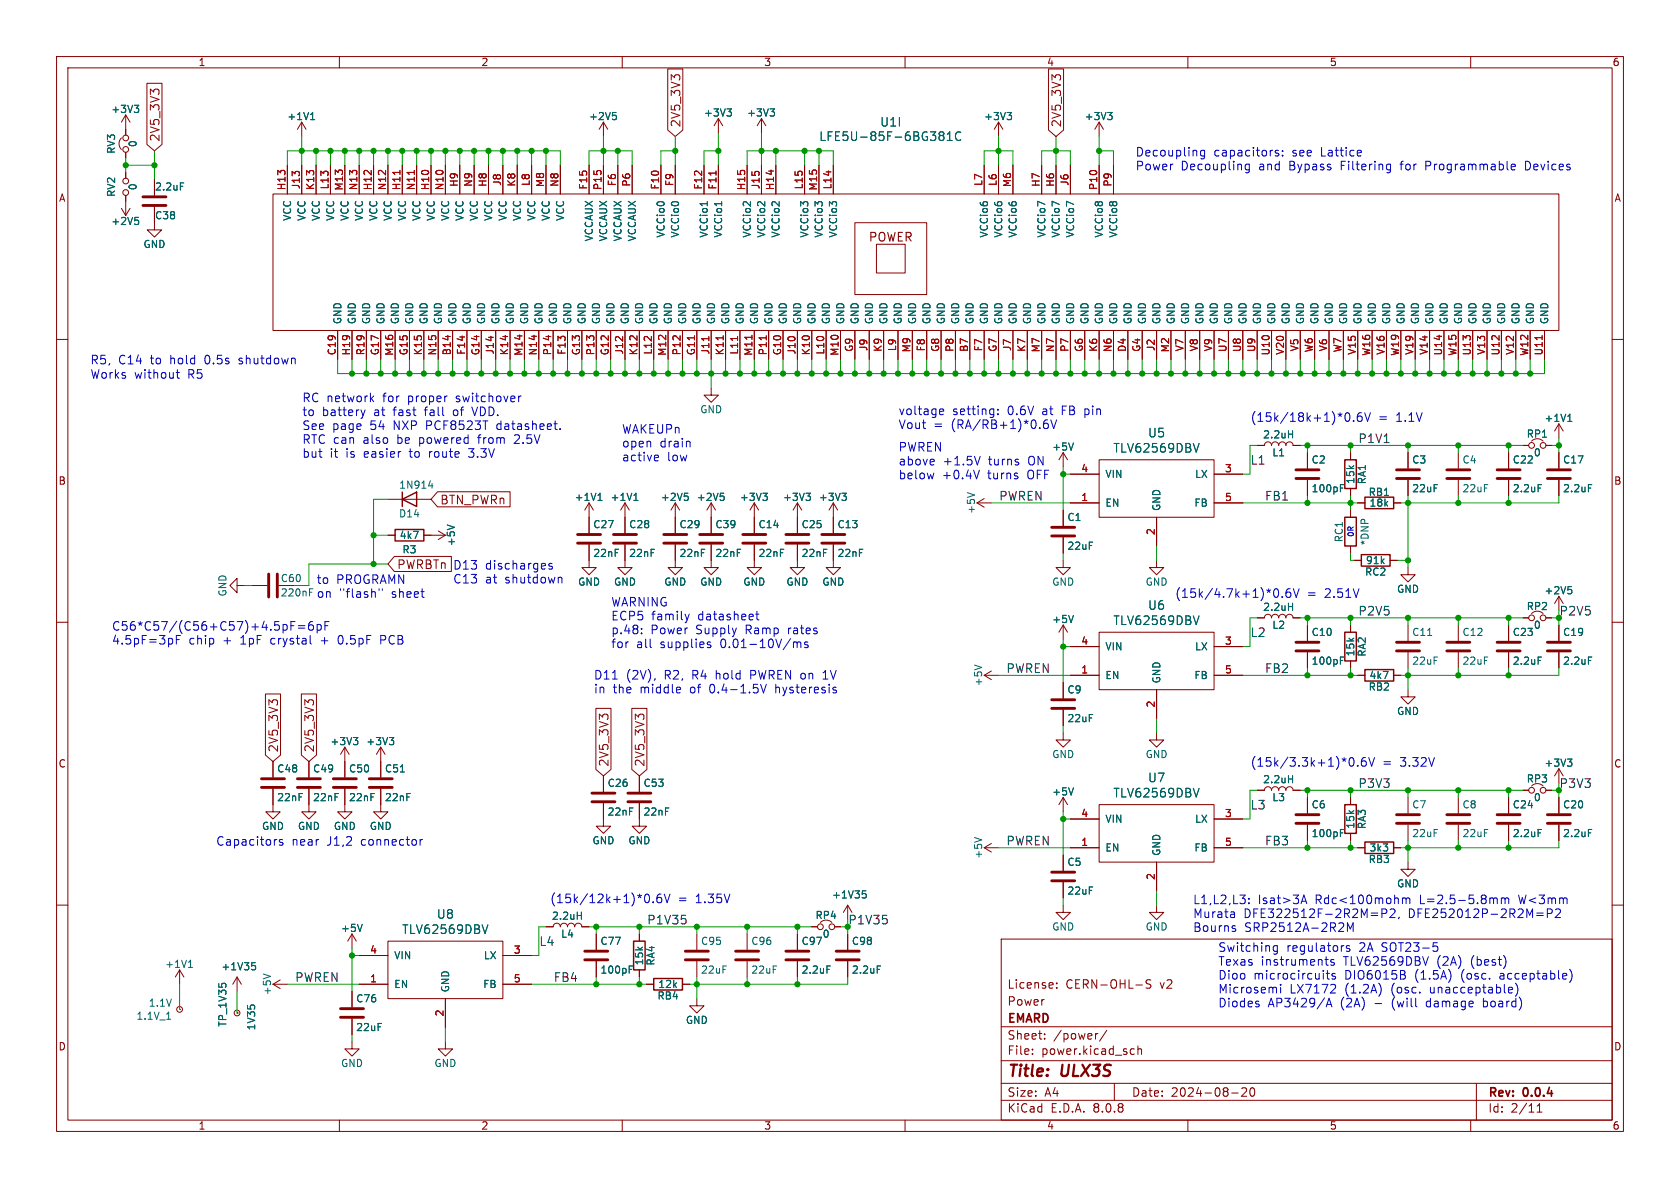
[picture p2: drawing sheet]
<svg xmlns="http://www.w3.org/2000/svg" width="297mm" height="210mm" viewBox="0 0 297 210" stroke-linecap="round" stroke-linejoin="round" font-family="sans-serif">
<defs><g id="words">
<g font-size="2.8" fill="#840000">
<text x="178" y="190.9">Title:</text>
<text x="187.7" y="190.9">ULX3S</text>
</g>
<g font-size="2.1" fill="#840000">
<text x="120.5" y="22.6" transform="rotate(-90 120.5 22.6)">2V5_3V3</text>
<text x="187.8" y="22.6" transform="rotate(-90 187.8 22.6)">2V5_3V3</text>
<text x="28.4" y="25.1" transform="rotate(-90 28.4 25.1)">2V5_3V3</text>
<text x="153.5" y="43">POWER</text>
<text x="77.7" y="89.4">BTN_PWRn</text>
<text x="49.4" y="133.1" transform="rotate(-90 49.4 133.1)">2V5_3V3</text>
<text x="55.7" y="133.1" transform="rotate(-90 55.7 133.1)">2V5_3V3</text>
<text x="107.8" y="135.6" transform="rotate(-90 107.8 135.6)">2V5_3V3</text>
<text x="114.1" y="135.6" transform="rotate(-90 114.1 135.6)">2V5_3V3</text>
<text x="178" y="178">Power</text>
<text x="178" y="175">License:</text>
<text x="188.4" y="175">CERN-OHL-S</text>
<text x="205.1" y="175">v2</text>
<text x="178" y="184">Sheet:</text>
<text x="178" y="181.2">EMARD</text>
<text x="186.2" y="184">/power/</text>
<text x="178" y="186.7">File:</text>
<text x="184.1" y="186.7">power.kicad_sch</text>
<text x="178" y="196.9">KiCad</text>
<text x="178" y="194.1">Size:</text>
<text x="184.7" y="194.1">A4</text>
<text x="185.7" y="196.9">E.D.A.</text>
<text x="193.3" y="196.9">8.0.8</text>
<text x="200" y="194.1">Date:</text>
<text x="207" y="194.1">2024-08-20</text>
<text x="263" y="194.3">Rev:</text>
<text x="263" y="196.9">Id:</text>
<text x="267.1" y="196.9">2/11</text>
<text x="269.4" y="194.3">0.0.4</text>
</g>
<g font-size="2.1" fill="#006464">
<text x="155.5" y="22.6">U1I</text>
<text x="144.7" y="25.1">LFE5U-85F-6BG381C</text>
<text x="202.9" y="77.5">U5</text>
<text x="196.7" y="80.2">TLV62569DBV</text>
<text x="196.7" y="110.7">TLV62569DBV</text>
<text x="202.9" y="108">U6</text>
<text x="196.7" y="141.2">TLV62569DBV</text>
<text x="202.9" y="138.5">U7</text>
<text x="71" y="165.3">TLV62569DBV</text>
<text x="77.1" y="162.6">U8</text>
</g>
<g font-size="2.1" fill="#0000c2">
<text x="200.7" y="27.8">Decoupling</text>
<text x="214.5" y="27.8">capacitors:</text>
<text x="228.5" y="27.8">see</text>
<text x="233.6" y="27.8">Lattice</text>
<text x="200.7" y="30.2">Power</text>
<text x="208.7" y="30.2">Decoupling</text>
<text x="222.6" y="30.2">and</text>
<text x="228" y="30.2">Bypass</text>
<text x="237.3" y="30.2">Filtering</text>
<text x="248" y="30.2">for</text>
<text x="252.5" y="30.2">Programmable</text>
<text x="270.3" y="30.2">Devices</text>
<text x="15.9" y="64.5">R5,</text>
<text x="20.9" y="64.5">C14</text>
<text x="26.6" y="64.5">to</text>
<text x="30.2" y="64.5">hold</text>
<text x="36.4" y="64.5">0.5s</text>
<text x="42.6" y="64.5">shutdown</text>
<text x="15.9" y="67.1">Works</text>
<text x="23.7" y="67.1">without</text>
<text x="33.2" y="67.1">R5</text>
<text x="53.3" y="71.2">RC network</text>
<text x="67.7" y="71.2">for</text>
<text x="72.2" y="71.2">proper</text>
<text x="80.9" y="71.2">switchover</text>
<text x="53.3" y="73.7">to</text>
<text x="53.3" y="76.1">See</text>
<text x="56.9" y="73.7">battery</text>
<text x="58.7" y="76.1">page</text>
<text x="65.5" y="76.1">54</text>
<text x="66.1" y="73.7">at</text>
<text x="69.7" y="76.1">NXP</text>
<text x="69.7" y="73.7">fast</text>
<text x="75.4" y="73.7">fall</text>
<text x="75.6" y="76.1">PCF8523T</text>
<text x="80.5" y="73.7">of</text>
<text x="84.1" y="73.7">VDD.</text>
<text x="88.2" y="76.1">datasheet.</text>
<text x="109.9" y="76.8">WAKEUPn</text>
<text x="158.7" y="73.5">voltage</text>
<text x="158.7" y="76">Vout</text>
<text x="165" y="76">=</text>
<text x="168.2" y="76">(RA/RB+1)*0.6V</text>
<text x="168.3" y="73.5">setting:</text>
<text x="178.1" y="73.5">0.6V</text>
<text x="184.4" y="73.5">at</text>
<text x="188" y="73.5">FB pin</text>
<text x="221" y="74.7">(15k/18k+1)*0.6V</text>
<text x="243.6" y="74.7">=</text>
<text x="246.8" y="74.7">1.1V</text>
<text x="53.3" y="78.6">RTC can</text>
<text x="53.3" y="81">but</text>
<text x="58.3" y="81">it</text>
<text x="61.2" y="81">is</text>
<text x="64.2" y="78.6">also</text>
<text x="64.5" y="81">easier</text>
<text x="70.3" y="78.6">be</text>
<text x="72.7" y="81">to</text>
<text x="74.3" y="78.6">powered</text>
<text x="76.2" y="81">route</text>
<text x="83.4" y="81">3.3V</text>
<text x="84.9" y="78.6">from</text>
<text x="91.5" y="78.6">2.5V</text>
<text x="109.9" y="79.2">open</text>
<text x="109.9" y="81.7">active</text>
<text x="116.6" y="79.2">drain</text>
<text x="117.9" y="81.7">low</text>
<text x="158.7" y="79.9">PWREN</text>
<text x="158.7" y="82.4">above</text>
<text x="166.7" y="82.4">+1.5V</text>
<text x="174.8" y="82.4">turns</text>
<text x="181.9" y="82.4">ON</text>
<text x="158.7" y="84.8">below</text>
<text x="166.5" y="84.8">+0.4V</text>
<text x="174.7" y="84.8">turns</text>
<text x="181.8" y="84.8">OFF</text>
<text x="70.1" y="100.8">PWRBTn D13</text>
<text x="85.8" y="100.8">discharges</text>
<text x="55.9" y="103.3">to</text>
<text x="55.9" y="105.8">on</text>
<text x="59.4" y="103.3">PROGRAMN</text>
<text x="60" y="105.8">&quot;flash&quot;</text>
<text x="69.2" y="105.8">sheet</text>
<text x="80" y="103.3">C13</text>
<text x="85.8" y="103.3">at</text>
<text x="89.3" y="103.3">shutdown</text>
<text x="107.9" y="107.3">WARNING</text>
<text x="207.6" y="105.8">(15k/4.7k+1)*0.6V</text>
<text x="231" y="105.8">=</text>
<text x="234.2" y="105.8">2.51V</text>
<text x="19.7" y="111.6">C56*C57/(C56+C57)+4.5pF=6pF</text>
<text x="107.9" y="109.8">ECP5</text>
<text x="107.9" y="112.2">p.48:</text>
<text x="115" y="112.2">Power</text>
<text x="115.1" y="109.8">family</text>
<text x="123.1" y="112.2">Supply</text>
<text x="123.4" y="109.8">datasheet</text>
<text x="131.9" y="112.2">Ramp</text>
<text x="139.5" y="112.2">rates</text>
<text x="19.7" y="114.1">4.5pF=3pF</text>
<text x="33.3" y="114.1">chip</text>
<text x="39.4" y="114.1">+</text>
<text x="42.6" y="114.1">1pF</text>
<text x="48.1" y="114.1">crystal</text>
<text x="57.1" y="114.1">+</text>
<text x="60.3" y="114.1">0.5pF</text>
<text x="67.9" y="114.1">PCB</text>
<text x="107.9" y="114.7">for</text>
<text x="112.5" y="114.7">all</text>
<text x="116.7" y="114.7">supplies</text>
<text x="127.5" y="114.7">0.01-10V/ms</text>
<text x="104.9" y="120.2">D11</text>
<text x="104.9" y="122.7">in</text>
<text x="108.3" y="122.7">the</text>
<text x="110.6" y="120.2">(2V),</text>
<text x="113.2" y="122.7">middle</text>
<text x="117.5" y="120.2">R2,</text>
<text x="122.1" y="122.7">of</text>
<text x="122.5" y="120.2">R4</text>
<text x="125.7" y="122.7">0.4-1.5V</text>
<text x="126.8" y="120.2">hold</text>
<text x="133" y="120.2">PWREN on</text>
<text x="137.5" y="122.7">hysteresis</text>
<text x="146.2" y="120.2">1V</text>
<text x="221" y="135.6">(15k/3.3k+1)*0.6V</text>
<text x="244.4" y="135.6">=</text>
<text x="247.6" y="135.6">3.32V</text>
<text x="38.1" y="149.6">Capacitors</text>
<text x="51.5" y="149.6">near</text>
<text x="57.9" y="149.6">J1,2</text>
<text x="64" y="149.6">connector</text>
<text x="97.2" y="159.8">(15k/12k+1)*0.6V</text>
<text x="119.8" y="159.8">=</text>
<text x="123" y="159.8">1.35V</text>
<text x="210.8" y="159.9">L1,L2,L3:</text>
<text x="222.4" y="159.9">Isat&gt;3A</text>
<text x="232.5" y="159.9">Rdc&lt;100mohm</text>
<text x="251.1" y="159.9">L=2.5-5.8mm</text>
<text x="268.8" y="159.9">W&lt;3mm</text>
<text x="210.8" y="162.4">Murata</text>
<text x="210.8" y="164.9">Bourns</text>
<text x="219.8" y="162.4">DFE322512F-2R2M=P2,</text>
<text x="220" y="164.9">SRP2512A-2R2M</text>
<text x="249" y="162.4">DFE252012P-2R2M=P2</text>
<text x="215.3" y="168.4">Switching</text>
<text x="215.3" y="170.8">Texas</text>
<text x="215.3" y="173.3">Dioo</text>
<text x="221.6" y="173.3">microcircuits</text>
<text x="222.9" y="170.8">instruments</text>
<text x="227.4" y="168.4">regulators</text>
<text x="237.6" y="170.8">TLV62569DBV</text>
<text x="237.8" y="173.3">DIO6015B</text>
<text x="240.3" y="168.4">2A SOT23-5</text>
<text x="250.3" y="173.3">(1.5A)</text>
<text x="254.2" y="170.8">(2A)</text>
<text x="258.5" y="173.3">(osc.</text>
<text x="260.3" y="170.8">(best)</text>
<text x="265.5" y="173.3">acceptable)</text>
<text x="215.3" y="175.7">Microsemi</text>
<text x="215.3" y="178.2">Diodes</text>
<text x="224.1" y="178.2">AP3429/A</text>
<text x="228" y="175.7">LX7172</text>
<text x="237" y="178.2">(2A)</text>
<text x="237.8" y="175.7">(1.2A)</text>
<text x="243.1" y="178.2">-</text>
<text x="246.1" y="175.7">(osc.</text>
<text x="246.3" y="178.2">(will</text>
<text x="252.5" y="178.2">damage</text>
<text x="253" y="175.7">unacceptable)</text>
<text x="262.7" y="178.2">board)</text>
</g>
<g font-size="2.1" fill="#0f0f0f">
<text x="221" y="82.2">L1</text>
<text x="240" y="78.4">P1V1</text>
<text x="176.5" y="88.6">PWREN</text>
<text x="223.5" y="88.6">FB1</text>
<text x="221" y="112.7">L2</text>
<text x="240" y="108.9">P2V5</text>
<text x="177.8" y="119.1">PWREN</text>
<text x="223.5" y="119.1">FB2</text>
<text x="221" y="143.2">L3</text>
<text x="240" y="139.4">P3V3</text>
<text x="177.8" y="149.5">PWREN</text>
<text x="223.5" y="149.5">FB3</text>
<text x="95.2" y="167.3">L4</text>
<text x="114.3" y="163.5">P1V35</text>
<text x="52.1" y="173.7">PWREN</text>
<text x="97.8" y="173.7">FB4</text>
</g>
<g font-size="2.1" fill="#009600">
<text x="275.6" y="108.9">P2V5</text>
<text x="275.6" y="139.4">P3V3</text>
<text x="149.9" y="163.5">P1V35</text>
</g>
<g font-size="1.8" fill="#840000">
<text x="35" y="11.9">1</text>
<text x="85" y="11.9">2</text>
<text x="135" y="11.9">3</text>
<text x="185" y="11.9">4</text>
<text x="235" y="11.9">5</text>
<text x="285" y="11.9">6</text>
<text x="10.3" y="35.9">A</text>
<text x="285.3" y="35.9">A</text>
<text x="10.3" y="85.9">B</text>
<text x="285.3" y="85.9">B</text>
<text x="10.3" y="135.9">C</text>
<text x="285.3" y="135.9">C</text>
<text x="10.3" y="185.9">D</text>
<text x="285.3" y="185.9">D</text>
<text x="35" y="199.9">1</text>
<text x="85" y="199.9">2</text>
<text x="135" y="199.9">3</text>
<text x="185" y="199.9">4</text>
<text x="235" y="199.9">5</text>
<text x="285" y="199.9">6</text>
</g>
<g font-size="1.8" fill="#006464">
<text x="19.6" y="20.2">+3V3</text>
<text x="50.7" y="21.4">+1V1</text>
<text x="104" y="21.4">+2V5</text>
<text x="124.4" y="20.8">+3V3</text>
<text x="132" y="20.8">+3V3</text>
<text x="173.9" y="21.4">+3V3</text>
<text x="191.7" y="21.4">+3V3</text>
<text x="20.5" y="27.3" transform="rotate(-90 20.5 27.3)">RV3</text>
<text x="24.4" y="26.1" transform="rotate(-90 24.4 26.1)">0</text>
<text x="20.5" y="34.9" transform="rotate(-90 20.5 34.9)">RV2</text>
<text x="24.4" y="33.7" transform="rotate(-90 24.4 33.7)">0</text>
<text x="27.3" y="33.9">2.2uF</text>
<text x="19.6" y="40">+2V5</text>
<text x="27.3" y="39">C38</text>
<text x="51.7" y="39.1" transform="rotate(-90 51.7 39.1)">VCC</text>
<text x="54.2" y="39.1" transform="rotate(-90 54.2 39.1)">VCC</text>
<text x="56.7" y="39.1" transform="rotate(-90 56.7 39.1)">VCC</text>
<text x="59.3" y="39.1" transform="rotate(-90 59.3 39.1)">VCC</text>
<text x="61.8" y="39.1" transform="rotate(-90 61.8 39.1)">VCC</text>
<text x="64.4" y="39.1" transform="rotate(-90 64.4 39.1)">VCC</text>
<text x="66.9" y="39.1" transform="rotate(-90 66.9 39.1)">VCC</text>
<text x="69.4" y="39.1" transform="rotate(-90 69.4 39.1)">VCC</text>
<text x="72" y="39.1" transform="rotate(-90 72 39.1)">VCC</text>
<text x="74.5" y="39.1" transform="rotate(-90 74.5 39.1)">VCC</text>
<text x="77.1" y="39.1" transform="rotate(-90 77.1 39.1)">VCC</text>
<text x="79.6" y="39.1" transform="rotate(-90 79.6 39.1)">VCC</text>
<text x="82.1" y="39.1" transform="rotate(-90 82.1 39.1)">VCC</text>
<text x="84.7" y="39.1" transform="rotate(-90 84.7 39.1)">VCC</text>
<text x="87.2" y="39.1" transform="rotate(-90 87.2 39.1)">VCC</text>
<text x="89.8" y="39.1" transform="rotate(-90 89.8 39.1)">VCC</text>
<text x="92.3" y="39.1" transform="rotate(-90 92.3 39.1)">VCC</text>
<text x="94.8" y="39.1" transform="rotate(-90 94.8 39.1)">VCC</text>
<text x="97.4" y="39.1" transform="rotate(-90 97.4 39.1)">VCC</text>
<text x="99.9" y="39.1" transform="rotate(-90 99.9 39.1)">VCC</text>
<text x="25.3" y="44">GND</text>
<text x="105" y="42.8" transform="rotate(-90 105 42.8)">VCCAUX</text>
<text x="107.5" y="42.8" transform="rotate(-90 107.5 42.8)">VCCAUX</text>
<text x="110.1" y="42.8" transform="rotate(-90 110.1 42.8)">VCCAUX</text>
<text x="112.6" y="42.8" transform="rotate(-90 112.6 42.8)">VCCAUX</text>
<text x="117.7" y="42.1" transform="rotate(-90 117.7 42.1)">VCCio0</text>
<text x="120.2" y="42.1" transform="rotate(-90 120.2 42.1)">VCCio0</text>
<text x="125.3" y="42.1" transform="rotate(-90 125.3 42.1)">VCCio1</text>
<text x="127.9" y="42.1" transform="rotate(-90 127.9 42.1)">VCCio1</text>
<text x="132.9" y="42.1" transform="rotate(-90 132.9 42.1)">VCCio2</text>
<text x="135.5" y="42.1" transform="rotate(-90 135.5 42.1)">VCCio2</text>
<text x="138" y="42.1" transform="rotate(-90 138 42.1)">VCCio2</text>
<text x="143.1" y="42.1" transform="rotate(-90 143.1 42.1)">VCCio3</text>
<text x="145.6" y="42.1" transform="rotate(-90 145.6 42.1)">VCCio3</text>
<text x="148.2" y="42.1" transform="rotate(-90 148.2 42.1)">VCCio3</text>
<text x="174.9" y="42.1" transform="rotate(-90 174.9 42.1)">VCCio6</text>
<text x="177.4" y="42.1" transform="rotate(-90 177.4 42.1)">VCCio6</text>
<text x="179.9" y="42.1" transform="rotate(-90 179.9 42.1)">VCCio6</text>
<text x="185" y="42.1" transform="rotate(-90 185 42.1)">VCCio7</text>
<text x="187.6" y="42.1" transform="rotate(-90 187.6 42.1)">VCCio7</text>
<text x="190.1" y="42.1" transform="rotate(-90 190.1 42.1)">VCCio7</text>
<text x="195.2" y="42.1" transform="rotate(-90 195.2 42.1)">VCCio8</text>
<text x="197.7" y="42.1" transform="rotate(-90 197.7 42.1)">VCCio8</text>
<text x="60.6" y="57.4" transform="rotate(-90 60.6 57.4)">GND</text>
<text x="63.1" y="57.4" transform="rotate(-90 63.1 57.4)">GND</text>
<text x="65.6" y="57.4" transform="rotate(-90 65.6 57.4)">GND</text>
<text x="68.2" y="57.4" transform="rotate(-90 68.2 57.4)">GND</text>
<text x="70.7" y="57.4" transform="rotate(-90 70.7 57.4)">GND</text>
<text x="73.3" y="57.4" transform="rotate(-90 73.3 57.4)">GND</text>
<text x="75.8" y="57.4" transform="rotate(-90 75.8 57.4)">GND</text>
<text x="78.3" y="57.4" transform="rotate(-90 78.3 57.4)">GND</text>
<text x="80.9" y="57.4" transform="rotate(-90 80.9 57.4)">GND</text>
<text x="83.4" y="57.4" transform="rotate(-90 83.4 57.4)">GND</text>
<text x="86" y="57.4" transform="rotate(-90 86 57.4)">GND</text>
<text x="88.5" y="57.4" transform="rotate(-90 88.5 57.4)">GND</text>
<text x="91" y="57.4" transform="rotate(-90 91 57.4)">GND</text>
<text x="93.6" y="57.4" transform="rotate(-90 93.6 57.4)">GND</text>
<text x="96.1" y="57.4" transform="rotate(-90 96.1 57.4)">GND</text>
<text x="98.7" y="57.4" transform="rotate(-90 98.7 57.4)">GND</text>
<text x="101.2" y="57.4" transform="rotate(-90 101.2 57.4)">GND</text>
<text x="103.7" y="57.4" transform="rotate(-90 103.7 57.4)">GND</text>
<text x="106.3" y="57.4" transform="rotate(-90 106.3 57.4)">GND</text>
<text x="108.8" y="57.4" transform="rotate(-90 108.8 57.4)">GND</text>
<text x="111.4" y="57.4" transform="rotate(-90 111.4 57.4)">GND</text>
<text x="113.9" y="57.4" transform="rotate(-90 113.9 57.4)">GND</text>
<text x="116.4" y="57.4" transform="rotate(-90 116.4 57.4)">GND</text>
<text x="119" y="57.4" transform="rotate(-90 119 57.4)">GND</text>
<text x="121.5" y="57.4" transform="rotate(-90 121.5 57.4)">GND</text>
<text x="124.1" y="57.4" transform="rotate(-90 124.1 57.4)">GND</text>
<text x="126.6" y="57.4" transform="rotate(-90 126.6 57.4)">GND</text>
<text x="129.1" y="57.4" transform="rotate(-90 129.1 57.4)">GND</text>
<text x="131.7" y="57.4" transform="rotate(-90 131.7 57.4)">GND</text>
<text x="134.2" y="57.4" transform="rotate(-90 134.2 57.4)">GND</text>
<text x="136.8" y="57.4" transform="rotate(-90 136.8 57.4)">GND</text>
<text x="139.3" y="57.4" transform="rotate(-90 139.3 57.4)">GND</text>
<text x="141.8" y="57.4" transform="rotate(-90 141.8 57.4)">GND</text>
<text x="144.4" y="57.4" transform="rotate(-90 144.4 57.4)">GND</text>
<text x="146.9" y="57.4" transform="rotate(-90 146.9 57.4)">GND</text>
<text x="149.5" y="57.4" transform="rotate(-90 149.5 57.4)">GND</text>
<text x="152" y="57.4" transform="rotate(-90 152 57.4)">GND</text>
<text x="154.5" y="57.4" transform="rotate(-90 154.5 57.4)">GND</text>
<text x="157.1" y="57.4" transform="rotate(-90 157.1 57.4)">GND</text>
<text x="159.6" y="57.4" transform="rotate(-90 159.6 57.4)">GND</text>
<text x="162.2" y="57.4" transform="rotate(-90 162.2 57.4)">GND</text>
<text x="164.7" y="57.4" transform="rotate(-90 164.7 57.4)">GND</text>
<text x="167.2" y="57.4" transform="rotate(-90 167.2 57.4)">GND</text>
<text x="169.8" y="57.4" transform="rotate(-90 169.8 57.4)">GND</text>
<text x="172.3" y="57.4" transform="rotate(-90 172.3 57.4)">GND</text>
<text x="174.9" y="57.4" transform="rotate(-90 174.9 57.4)">GND</text>
<text x="177.4" y="57.4" transform="rotate(-90 177.4 57.4)">GND</text>
<text x="179.9" y="57.4" transform="rotate(-90 179.9 57.4)">GND</text>
<text x="182.5" y="57.4" transform="rotate(-90 182.5 57.4)">GND</text>
<text x="185" y="57.4" transform="rotate(-90 185 57.4)">GND</text>
<text x="187.6" y="57.4" transform="rotate(-90 187.6 57.4)">GND</text>
<text x="190.1" y="57.4" transform="rotate(-90 190.1 57.4)">GND</text>
<text x="192.6" y="57.4" transform="rotate(-90 192.6 57.4)">GND</text>
<text x="195.2" y="57.4" transform="rotate(-90 195.2 57.4)">GND</text>
<text x="197.7" y="57.4" transform="rotate(-90 197.7 57.4)">GND</text>
<text x="200.3" y="57.4" transform="rotate(-90 200.3 57.4)">GND</text>
<text x="202.8" y="57.4" transform="rotate(-90 202.8 57.4)">GND</text>
<text x="205.3" y="57.4" transform="rotate(-90 205.3 57.4)">GND</text>
<text x="207.9" y="57.4" transform="rotate(-90 207.9 57.4)">GND</text>
<text x="210.4" y="57.4" transform="rotate(-90 210.4 57.4)">GND</text>
<text x="213" y="57.4" transform="rotate(-90 213 57.4)">GND</text>
<text x="215.5" y="57.4" transform="rotate(-90 215.5 57.4)">GND</text>
<text x="218" y="57.4" transform="rotate(-90 218 57.4)">GND</text>
<text x="220.6" y="57.4" transform="rotate(-90 220.6 57.4)">GND</text>
<text x="223.1" y="57.4" transform="rotate(-90 223.1 57.4)">GND</text>
<text x="225.7" y="57.4" transform="rotate(-90 225.7 57.4)">GND</text>
<text x="228.2" y="57.4" transform="rotate(-90 228.2 57.4)">GND</text>
<text x="230.7" y="57.4" transform="rotate(-90 230.7 57.4)">GND</text>
<text x="233.3" y="57.4" transform="rotate(-90 233.3 57.4)">GND</text>
<text x="235.8" y="57.4" transform="rotate(-90 235.8 57.4)">GND</text>
<text x="238.4" y="57.4" transform="rotate(-90 238.4 57.4)">GND</text>
<text x="240.9" y="57.4" transform="rotate(-90 240.9 57.4)">GND</text>
<text x="243.4" y="57.4" transform="rotate(-90 243.4 57.4)">GND</text>
<text x="246" y="57.4" transform="rotate(-90 246 57.4)">GND</text>
<text x="248.5" y="57.4" transform="rotate(-90 248.5 57.4)">GND</text>
<text x="251.1" y="57.4" transform="rotate(-90 251.1 57.4)">GND</text>
<text x="253.6" y="57.4" transform="rotate(-90 253.6 57.4)">GND</text>
<text x="256.1" y="57.4" transform="rotate(-90 256.1 57.4)">GND</text>
<text x="258.7" y="57.4" transform="rotate(-90 258.7 57.4)">GND</text>
<text x="261.2" y="57.4" transform="rotate(-90 261.2 57.4)">GND</text>
<text x="263.8" y="57.4" transform="rotate(-90 263.8 57.4)">GND</text>
<text x="266.3" y="57.4" transform="rotate(-90 266.3 57.4)">GND</text>
<text x="268.8" y="57.4" transform="rotate(-90 268.8 57.4)">GND</text>
<text x="271.4" y="57.4" transform="rotate(-90 271.4 57.4)">GND</text>
<text x="273.9" y="57.4" transform="rotate(-90 273.9 57.4)">GND</text>
<text x="123.7" y="73.3">GND</text>
<text x="223.2" y="77.7">2.2uH</text>
<text x="269.8" y="77.6">RP1</text>
<text x="272.9" y="74.8">+1V1</text>
<text x="185.9" y="79.9">+5V</text>
<text x="224.8" y="80.9">L1</text>
<text x="231.8" y="82.1">C2</text>
<text x="249.6" y="82.1">C3</text>
<text x="258.5" y="82.1">C4</text>
<text x="267.3" y="82.1">C22</text>
<text x="271.1" y="80.9">0</text>
<text x="276.2" y="82.1">C17</text>
<text x="70.5" y="86.6">1N914</text>
<text x="101.5" y="88.7">+1V1</text>
<text x="107.8" y="88.7">+1V1</text>
<text x="116.7" y="88.7">+2V5</text>
<text x="123.1" y="88.7">+2V5</text>
<text x="130.7" y="88.7">+3V3</text>
<text x="138.3" y="88.7">+3V3</text>
<text x="144.7" y="88.7">+3V3</text>
<text x="195.3" y="89.8">EN</text>
<text x="195.3" y="84.7">VIN</text>
<text x="211.1" y="89.8">FB</text>
<text x="211.2" y="84.7">LX</text>
<text x="231.8" y="87.2">100pF</text>
<text x="239.6" y="85.6" transform="rotate(-90 239.6 85.6)">15k</text>
<text x="241.7" y="85.7" transform="rotate(-90 241.7 85.7)">RA1</text>
<text x="241.9" y="87.9">RB1</text>
<text x="242" y="89.8">18k</text>
<text x="249.6" y="87.2">22uF</text>
<text x="258.5" y="87.2">22uF</text>
<text x="267.3" y="87.2">2.2uF</text>
<text x="276.2" y="87.2">2.2uF</text>
<text x="70.4" y="91.7">D14</text>
<text x="70.6" y="95.5">4k7</text>
<text x="104.8" y="93.6">C27</text>
<text x="111.1" y="93.6">C28</text>
<text x="120" y="93.6">C29</text>
<text x="126.4" y="93.6">C39</text>
<text x="134" y="93.6">C14</text>
<text x="141.6" y="93.6">C25</text>
<text x="148" y="93.6">C13</text>
<text x="172.6" y="90.9" transform="rotate(-90 172.6 90.9)">+5V</text>
<text x="188.6" y="92.3">C1</text>
<text x="205.3" y="90.4" transform="rotate(-90 205.3 90.4)">GND</text>
<text x="237.6" y="96" transform="rotate(-90 237.6 96)">RC1</text>
<text x="71" y="98">R3</text>
<text x="80.6" y="96.7" transform="rotate(-90 80.6 96.7)">+5V</text>
<text x="104.8" y="98.7">22nF</text>
<text x="111.1" y="98.7">22nF</text>
<text x="120" y="98.7">22nF</text>
<text x="126.4" y="98.7">22nF</text>
<text x="134" y="98.7">22nF</text>
<text x="141.6" y="98.7">22nF</text>
<text x="148" y="98.7">22nF</text>
<text x="188.6" y="97.4">22uF</text>
<text x="241.2" y="102">RC2</text>
<text x="241.4" y="99.9">91k</text>
<text x="242.2" y="96.5" transform="rotate(-90 242.2 96.5)">*DNP</text>
<text x="40.2" y="105.5" transform="rotate(-90 40.2 105.5)">GND</text>
<text x="49.5" y="105.6">220nF</text>
<text x="49.5" y="103.1">C60</text>
<text x="102.1" y="103.7">GND</text>
<text x="108.5" y="103.7">GND</text>
<text x="117.3" y="103.7">GND</text>
<text x="123.7" y="103.7">GND</text>
<text x="131.3" y="103.7">GND</text>
<text x="138.9" y="103.7">GND</text>
<text x="145.3" y="103.7">GND</text>
<text x="185.9" y="103.7">GND</text>
<text x="202.4" y="103.7">GND</text>
<text x="246.9" y="105">GND</text>
<text x="272.9" y="105.3">+2V5</text>
<text x="185.9" y="110.3">+5V</text>
<text x="223.2" y="108.2">2.2uH</text>
<text x="224.8" y="111.4">L2</text>
<text x="231.8" y="112.6">C10</text>
<text x="249.6" y="112.6">C11</text>
<text x="258.5" y="112.6">C12</text>
<text x="267.3" y="112.6">C23</text>
<text x="269.8" y="108.1">RP2</text>
<text x="271.1" y="111.4">0</text>
<text x="276.2" y="112.6">C19</text>
<text x="195.3" y="115.2">VIN</text>
<text x="211.2" y="115.2">LX</text>
<text x="231.8" y="117.7">100pF</text>
<text x="239.6" y="116.1" transform="rotate(-90 239.6 116.1)">15k</text>
<text x="241.7" y="116.2" transform="rotate(-90 241.7 116.2)">RA2</text>
<text x="249.6" y="117.7">22uF</text>
<text x="258.5" y="117.7">22uF</text>
<text x="267.3" y="117.7">2.2uF</text>
<text x="276.2" y="117.7">2.2uF</text>
<text x="173.8" y="121.4" transform="rotate(-90 173.8 121.4)">+5V</text>
<text x="188.6" y="122.8">C9</text>
<text x="195.3" y="120.2">EN</text>
<text x="205.3" y="120.9" transform="rotate(-90 205.3 120.9)">GND</text>
<text x="211.1" y="120.2">FB</text>
<text x="241.9" y="122.3">RB2</text>
<text x="242" y="120.2">4k7</text>
<text x="58.3" y="131.9">+3V3</text>
<text x="64.7" y="131.9">+3V3</text>
<text x="188.6" y="127.9">22uF</text>
<text x="246.9" y="126.6">GND</text>
<text x="48.9" y="136.8">C48</text>
<text x="55.3" y="136.8">C49</text>
<text x="61.6" y="136.8">C50</text>
<text x="68" y="136.8">C51</text>
<text x="185.9" y="134.2">GND</text>
<text x="202.4" y="134.2">GND</text>
<text x="272.9" y="135.7">+3V3</text>
<text x="48.9" y="141.8">22nF</text>
<text x="55.3" y="141.8">22nF</text>
<text x="61.6" y="141.8">22nF</text>
<text x="68" y="141.8">22nF</text>
<text x="107.3" y="139.3">C26</text>
<text x="113.7" y="139.3">C53</text>
<text x="185.9" y="140.8">+5V</text>
<text x="223.2" y="138.7">2.2uH</text>
<text x="224.8" y="141.8">L3</text>
<text x="231.8" y="143.1">C6</text>
<text x="249.6" y="143.1">C7</text>
<text x="258.5" y="143.1">C8</text>
<text x="267.3" y="143.1">C24</text>
<text x="269.8" y="138.5">RP3</text>
<text x="271.1" y="141.8">0</text>
<text x="276.2" y="143.1">C20</text>
<text x="46.2" y="146.9">GND</text>
<text x="52.6" y="146.9">GND</text>
<text x="58.9" y="146.9">GND</text>
<text x="65.3" y="146.9">GND</text>
<text x="104.6" y="149.5">GND</text>
<text x="107.3" y="144.4">22nF</text>
<text x="111" y="149.5">GND</text>
<text x="113.7" y="144.4">22nF</text>
<text x="195.3" y="145.6">VIN</text>
<text x="211.2" y="145.6">LX</text>
<text x="231.8" y="148.2">100pF</text>
<text x="239.6" y="146.6" transform="rotate(-90 239.6 146.6)">15k</text>
<text x="241.7" y="146.7" transform="rotate(-90 241.7 146.7)">RA3</text>
<text x="249.6" y="148.2">22uF</text>
<text x="258.5" y="148.2">22uF</text>
<text x="267.3" y="148.2">2.2uF</text>
<text x="276.2" y="148.2">2.2uF</text>
<text x="173.8" y="151.9" transform="rotate(-90 173.8 151.9)">+5V</text>
<text x="188.6" y="153.3">C5</text>
<text x="195.3" y="150.7">EN</text>
<text x="205.3" y="151.4" transform="rotate(-90 205.3 151.4)">GND</text>
<text x="211.1" y="150.7">FB</text>
<text x="241.9" y="152.8">RB3</text>
<text x="242" y="150.7">3k3</text>
<text x="147" y="159">+1V35</text>
<text x="188.6" y="158.3">22uF</text>
<text x="246.9" y="157.1">GND</text>
<text x="60.2" y="164.9">+5V</text>
<text x="97.5" y="162.8">2.2uH</text>
<text x="99.1" y="166">L4</text>
<text x="106.1" y="167.2">C77</text>
<text x="123.8" y="167.2">C95</text>
<text x="132.7" y="167.2">C96</text>
<text x="141.6" y="167.2">C97</text>
<text x="144.1" y="162.7">RP4</text>
<text x="145.3" y="166">0</text>
<text x="150.5" y="167.2">C98</text>
<text x="185.9" y="164.7">GND</text>
<text x="202.4" y="164.7">GND</text>
<text x="29.1" y="171.3">+1V1</text>
<text x="39" y="171.7">+1V35</text>
<text x="69.6" y="169.8">VIN</text>
<text x="85.4" y="169.8">LX</text>
<text x="106.1" y="172.3">100pF</text>
<text x="113.9" y="170.7" transform="rotate(-90 113.9 170.7)">15k</text>
<text x="115.9" y="170.8" transform="rotate(-90 115.9 170.8)">RA4</text>
<text x="123.8" y="172.3">22uF</text>
<text x="132.7" y="172.3">22uF</text>
<text x="141.6" y="172.3">2.2uF</text>
<text x="150.5" y="172.3">2.2uF</text>
<text x="26.2" y="178.2">1.1V</text>
<text x="48.1" y="176" transform="rotate(-90 48.1 176)">+5V</text>
<text x="62.9" y="177.4">C76</text>
<text x="69.6" y="174.9">EN</text>
<text x="79.6" y="175.5" transform="rotate(-90 79.6 175.5)">GND</text>
<text x="85.3" y="174.9">FB</text>
<text x="116.1" y="176.9">RB4</text>
<text x="116.3" y="174.9">12k</text>
<text x="24" y="180.5">1.1V_1</text>
<text x="40.2" y="181.6" transform="rotate(-90 40.2 181.6)">TP_1V35</text>
<text x="45.3" y="182.2" transform="rotate(-90 45.3 182.2)">1V35</text>
<text x="62.9" y="182.5">22uF</text>
<text x="121.2" y="181.2">GND</text>
<text x="60.2" y="188.8">GND</text>
<text x="76.7" y="188.8">GND</text>
</g>
<g font-size="1.8" fill="#a90000">
<text x="50.5" y="33.7" transform="rotate(-90 50.5 33.7)">H13</text>
<text x="53.1" y="33.5" transform="rotate(-90 53.1 33.5)">J13</text>
<text x="55.6" y="33.7" transform="rotate(-90 55.6 33.7)">K13</text>
<text x="58.2" y="33.6" transform="rotate(-90 58.2 33.6)">L13</text>
<text x="60.7" y="33.8" transform="rotate(-90 60.7 33.8)">M13</text>
<text x="63.2" y="33.7" transform="rotate(-90 63.2 33.7)">N13</text>
<text x="65.8" y="33.7" transform="rotate(-90 65.8 33.7)">H12</text>
<text x="68.3" y="33.7" transform="rotate(-90 68.3 33.7)">N12</text>
<text x="70.9" y="33.7" transform="rotate(-90 70.9 33.7)">H11</text>
<text x="73.4" y="33.7" transform="rotate(-90 73.4 33.7)">N11</text>
<text x="75.9" y="33.7" transform="rotate(-90 75.9 33.7)">H10</text>
<text x="78.5" y="33.7" transform="rotate(-90 78.5 33.7)">N10</text>
<text x="81" y="33.1" transform="rotate(-90 81 33.1)">H9</text>
<text x="83.6" y="33.1" transform="rotate(-90 83.6 33.1)">N9</text>
<text x="86.1" y="33.1" transform="rotate(-90 86.1 33.1)">H8</text>
<text x="88.6" y="32.9" transform="rotate(-90 88.6 32.9)">J8</text>
<text x="91.2" y="33.1" transform="rotate(-90 91.2 33.1)">K8</text>
<text x="93.7" y="33" transform="rotate(-90 93.7 33)">L8</text>
<text x="96.3" y="33.2" transform="rotate(-90 96.3 33.2)">M8</text>
<text x="98.8" y="33.1" transform="rotate(-90 98.8 33.1)">N8</text>
<text x="103.9" y="33.6" transform="rotate(-90 103.9 33.6)">F15</text>
<text x="106.4" y="33.7" transform="rotate(-90 106.4 33.7)">P15</text>
<text x="109" y="33" transform="rotate(-90 109 33)">F6</text>
<text x="111.5" y="33.1" transform="rotate(-90 111.5 33.1)">P6</text>
<text x="116.6" y="33.6" transform="rotate(-90 116.6 33.6)">F10</text>
<text x="119.1" y="33" transform="rotate(-90 119.1 33)">F9</text>
<text x="124.2" y="33.6" transform="rotate(-90 124.2 33.6)">F12</text>
<text x="126.7" y="33.6" transform="rotate(-90 126.7 33.6)">F11</text>
<text x="131.8" y="33.7" transform="rotate(-90 131.8 33.7)">H15</text>
<text x="134.4" y="33.5" transform="rotate(-90 134.4 33.5)">J15</text>
<text x="136.9" y="33.7" transform="rotate(-90 136.9 33.7)">H14</text>
<text x="142" y="33.6" transform="rotate(-90 142 33.6)">L15</text>
<text x="144.5" y="33.8" transform="rotate(-90 144.5 33.8)">M15</text>
<text x="147.1" y="33.6" transform="rotate(-90 147.1 33.6)">L14</text>
<text x="173.7" y="33" transform="rotate(-90 173.7 33)">L7</text>
<text x="176.3" y="33" transform="rotate(-90 176.3 33)">L6</text>
<text x="178.8" y="33.2" transform="rotate(-90 178.8 33.2)">M6</text>
<text x="183.9" y="33.1" transform="rotate(-90 183.9 33.1)">H7</text>
<text x="186.4" y="33.1" transform="rotate(-90 186.4 33.1)">H6</text>
<text x="189" y="32.9" transform="rotate(-90 189 32.9)">J6</text>
<text x="194.1" y="33.7" transform="rotate(-90 194.1 33.7)">P10</text>
<text x="196.6" y="33.1" transform="rotate(-90 196.6 33.1)">P9</text>
<text x="59.4" y="62.9" transform="rotate(-90 59.4 62.9)">C19</text>
<text x="62" y="62.9" transform="rotate(-90 62 62.9)">H19</text>
<text x="64.5" y="62.9" transform="rotate(-90 64.5 62.9)">R19</text>
<text x="67.1" y="62.9" transform="rotate(-90 67.1 62.9)">G17</text>
<text x="69.6" y="63" transform="rotate(-90 69.6 63)">M16</text>
<text x="72.1" y="62.9" transform="rotate(-90 72.1 62.9)">G15</text>
<text x="74.7" y="62.9" transform="rotate(-90 74.7 62.9)">K15</text>
<text x="77.2" y="62.9" transform="rotate(-90 77.2 62.9)">N15</text>
<text x="79.8" y="62.9" transform="rotate(-90 79.8 62.9)">B14</text>
<text x="82.3" y="62.8" transform="rotate(-90 82.3 62.8)">F14</text>
<text x="84.8" y="62.9" transform="rotate(-90 84.8 62.9)">G14</text>
<text x="87.4" y="62.8" transform="rotate(-90 87.4 62.8)">J14</text>
<text x="89.9" y="62.9" transform="rotate(-90 89.9 62.9)">K14</text>
<text x="92.5" y="63" transform="rotate(-90 92.5 63)">M14</text>
<text x="95" y="62.9" transform="rotate(-90 95 62.9)">N14</text>
<text x="97.5" y="62.9" transform="rotate(-90 97.5 62.9)">P14</text>
<text x="100.1" y="62.8" transform="rotate(-90 100.1 62.8)">F13</text>
<text x="102.6" y="62.9" transform="rotate(-90 102.6 62.9)">G13</text>
<text x="105.2" y="62.9" transform="rotate(-90 105.2 62.9)">P13</text>
<text x="107.7" y="62.9" transform="rotate(-90 107.7 62.9)">G12</text>
<text x="110.2" y="62.8" transform="rotate(-90 110.2 62.8)">J12</text>
<text x="112.8" y="62.9" transform="rotate(-90 112.8 62.9)">K12</text>
<text x="115.3" y="62.8" transform="rotate(-90 115.3 62.8)">L12</text>
<text x="117.9" y="63" transform="rotate(-90 117.9 63)">M12</text>
<text x="120.4" y="62.9" transform="rotate(-90 120.4 62.9)">P12</text>
<text x="122.9" y="62.9" transform="rotate(-90 122.9 62.9)">G11</text>
<text x="125.5" y="62.8" transform="rotate(-90 125.5 62.8)">J11</text>
<text x="128" y="62.9" transform="rotate(-90 128 62.9)">K11</text>
<text x="130.6" y="62.8" transform="rotate(-90 130.6 62.8)">L11</text>
<text x="133.1" y="63" transform="rotate(-90 133.1 63)">M11</text>
<text x="135.6" y="62.9" transform="rotate(-90 135.6 62.9)">P11</text>
<text x="138.2" y="62.9" transform="rotate(-90 138.2 62.9)">G10</text>
<text x="140.7" y="62.8" transform="rotate(-90 140.7 62.8)">J10</text>
<text x="143.3" y="62.9" transform="rotate(-90 143.3 62.9)">K10</text>
<text x="145.8" y="62.8" transform="rotate(-90 145.8 62.8)">L10</text>
<text x="148.3" y="63" transform="rotate(-90 148.3 63)">M10</text>
<text x="150.9" y="62.3" transform="rotate(-90 150.9 62.3)">G9</text>
<text x="153.4" y="62.2" transform="rotate(-90 153.4 62.2)">J9</text>
<text x="156" y="62.3" transform="rotate(-90 156 62.3)">K9</text>
<text x="158.5" y="62.2" transform="rotate(-90 158.5 62.2)">L9</text>
<text x="161" y="62.4" transform="rotate(-90 161 62.4)">M9</text>
<text x="163.6" y="62.2" transform="rotate(-90 163.6 62.2)">F8</text>
<text x="166.1" y="62.3" transform="rotate(-90 166.1 62.3)">G8</text>
<text x="168.7" y="62.3" transform="rotate(-90 168.7 62.3)">P8</text>
<text x="171.2" y="62.3" transform="rotate(-90 171.2 62.3)">B7</text>
<text x="173.7" y="62.2" transform="rotate(-90 173.7 62.2)">F7</text>
<text x="176.3" y="62.3" transform="rotate(-90 176.3 62.3)">G7</text>
<text x="178.8" y="62.2" transform="rotate(-90 178.8 62.2)">J7</text>
<text x="181.4" y="62.3" transform="rotate(-90 181.4 62.3)">K7</text>
<text x="183.9" y="62.4" transform="rotate(-90 183.9 62.4)">M7</text>
<text x="186.4" y="62.3" transform="rotate(-90 186.4 62.3)">N7</text>
<text x="189" y="62.3" transform="rotate(-90 189 62.3)">P7</text>
<text x="191.5" y="62.3" transform="rotate(-90 191.5 62.3)">G6</text>
<text x="194.1" y="62.3" transform="rotate(-90 194.1 62.3)">K6</text>
<text x="196.6" y="62.3" transform="rotate(-90 196.6 62.3)">N6</text>
<text x="199.1" y="62.3" transform="rotate(-90 199.1 62.3)">D4</text>
<text x="201.7" y="62.3" transform="rotate(-90 201.7 62.3)">G4</text>
<text x="204.2" y="62.2" transform="rotate(-90 204.2 62.2)">J2</text>
<text x="206.8" y="62.4" transform="rotate(-90 206.8 62.4)">M2</text>
<text x="209.3" y="62.2" transform="rotate(-90 209.3 62.2)">V7</text>
<text x="211.8" y="62.2" transform="rotate(-90 211.8 62.2)">V8</text>
<text x="214.4" y="62.2" transform="rotate(-90 214.4 62.2)">V9</text>
<text x="216.9" y="62.3" transform="rotate(-90 216.9 62.3)">U7</text>
<text x="219.5" y="62.3" transform="rotate(-90 219.5 62.3)">U8</text>
<text x="222" y="62.3" transform="rotate(-90 222 62.3)">U9</text>
<text x="224.5" y="62.9" transform="rotate(-90 224.5 62.9)">U10</text>
<text x="227.1" y="62.8" transform="rotate(-90 227.1 62.8)">V20</text>
<text x="229.6" y="62.2" transform="rotate(-90 229.6 62.2)">V5</text>
<text x="232.2" y="62.4" transform="rotate(-90 232.2 62.4)">W6</text>
<text x="234.7" y="62.2" transform="rotate(-90 234.7 62.2)">V6</text>
<text x="237.2" y="62.4" transform="rotate(-90 237.2 62.4)">W7</text>
<text x="239.8" y="62.8" transform="rotate(-90 239.8 62.8)">V15</text>
<text x="242.3" y="63" transform="rotate(-90 242.3 63)">W16</text>
<text x="244.9" y="62.8" transform="rotate(-90 244.9 62.8)">V16</text>
<text x="247.4" y="63" transform="rotate(-90 247.4 63)">W19</text>
<text x="249.9" y="62.8" transform="rotate(-90 249.9 62.8)">V19</text>
<text x="252.5" y="62.8" transform="rotate(-90 252.5 62.8)">V14</text>
<text x="255" y="62.9" transform="rotate(-90 255 62.9)">U14</text>
<text x="257.6" y="63" transform="rotate(-90 257.6 63)">W15</text>
<text x="260.1" y="62.9" transform="rotate(-90 260.1 62.9)">U13</text>
<text x="262.6" y="62.8" transform="rotate(-90 262.6 62.8)">V13</text>
<text x="265.2" y="62.9" transform="rotate(-90 265.2 62.9)">U12</text>
<text x="267.7" y="62.8" transform="rotate(-90 267.7 62.8)">V12</text>
<text x="270.3" y="63" transform="rotate(-90 270.3 63)">W12</text>
<text x="272.8" y="62.9" transform="rotate(-90 272.8 62.9)">U11</text>
<text x="191.1" y="83.6">4</text>
<text x="216.5" y="83.6">3</text>
<text x="191.1" y="88.6">1</text>
<text x="216.5" y="88.6">5</text>
<text x="204.2" y="94.7" transform="rotate(-90 204.2 94.7)">2</text>
<text x="191.1" y="119.1">1</text>
<text x="191.1" y="114">4</text>
<text x="216.5" y="114">3</text>
<text x="216.5" y="119.1">5</text>
<text x="204.2" y="125.2" transform="rotate(-90 204.2 125.2)">2</text>
<text x="191.1" y="149.6">1</text>
<text x="191.1" y="144.5">4</text>
<text x="216.5" y="144.5">3</text>
<text x="216.5" y="149.6">5</text>
<text x="204.2" y="155.6" transform="rotate(-90 204.2 155.6)">2</text>
<text x="65.3" y="173.7">1</text>
<text x="65.3" y="168.7">4</text>
<text x="90.7" y="168.7">3</text>
<text x="90.7" y="173.7">5</text>
<text x="78.5" y="179.8" transform="rotate(-90 78.5 179.8)">2</text>
</g>
<text font-size="1.4" fill="#0000c2" x="239.4" y="95" transform="rotate(-90 239.4 95)">0R</text>
</g></defs>
<g fill="none" stroke="#840000" stroke-width=".18">
<path d="M10 10h277v190h-277zM12 12h273v186h-273zM26 14.7h2.6v10.8l-1.3 1.2-1.3-1.2zM60 10v2M110 10v2M118 12.2h2.7v10.8l-1.3 1.1-1.4-1.1zM160 10v2M185.4 12.2h2.6v10.8l-1.3 1.1-1.3-1.1zM210 10v2M260 10v2M21.5 24.4a1.44 1.44 0 0 0 0 2M21.5 36.8l.7 1.3"/>
<path d="M22.2 20.3l-.7 1.3M22.2 20.3v3.6M22.2 26.9v1M22.2 30.5v1M22.2 34.5v3.6M22.2 20.3l.8 1.3M23 36.8l-.8 1.3M27.3 36.6v4h1.3l-1.3 1.3-1.3-1.3h1.3M27.3 31.8v2.7M48.3 34.3h227.3v24.1h-227.3zM50.8 29.2v5.1M53.3 21.6l-.7 1.3"/>
<path d="M53.3 21.6v2.5M53.3 29.2v5.1M53.3 21.6l.8 1.3M55.9 29.2v5.1M58.4 29.2v5.1M61 29.2v5.1M63.5 29.2v5.1M66 29.2v5.1M68.6 29.2v5.1M71.1 29.2v5.1M73.7 29.2v5.1M76.2 29.2v5.1"/>
<path d="M78.7 29.2v5.1M81.3 29.2v5.1M83.8 29.2v5.1M86.4 29.2v5.1M88.9 29.2v5.1M91.4 29.2v5.1M94 29.2v5.1M96.5 29.2v5.1M99.1 29.2v5.1M104.1 29.2v5.1M106.7 21.6v2.5M106.7 29.2v5.1"/>
<path d="M106.7 21.6l-.8 1.3M106.7 21.6l.7 1.3M109.2 29.2v5.1M111.8 29.2v5.1M116.8 29.2v5.1M119.4 29.2v5.1M124.5 29.2v5.1M127 21v2.5M127 29.2v5.1M127 21l-.8 1.2M127 21l.8 1.2M132.1 29.2v5.1"/>
<path d="M134.6 21v2.5M134.6 29.2v5.1M134.6 21l-.7 1.2M134.6 21l.8 1.2M137.2 29.2v5.1M142.2 29.2v5.1M144.8 29.2v5.1M147.3 29.2v5.1M151.1 39.4h12.7v12.7h-12.7zM174 29.2v5.1M176.5 21.6v2.5M176.5 29.2v5.1"/>
<path d="M176.5 21.6l-.7 1.3M176.5 21.6l.8 1.3M179.1 29.2v5.1M184.1 29.2v5.1M186.7 29.2v5.1M189.2 29.2v5.1M194.3 21.6l-.8 1.3M194.3 21.6v2.5M194.3 29.2v5.1M194.3 21.6l.8 1.3M196.8 29.2v5.1M59.7 58.4v5.1"/>
<path d="M62.2 58.4v5.1M64.8 58.4v5.1M67.3 58.4v5.1M69.8 58.4v5.1M72.4 58.4v5.1M74.9 58.4v5.1M77.5 58.4v5.1M80 58.4v5.1M82.5 58.4v5.1M85.1 58.4v5.1M87.6 58.4v5.1M90.2 58.4v5.1"/>
<path d="M92.7 58.4v5.1M95.2 58.4v5.1M97.8 58.4v5.1M100.3 58.4v5.1M102.9 58.4v5.1M105.4 58.4v5.1M107.9 58.4v5.1M110.5 58.4v5.1M113 58.4v5.1M115.6 58.4v5.1M118.1 58.4v5.1M120.6 58.4v5.1"/>
<path d="M123.2 58.4v5.1M125.7 58.4v5.1M128.3 58.4v5.1M130.8 58.4v5.1M133.3 58.4v5.1M135.9 58.4v5.1M138.4 58.4v5.1M141 58.4v5.1M143.5 58.4v5.1M146 58.4v5.1M148.6 58.4v5.1M151.1 58.4v5.1"/>
<path d="M153.7 58.4v5.1M154.9 43.2h5.1v5.1h-5.1zM156.2 58.4v5.1M158.7 58.4v5.1M161.3 58.4v5.1M163.8 58.4v5.1M166.4 58.4v5.1M168.9 58.4v5.1M171.4 58.4v5.1M174 58.4v5.1M176.5 58.4v5.1M179.1 58.4v5.1"/>
<path d="M181.6 58.4v5.1M184.1 58.4v5.1M186.7 58.4v5.1M189.2 58.4v5.1M191.8 58.4v5.1M194.3 58.4v5.1M196.8 58.4v5.1M199.4 58.4v5.1M201.9 58.4v5.1M204.5 58.4v5.1M207 58.4v5.1M209.5 58.4v5.1"/>
<path d="M212.1 58.4v5.1M214.6 58.4v5.1M217.2 58.4v5.1M219.7 58.4v5.1M222.2 58.4v5.1M224.8 58.4v5.1M227.3 58.4v5.1M229.9 58.4v5.1M232.4 58.4v5.1M234.9 58.4v5.1M237.5 58.4v5.1M240 58.4v5.1"/>
<path d="M242.6 58.4v5.1M245.1 58.4v5.1M247.6 58.4v5.1M250.2 58.4v5.1M252.7 58.4v5.1M255.3 58.4v5.1M257.8 58.4v5.1M260.3 58.4v5.1M262.9 58.4v5.1M265.4 58.4v5.1M268 58.4v5.1M270.5 58.4v5.1"/>
<path d="M273 58.4v5.1M10 60h2M125.7 68.6v1.3h1.3l-1.3 1.2-1.2-1.2h1.2M222.2 78.7h1.3a.64 .64 0 0 1 .7-.6 .64 .64 0 0 1 .6 .6 .64 .64 0 0 1 .6-.6 .64 .64 0 0 1 .7 .6 .64 .64 0 0 1 .6-.6 .64 .64 0 0 1 .6 .6 .64 .64 0 0 1 .7-.6 .64 .64 0 0 1 .6 .6h1.3M269.2 78.7h1.1M273.3 78.7h1M275.6 74.9v2.6M275.6 74.9l-.8 1.3M275.6 74.9l.8 1.3M285 60h2M68.6 94.6h1.2M68.6 88.3h7.6"/>
<path d="M69.7 98.4h10.1v2.6h-10.1l-1.1-1.3zM74.9 94.6h3.8M77.3 86.9h12.9v2.7h-12.9l-1.1-1.3zM77.5 93.9l1.2 .7M78.7 94.6l-1.2 .8M104.1 96.3v4h1.3l-1.3 1.3-1.2-1.3h1.2M104.1 88.9l-.7 1.3M104.1 88.9v5.3M104.1 88.9l.8 1.3M110.5 96.3v4h1.3l-1.3 1.3-1.3-1.3h1.3M110.5 88.9v5.3M110.5 88.9l-.8 1.3"/>
<path d="M110.5 88.9l.8 1.3M119.4 96.3v4h1.2l-1.2 1.3-1.3-1.3h1.3M119.4 88.9l-.8 1.3M119.4 88.9v5.3M119.4 88.9l.7 1.3M125.7 96.3v4h1.3l-1.3 1.3-1.2-1.3h1.2M125.7 88.9v5.3M125.7 88.9l-.7 1.3M125.7 88.9l.8 1.3M133.3 96.3v4h1.3l-1.3 1.3-1.2-1.3h1.2M133.3 88.9v5.3M133.3 88.9l-.7 1.3"/>
<path d="M133.3 88.9l.8 1.3M141 96.3v4h1.2l-1.2 1.3-1.3-1.3h1.3M141 88.9v5.3M141 88.9l-.8 1.3M141 88.9l.7 1.3M147.3 96.3v4h1.3l-1.3 1.3-1.3-1.3h1.3M147.3 88.9l-.7 1.3M147.3 88.9v5.3M147.3 88.9l.8 1.3M172.7 88.9h2.6M172.7 88.9l1.3 .8M174 88.1l-1.3 .8"/>
<path d="M188 99.1v1.2h1.2l-1.2 1.3-1.3-1.3h1.3M188 80l-.8 1.3M188 80v2.6M188 90.2v2.8M188 95v2.8M188 80l.7 1.3M189.2 88.9h5.1M189.2 83.8h5.1M194.3 81.3h20.3v10.1h-20.3zM204.5 99.1v1.2h1.2l-1.2 1.3-1.3-1.3h1.3M204.5 91.4v5.1M214.6 88.9h5.1"/>
<path d="M214.6 83.8h5.1M231.1 80v2.8M231.1 84.8v2.8M238.8 80v1.3M238.8 86.4v1.2M238.8 90.2v1.2M238.8 96.5v1.3M239.4 99.1h1.3M240 88.9h1.3M245.7 99.1h1.3M246.4 88.9h1.2M248.9 80v2.8"/>
<path d="M248.9 84.8v2.8M257.8 80v2.8M257.8 84.8v2.8M266.7 80v2.8M266.7 84.8v2.8M275.6 80v2.8M275.6 84.8v2.8M10 110h2M41.9 103.5v-1.3l-1.3 1.3 1.3 1.3v-1.3h1.3M44.4 103.5h2.8M174 119.4h2.5M174 119.4l1.3 .7"/>
<path d="M175.3 118.6l-1.3 .8M188 110.5v2.5M188 110.5l-.8 1.3M188 110.5l.7 1.3M189.2 119.4h5.1M189.2 114.3h5.1M194.3 111.8h20.3v10.1h-20.3zM214.6 119.4h5.1M214.6 114.3h5.1M222.2 109.2h1.3a.64 .64 0 0 1 .7-.6 .64 .64 0 0 1 .6 .6 .64 .64 0 0 1 .6-.6 .64 .64 0 0 1 .7 .6 .64 .64 0 0 1 .6-.6 .64 .64 0 0 1 .6 .6 .64 .64 0 0 1 .7-.6 .64 .64 0 0 1 .6 .6h1.3M231.1 110.5v2.8M231.1 115.3v2.8"/>
<path d="M238.8 110.5v1.3M238.8 116.8v1.3M240 119.4h1.3M246.4 119.4h1.2M248.9 100.3v1.3h1.3l-1.3 1.3-1.3-1.3h1.3M248.9 110.5v2.8M248.9 115.3v2.8M257.8 110.5v2.8M257.8 115.3v2.8M266.7 110.5v2.8M266.7 115.3v2.8M269.2 109.2h1.1"/>
<path d="M273.3 109.2h1M275.6 105.4l-.8 1.3M275.6 105.4v2.6M275.6 110.5v2.8M275.6 115.3v2.8M275.6 105.4l.8 1.3M285 110h2M46.9 122.7h2.7v10.8l-1.3 1.1-1.4-1.1zM48.3 139.4v4.1h1.2l-1.2 1.3-1.3-1.3h1.3M48.3 134.6v2.8M53.3 122.7h2.6v10.8l-1.3 1.1-1.3-1.1zM54.6 139.4v4.1h1.3l-1.3 1.3-1.3-1.3h1.3"/>
<path d="M54.6 134.6v2.8M61 139.4v4.1h1.2l-1.2 1.3-1.3-1.3h1.3M61 132.1v5.3M61 132.1l-.8 1.3M61 132.1l.7 1.3M67.3 139.4v4.1h1.3l-1.3 1.3-1.3-1.3h1.3M67.3 132.1v5.3M67.3 132.1l-.8 1.3M67.3 132.1l.8 1.3M105.3 125.2h2.7v10.8l-1.3 1.2-1.4-1.2zM106.7 137.2v2.8M111.7 125.2h2.7v10.8l-1.4 1.2-1.3-1.2z"/>
<path d="M113 137.2v2.8M188 129.5v1.3h1.2l-1.2 1.3-1.3-1.3h1.3M188 120.7v2.7M188 125.5v2.8M204.5 129.5v1.3h1.2l-1.2 1.3-1.3-1.3h1.3M204.5 121.9v5.1M222.2 139.7h1.3a.64 .64 0 0 1 .7-.6 .64 .64 0 0 1 .6 .6 .64 .64 0 0 1 .6-.6 .64 .64 0 0 1 .7 .6 .64 .64 0 0 1 .6-.6 .64 .64 0 0 1 .6 .6 .64 .64 0 0 1 .7-.6 .64 .64 0 0 1 .6 .6h1.3M248.9 121.9v1.3h1.3l-1.3 1.3-1.3-1.3h1.3M269.2 139.7h1.1M273.3 139.7h1M275.6 135.9v2.5M275.6 135.9l-.8 1.3"/>
<path d="M275.6 135.9l.8 1.3M106.7 142v4.1h1.2l-1.2 1.2-1.3-1.2h1.3M113 142v4.1h1.3l-1.3 1.2-1.2-1.2h1.2M174 149.9h2.5M174 149.9l1.3 .7M175.3 149.1l-1.3 .8M188 141v2.5M188 151.1v2.8M188 156v2.8M188 141l-.8 1.2M188 141l.7 1.2M189.2 149.9h5.1"/>
<path d="M189.2 144.8h5.1M194.3 142.2h20.3v10.2h-20.3zM204.5 152.4v5.1M214.6 149.9h5.1M214.6 144.8h5.1M231.1 141v2.8M231.1 145.8v2.8M238.8 141v1.2M238.8 147.3v1.3M240 149.9h1.3M246.4 149.9h1.2M248.9 152.4v1.3h1.3l-1.3 1.2-1.3-1.2h1.3"/>
<path d="M248.9 141v2.8M248.9 145.8v2.8M257.8 141v2.8M257.8 145.8v2.8M266.7 141v2.8M266.7 145.8v2.8M275.6 141v2.8M275.6 145.8v2.8M10 160h2M31.7 178.4h.1M31.7 171.5l-.7 1.2M31.7 171.5v2.5"/>
<path d="M31.7 171.5l.8 1.2M41.9 179.1h.1M41.9 172.7l-.8 1.3M41.9 172.7v2.6M41.9 172.7l.8 1.3M48.3 174h2.5M48.3 174l1.2 .8M49.5 173.2l-1.2 .8M62.2 165.1v2.5M62.2 175.3v2.8M62.2 165.1l-.7 1.3M62.2 165.1l.8 1.3"/>
<path d="M63.5 174h5.1M63.5 168.9h5.1M68.6 166.4h20.3v10.1h-20.3zM78.7 176.5v5.1M88.9 174h5.1M88.9 168.9h5.1M96.5 163.8h1.3a.64 .64 0 0 1 .6-.6 .64 .64 0 0 1 .7 .6 .64 .64 0 0 1 .6-.6 .64 .64 0 0 1 .6 .6 .64 .64 0 0 1 .7-.6 .64 .64 0 0 1 .6 .6 .64 .64 0 0 1 .6-.6 .64 .64 0 0 1 .7 .6h1.2M105.4 165.1v2.8M105.4 169.9v2.8M113 165.1v1.3M113 171.5v1.2M114.3 174h1.3"/>
<path d="M120.6 174h1.3M123.2 176.5v1.3h1.3l-1.3 1.3-1.3-1.3h1.3M123.2 165.1v2.8M123.2 169.9v2.8M132.1 165.1v2.8M132.1 169.9v2.8M141 165.1v2.8M141 169.9v2.8M143.5 163.8h1M147.6 163.8h1M149.9 160v2.6M149.9 165.1v2.8"/>
<path d="M149.9 169.9v2.8M149.9 160l-.8 1.3M149.9 160l.7 1.3M177 166h108v32h-108zM186.8 174.6v.1M186.8 173.8v.1M188 160v1.3h1.2l-1.2 1.3-1.3-1.3h1.3M203.5 173.3l-.6-.1-.2 .1v.5l.6 .3 .2 .3-.3 .3-.6-.1M204.5 160v1.3h1.2l-1.2 1.3-1.3-1.3h1.3M285 160h2M60 198v2M62.2 184.2v1.2h1.3l-1.3 1.3-1.2-1.3h1.2"/>
<path d="M62.2 180.1v2.8M78.7 184.2v1.2h1.3l-1.3 1.3-1.2-1.3h1.2M110 198v2M160 198v2M177 194.5h108M177 191.5h108M177 187.5h108M177 181.5h108M182.5 186.3v.1M182.5 185.5v.1M184.7 183.6v.1M184.7 182.8v.1"/>
<path d="M194.1 182.7l-.3 .1M195.7 182.1l-1.3 2M197 191.5v3M200.1 185.4l.4 .1M200.5 186.3l-.4 .1M201.2 185.5l.2-.1 .3 .1 .1 .9M201.2 184.9v1.5M210 198v2M217.7 193.2h1.2M219.5 192.4l.6-.1 .2 .1 .1 .3-.9 1.1h.9M221.1 192.4l.2-.1a.81 .81 0 0 1 .6 .6 .81 .81 0 0 1-.3 .8l-.1 .1a.81 .81 0 0 1-.4-1.4zM260 198v2"/>
<path d="M261 191.5v6.5M271.7 196.6h.9M271.7 195.5l.5-.4v1.5"/>
<circle cx="22.2" cy="34" r=".51"/>
<circle cx="22.2" cy="26.4" r=".51"/>
<circle cx="22.2" cy="24.4" r=".51"/>
<circle cx="22.2" cy="32" r=".51"/>
<circle cx="270.8" cy="78.7" r=".51"/>
<circle cx="272.8" cy="78.7" r=".51"/>
<circle cx="270.8" cy="109.2" r=".51"/>
<circle cx="272.8" cy="109.2" r=".51"/>
<circle cx="270.8" cy="139.7" r=".51"/>
<circle cx="272.8" cy="139.7" r=".51"/>
<circle cx="31.8" cy="178.4" r=".51"/>
<circle cx="41.9" cy="179.1" r=".51"/>
<circle cx="145" cy="163.8" r=".51"/>
<circle cx="147.1" cy="163.8" r=".51"/>
</g>
<g fill="none" stroke="#840000" stroke-width=".51">
<path d="M25.3 36.3h4M25.3 34.8h4M102.1 96h4.1M102.1 94.5h4.1M108.5 96h4M108.5 94.5h4M117.3 96h4.1M117.3 94.5h4.1M123.7 96h4.1M123.7 94.5h4.1M131.3 96h4.1M131.3 94.5h4.1"/>
<path d="M138.9 96h4.1M138.9 94.5h4.1M145.3 96h4.1M145.3 94.5h4.1M185.9 94.7h4.1M185.9 93.2h4.1M229.1 84.6h4.1M229.1 83.1h4.1M246.9 84.6h4.1M246.9 83.1h4.1M255.8 84.6h4M255.8 83.1h4"/>
<path d="M264.7 84.6h4M264.7 83.1h4M273.6 84.6h4M273.6 83.1h4M47.5 101.5v4M49 101.5v4M229.1 115.1h4.1M229.1 113.5h4.1M246.9 115.1h4.1M246.9 113.5h4.1M255.8 115.1h4M255.8 113.5h4"/>
<path d="M264.7 115.1h4M264.7 113.5h4M273.6 115.1h4M273.6 113.5h4M46.2 139.2h4.1M46.2 137.7h4.1M52.6 139.2h4M52.6 137.7h4M58.9 139.2h4.1M58.9 137.7h4.1M65.3 139.2h4M65.3 137.7h4"/>
<path d="M185.9 125.2h4.1M185.9 123.7h4.1M104.6 141.7h4.1M104.6 140.2h4.1M111 141.7h4.1M111 140.2h4.1M185.9 155.7h4.1M185.9 154.2h4.1M229.1 145.5h4.1M229.1 144h4.1M246.9 145.5h4.1M246.9 144h4.1"/>
<path d="M255.8 145.5h4M255.8 144h4M264.7 145.5h4M264.7 144h4M273.6 145.5h4M273.6 144h4M60.2 179.8h4.1M60.2 178.3h4.1M103.4 169.7h4M103.4 168.1h4M121.2 169.7h4M121.2 168.1h4"/>
<path d="M130 169.7h4.1M130 168.1h4.1M138.9 169.7h4.1M138.9 168.1h4.1M147.8 169.7h4.1M147.8 168.1h4.1"/>
</g>
<g fill="none" stroke="#840000" stroke-width=".25">
<path d="M69.8 93.6h5.1v2h-5.1zM71.1 88.3l2.6-1.3v2.5zM71.1 87v2.5M237.7 81.3h2.1v5.1h-2.1zM237.7 91.4h2.1v5.1h-2.1zM240.7 98h5v2.1h-5zM241.3 87.9h5.1v2h-5.1zM237.7 111.8h2.1v5h-2.1zM241.3 118.4h5.1v2h-5.1zM237.7 142.2h2.1v5.1h-2.1zM241.3 148.8h5.1v2.1h-5.1zM112 166.4h2v5.1h-2z"/>
<path d="M115.6 173h5v2h-5z"/>
</g>
<g fill="none" stroke="#006464" stroke-width=".18">
<path d="M23.7 18.6h.8l-.4 .5M24.3 19.1l.2 .2v.3l-.2 .3M108.3 19.9h.6M128.5 19.2h.8l-.4 .5M129.1 19.7l.2 .3v.3l-.2 .2M136.1 19.2h.8l-.4 .5M136.7 19.7l.2 .3v.3l-.2 .2M178 19.9h.8l-.4 .5M195.8 19.9h.8l-.4 .5M23.9 38.4h.6M24.3 38.9l.2 .3v.3l-.2 .2M31.9 32.3h.6"/>
<path d="M54.9 21.2h.7M55 20.2l.3-.3v1.3M108.7 20.4l.3 .2v.3l-.3 .3M125 35.6v.8M127.6 35.6v.8M166.3 23.3h.3l.3 .3-.3 .4M166.3 24h.3M166.6 24l.2 .1 .1 .4-.2 .3h-.4M167.5 24.8h.8M167.5 23.7l.4-.4v1.5M169.9 23.4a.61 .61 0 0 0-.8 0 .61 .61 0 0 0-.2 .8 .57 .57 0 0 0 .3 .6 .57 .57 0 0 0 .7-.1M178.6 20.4l.2 .2v.3l-.2 .3"/>
<path d="M196.4 20.4l.2 .2v.3l-.2 .3M189.8 78.3l-.4 1.3M212 78.4l-.5 1.5M227.8 76.7h.7M228.5 76.1v1.3M277.2 74.5h.7M277.3 73.5l.2-.3v1.3M75.8 85.9h.8M76.4 85.5v.8M79.1 92.8l1.2 .4M105.7 88.5h.7M105.8 87.5l.3-.3v1.3"/>
<path d="M112.1 88.5h.7M112.2 87.5l.2-.3v1.3M121 87.2h.6M121.4 87.7l.3 .2v.3l-.3 .3M127.4 87.2h.6M127.8 87.7l.2 .2v.3l-.2 .3M134.9 87.2h.7l-.4 .5M135.4 87.7l.2 .2v.3l-.2 .3M142.5 87.2h.8l-.5 .5M143 87.7l.3 .2v.3l-.3 .3M148.8 87.2h.8l-.4 .5M149.4 87.7l.2 .2v.3l-.2 .3"/>
<path d="M171 87.1l1.3 .4M237 86.3h.4M237 85.7h.6M271.9 85.7h.6M280.8 85.7h.6M54.7 104.7h.4M54.7 104.1h.6M172.3 117.6l1.3 .4M189.8 108.8l-.4 1.3M212 108.9l-.5 1.5M227.8 107.2h.7M228.5 106.6v1.3"/>
<path d="M237 116.1h.6M237 116.8h.4M252.4 112.3h.7M271.9 116.1h.6M277.2 103.7h.6M277.6 104.2l.3 .2v.3l-.3 .3M280.8 116.1h.6M62.5 130.4h.8l-.5 .5M63 130.9l.3 .2v.3l-.3 .2M68.8 130.4h.8l-.4 .5M69.4 130.9l.2 .2v.3l-.2 .2M70.8 136.5h.7"/>
<path d="M189.8 139.3l-.4 1.2M212 139.4l-.5 1.5M227.8 137.7h.7M228.5 137.1v1.3M277.1 134.2h.8l-.4 .5M277.6 134.7l.3 .2v.3l-.3 .3M152.5 157.5h.6M152.6 158h.3l.2 .2v.4l-.5 .1M172.3 148l1.3 .5M237 147.2h.4M237 146.6h.6M271.9 146.6h.6"/>
<path d="M280.8 146.6h.6M33.3 171h.7M33.4 170l.3-.3v1.3M44.5 170.2h.6M44.6 170.7h.4l.2 .2-.1 .5h-.5M46.6 172.2l1.2 .4M64 163.4l-.4 1.3M86.3 163.5l-.6 1.5M102.1 161.8h.7M102.8 161.2v1.3M111.2 170.8h.6M111.2 171.4h.5"/>
<path d="M146.2 170.8h.6M155.1 170.8h.6M29.5 180.2h.7"/>
</g>
<path d="M70.7 30.1v.7M73.2 30.1v.7M126.6 30.2v.8M125.3 59.5v.7M127.9 59.4v.7M130.4 59.5v.7M132.9 59.3v.7M135.5 59.4v.7M272.6 59.3v.8" fill="none" stroke="#a90000" stroke-width=".18"/>
<path d="M244.7 78.2h.9" fill="none" stroke="#0f0f0f" stroke-width=".18"/>
<g fill="none" stroke="#0000c2" stroke-width=".18">
<path d="M213 26.6v1.2l-.2 .2M213 26.6h-.5l-.3 .3v.4l.2 .2h.6M220.9 29v1.3l-.3 .2h-.4M220.9 29.1l-.5-.1-.3 .3v.4l.2 .3h.6M226 26.6h-.3l-.3 .2 .1 .2 .5 .1v.4h-.6M226.7 27.4v.2M226.7 26.6v.2M240.5 26.6l.2 .3-.8 .2M240.6 27.5l-.1 .1M245.4 29l.4 .1M245.8 29v1.3l-.1 .2h-.4M245.8 30h-.4"/>
<path d="M267.2 29.5l.7-.1-.1-.3-.4-.1-.2 .2v.8h.6M270.1 28.5h-.4v1.5h.4M31.1 65.8h.6M31.4 65.3v1.3l.3 .3M63.8 72.5l.4 1M64.2 73.5l-.2 .3M64.5 72.5l-.3 1M65.6 70.4l.5 .6M66.1 70l-.6 .6M91.7 70v1M92.1 70l-.3 .1-.1 .2M99 75.8v.1"/>
<path d="M121.9 78.1l.1 .9M166.2 73.2h.6M166.2 72.4l.4-.1 .2 .3-.7 .2M176.4 73.2v.1M176.4 72.4v.1M184.9 74.2l-.1 .1a1.03 1.03 0 0 0 0 1.5l.5-.2v-.5l-.3-.3h-.2l-.3 .3M185.8 74.2l.5 1.6 .5-1.6M238.1 73a.83 .83 0 0 1 .6 .6 .83 .83 0 0 1-.3 .8l-.3 .1M239.3 74.3v.2M240.7 73a.6 .6 0 0 0-.8 .6v.6l.2 .2 .4 .1 .2-.2 .1-.5-.1-.2-.5-.1-.3 .3M241.3 73l.5 1.5 .5-1.5M97.6 99.7l-.4-.1-.2 .2 .1 .2 .5 .2v.3h-.6"/>
<path d="M115.9 80.5h.4l.1 .3-.7 .2M116.3 81.4l-.4 .1M165.1 83.6l-.3 1M173.1 83.1l-.5 1.5M173.3 80.7l-.5 1.5M31.2 113.1h.5M31.2 112.3v1.6M51.4 110.6h.5M51.4 109.9h.8M52.7 110.6h1.2M52.7 111h1.2M54.8 112.3v1.3l.3 .3"/>
<path d="M55.3 109.9a.6 .6 0 0 0-.8 .6v.6l.2 .2 .4 .1 .2-.1 .1-.6-.1-.2h-.5l-.3 .2M56.1 110.5l.4-.1 .3 .3v.4l-.1 .2h-.6M56.1 110.4v1.5M57.4 110.6h.6M58.2 109.9h-.8v1.5M67 104.1v.3M67.3 113.1h.6M67.6 104.1v.3M67.9 112.3h-.6v1.6M98.9 102h.2l.2 .3v.8M113.4 111.9v.1M113.4 111.1v.1"/>
<path d="M115.8 120l-.1 .2M121.1 108.6l.4 1M121.5 109.6l-.2 .3M121.8 108.6l-.3 1M125.1 113.9l.4 .1 .2 .2-.1 .2-.4 .1M125.1 113.5h.5M133.6 108.6h.6M133.8 108.1v1.3l.4 .2M140.3 113.6l.4-.1 .2 .2M140.3 113.5v1M140.9 113.7l.2-.2h.4l.1 1M140.9 113.7v.8"/>
<path d="M142.8 113.5h-.4l-.2 .2 .1 .2 .5 .2v.3h-.6M145.8 118.7l-.3 .2M225.4 104.1h.1a.83 .83 0 0 1 .6 .6 .83 .83 0 0 1-.3 .8h-.4M226.7 105.5v.1M228.1 104.1a.6 .6 0 0 0-.8 .6v.6l.2 .2 .4 .1 .2-.1 .1-.6-.1-.2h-.5l-.3 .2M228.6 104.1l.6 1.5 .5-1.5M108.3 120h.8M120.1 121.5l.2 .3-.7 .2M120.2 122.4l-.1 .1M134.5 121l.5 1.5 .5-1.5M145.5 120h.9M147.5 122l.3 .1 .1 .2-.2 .2h-.3"/>
<path d="M147.5 121.5h.3M238.7 134l.2-.1a.83 .83 0 0 1 .6 .7 .83 .83 0 0 1-.3 .8h-.5M240 135.3v.1M241.4 133.9a.6 .6 0 0 0-.7 .7v.6l.1 .2h.5l.2-.1v-.5l-.1-.2-.4-.1-.3 .3M242 133.9l.5 1.5 .5-1.5M48.8 148.4h.1M50 148.5l-.4-.1-.2 .2v.2l.6 .2v.3h-.6M74.3 148.4v1M74.7 148.4l-.3 .1-.1 .2M114.3 158.1a.83 .83 0 0 1 .6 .6 .83 .83 0 0 1-.3 .8l-.3 .1M115.5 159.4v.2M116.8 158.1a.6 .6 0 0 0-.7 .6v.6l.2 .2 .4 .1 .2-.2 .1-.5-.2-.2-.4-.1-.3 .3"/>
<path d="M117.4 158.1l.5 1.5 .5-1.5M220.8 159.6v.1M220.8 158.8v.2M230 159.7l.5-1.5 .5 1.5M230.2 159.3h.7M247.9 158.7v1M247.9 158.9l.5-.2 .2 .3M248.6 159l.2-.3 .4 .1v.9M248.6 159v.7M264.3 158.7h.2l.2 .3v.7M265.4 158.9l.5-.2 .2 .3M265.4 158.7v1"/>
<path d="M266.1 159l.2-.3 .4 .1v.9M266.1 159v.7M218 161.2l.2 .2v.8M218 164.1l.4 .1 .1 .2-.3 .3h-.2M218 163.6l.4 .1M218.2 162.1l-.1 .1M218.2 161.5l-.1 .1M222.4 177.5l.2 .2-.2 .3M222.4 177h.1M225.5 174.5l.2 .2v.8M225.8 167.2v1.2l-.1 .2M225.8 167.2h-.4l-.3 .3v.4l.1 .2h.6"/>
<path d="M226.4 174v.2M226.4 174.5v1M234.2 169.6h.6M234.5 178l.5-1.5 .5 1.5M234.5 172.1h.5M234.5 170.6h.3M234.6 177.6h.7M234.7 171.6v1.3l.3 .2M235.8 174l.3 .3-.1 .4-.8 .8h.9M235.8 169.7l-.3-.1-.3 .2 .1 .2 .5 .2v.4h-.6M236 172.1h-.3l-.2 .2v.2l.5 .1v.4h-.5M237.4 167.2h.2"/>
<path d="M237.6 163.4l-.1 .4-.9 .9h1M238.2 164.7v-1.6l.5 1.1 .5-1.1v1.6M238.6 167.2h-.4l-.2 .2 .1 .2 .5 .1v.4h-.6M244.1 174.4v1.1M244.3 160.7v1.5M244.9 160.7l.3 .3-.1 .3-.2 .2h-.6M246 160.7l-.2 .1M246.3 160.7l.3 .3v.3l-.9 .9h.9M247.4 162.1l-.2 .3M248.3 172.4l.2 .2-.2 .4M248.3 171.7v.4M252.5 169.1l-.5 1.5"/>
<path d="M253.4 166.7h.7M253.5 167.2h.4l.3 .3-.2 .6-.5 .1M266.9 174.5l.4 .1 .1 .3-.7 .1M267.3 175.5h-.4M268.3 174.4v.7l-.3 .9M271.7 161.4h1.1M271.7 161.8h1.1M273.5 160.7v1.5M274.1 160.7l.3 .3-.1 .3-.2 .2h-.6M275.2 160.7l-.2 .1M275.6 160.7l.3 .3-.1 .3-.9 .9h1M277.5 171.3a1.75 1.75 0 0 1 0 2.4"/>
</g>
<g fill="none" stroke="#009600" stroke-width=".18">
<path d="M22.2 29.2h5.1M22.2 27.9v2.6M27.3 26.7v5.1M50.8 29.2v-2.5h48.3v2.5M53.3 24.1v5.1M55.9 26.7v2.5M58.4 26.7v2.5M61 26.7v2.5M63.5 26.7v2.5M66 26.7v2.5M68.6 26.7v2.5M71.1 26.7v2.5"/>
<path d="M73.7 26.7v2.5M76.2 26.7v2.5M78.7 26.7v2.5M81.3 26.7v2.5M83.8 26.7v2.5M86.4 26.7v2.5M88.9 26.7v2.5M91.4 26.7v2.5M94 26.7v2.5M96.5 26.7v2.5M104.1 29.2v-2.5h7.7v2.5M106.7 24.1v5.1"/>
<path d="M109.2 26.7v2.5M119.4 26.7h-2.6v2.5M119.4 24.1v5.1M127 26.7h-2.5v2.5M127 23.5v5.7M132.1 29.2v-2.5h15.2v2.5M134.6 23.5v5.7M137.2 26.7v2.5M142.2 26.7v2.5M144.8 26.7v2.5M174 29.2v-2.5h5.1v2.5M176.5 24.1v5.1"/>
<path d="M184.1 29.2v-2.5h5.1v2.5M186.7 24.1v5.1M194.3 26.7h2.5v2.5M194.3 24.1v5.1M59.7 63.5v2.5h213.3v-2.5M62.2 63.5v2.5M64.8 63.5v2.5M67.3 63.5v2.5M69.8 63.5v2.5M72.4 63.5v2.5M74.9 63.5v2.5M77.5 63.5v2.5"/>
<path d="M80 63.5v2.5M82.5 63.5v2.5M85.1 63.5v2.5M87.6 63.5v2.5M90.2 63.5v2.5M92.7 63.5v2.5M95.2 63.5v2.5M97.8 63.5v2.5M100.3 63.5v2.5M102.9 63.5v2.5M105.4 63.5v2.5M107.9 63.5v2.5"/>
<path d="M110.5 63.5v2.5M113 63.5v2.5M115.6 63.5v2.5M118.1 63.5v2.5M120.6 63.5v2.5M123.2 63.5v2.5M125.7 63.5v5.1M128.3 63.5v2.5M130.8 63.5v2.5M133.3 63.5v2.5M135.9 63.5v2.5M138.4 63.5v2.5"/>
<path d="M141 63.5v2.5M143.5 63.5v2.5M146 63.5v2.5M148.6 63.5v2.5M151.1 63.5v2.5M153.7 63.5v2.5M156.2 63.5v2.5M158.7 63.5v2.5M161.3 63.5v2.5M163.8 63.5v2.5M166.4 63.5v2.5M168.9 63.5v2.5"/>
<path d="M171.4 63.5v2.5M174 63.5v2.5M176.5 63.5v2.5M179.1 63.5v2.5M181.6 63.5v2.5M184.1 63.5v2.5M186.7 63.5v2.5M189.2 63.5v2.5M191.8 63.5v2.5M194.3 63.5v2.5M196.8 63.5v2.5M199.4 63.5v2.5"/>
<path d="M201.9 63.5v2.5M204.5 63.5v2.5M207 63.5v2.5M209.5 63.5v2.5M212.1 63.5v2.5M214.6 63.5v2.5M217.2 63.5v2.5M219.7 63.5v2.5M222.2 78.7h-1.2v5.1h-1.3M222.2 63.5v2.5M224.8 63.5v2.5M227.3 63.5v2.5"/>
<path d="M229.9 78.7h39.3M229.9 63.5v2.5M231.1 78.7v1.3M232.4 63.5v2.5M234.9 63.5v2.5M237.5 63.5v2.5M238.8 78.7v1.3M240 63.5v2.5M242.6 63.5v2.5M245.1 63.5v2.5M247.6 63.5v2.5M248.9 78.7v1.3"/>
<path d="M250.2 63.5v2.5M252.7 63.5v2.5M255.3 63.5v2.5M257.8 63.5v2.5M257.8 78.7v1.3M260.3 63.5v2.5M262.9 63.5v2.5M265.4 63.5v2.5M266.7 78.7v1.3M268 63.5v2.5M270.5 63.5v2.5M274.3 78.7h1.3"/>
<path d="M275.6 77.5v2.5M66 94.6h2.6M68.6 99.7h-14v3.8h-2.5M68.6 88.3h-2.6v11.4M175.3 88.9h13.9M188 82.6v7.6M188 97.8v1.3M188 83.8h1.2M204.5 96.5v2.6M219.7 88.9h20.3M231.1 87.6v1.3M238.8 87.6v2.6"/>
<path d="M238.8 97.8v1.3h.6M247 99.1h1.9M248.9 87.6v12.7M257.8 87.6v1.3M266.7 87.6v1.3M275.6 87.6v1.3h-28M43.2 103.5h1.2M176.5 119.4h12.7M188 113v7.7M188 114.3h1.2M219.7 119.4h20.3M222.2 109.2h-1.2v5.1h-1.3"/>
<path d="M229.9 109.2h39.3M231.1 109.2v1.3M231.1 118.1v1.3M238.8 109.2v1.3M238.8 118.1v1.3M248.9 109.2v1.3M248.9 118.1v3.8M257.8 109.2v1.3M257.8 118.1v1.3M266.7 109.2v1.3M266.7 118.1v1.3M274.3 109.2h1.3v1.3"/>
<path d="M275.6 118.1v1.3h-28M188 128.3v1.2M204.5 127v2.5M222.2 139.7h-1.2v5.1h-1.3M229.9 139.7h39.3M231.1 139.7v1.3M238.8 139.7v1.3M248.9 139.7v1.3M257.8 139.7v1.3M266.7 139.7v1.3M274.3 139.7h1.3v1.3M176.5 149.9h12.7"/>
<path d="M188 143.5v7.6M188 158.8v1.2M188 144.8h1.2M204.5 157.5v2.5M219.7 149.9h20.3M231.1 148.6v1.3M238.8 148.6v1.3M248.9 148.6v3.8M257.8 148.6v1.3M266.7 148.6v1.3M275.6 148.6v1.3h-28M31.7 174v4.4"/>
<path d="M41.9 175.3v3.8M50.8 174h12.7M62.2 167.6v7.7M62.2 168.9h1.3M94 174h20.3M96.5 163.8h-1.3v5.1h-1.2M104.1 163.8h39.4M105.4 163.8v1.3M105.4 172.7v1.3M113 163.8v1.3M113 172.7v1.3M123.2 163.8v1.3"/>
<path d="M123.2 172.7v3.8M132.1 163.8v1.3M132.1 172.7v1.3M141 163.8v1.3M141 172.7v1.3M148.6 163.8h1.3v1.3M149.9 172.7v1.3h-28M62.2 182.9v1.3M78.7 181.6v2.6"/>
</g>
<g fill="#009600" stroke="#009600" stroke-width=".18">
<circle cx="132.1" cy="163.8" r=".46"/>
<circle cx="123.2" cy="163.8" r=".46"/>
<circle cx="105.4" cy="163.8" r=".46"/>
<circle cx="66" cy="94.6" r=".46"/>
<circle cx="72.4" cy="66" r=".46"/>
<circle cx="74.9" cy="66" r=".46"/>
<circle cx="66" cy="99.7" r=".46"/>
<circle cx="85.1" cy="66" r=".46"/>
<circle cx="82.5" cy="66" r=".46"/>
<circle cx="67.3" cy="66" r=".46"/>
<circle cx="69.8" cy="66" r=".46"/>
<circle cx="87.6" cy="66" r=".46"/>
<circle cx="90.2" cy="66" r=".46"/>
<circle cx="92.7" cy="66" r=".46"/>
<circle cx="64.8" cy="66" r=".46"/>
<circle cx="62.2" cy="66" r=".46"/>
<circle cx="80" cy="66" r=".46"/>
<circle cx="77.5" cy="66" r=".46"/>
<circle cx="63.5" cy="26.7" r=".46"/>
<circle cx="68.6" cy="26.7" r=".46"/>
<circle cx="61" cy="26.7" r=".46"/>
<circle cx="66" cy="26.7" r=".46"/>
<circle cx="22.2" cy="29.2" r=".46"/>
<circle cx="53.3" cy="26.7" r=".46"/>
<circle cx="27.3" cy="29.2" r=".46"/>
<circle cx="55.9" cy="26.7" r=".46"/>
<circle cx="58.4" cy="26.7" r=".46"/>
<circle cx="113" cy="174" r=".46"/>
<circle cx="105.4" cy="174" r=".46"/>
<circle cx="141" cy="163.8" r=".46"/>
<circle cx="141" cy="174" r=".46"/>
<circle cx="123.2" cy="174" r=".46"/>
<circle cx="132.1" cy="174" r=".46"/>
<circle cx="113" cy="163.8" r=".46"/>
<circle cx="148.6" cy="66" r=".46"/>
<circle cx="151.1" cy="66" r=".46"/>
<circle cx="146" cy="66" r=".46"/>
<circle cx="62.2" cy="168.9" r=".46"/>
<circle cx="232.4" cy="66" r=".46"/>
<circle cx="234.9" cy="66" r=".46"/>
<circle cx="237.5" cy="66" r=".46"/>
<circle cx="248.9" cy="78.7" r=".46"/>
<circle cx="240" cy="66" r=".46"/>
<circle cx="242.6" cy="66" r=".46"/>
<circle cx="238.8" cy="78.7" r=".46"/>
<circle cx="224.8" cy="66" r=".46"/>
<circle cx="222.2" cy="66" r=".46"/>
<circle cx="219.7" cy="66" r=".46"/>
<circle cx="247.6" cy="66" r=".46"/>
<circle cx="245.1" cy="66" r=".46"/>
<circle cx="252.7" cy="66" r=".46"/>
<circle cx="250.2" cy="66" r=".46"/>
<circle cx="255.3" cy="66" r=".46"/>
<circle cx="231.1" cy="88.9" r=".46"/>
<circle cx="238.8" cy="88.9" r=".46"/>
<circle cx="231.1" cy="78.7" r=".46"/>
<circle cx="229.9" cy="66" r=".46"/>
<circle cx="227.3" cy="66" r=".46"/>
<circle cx="248.9" cy="88.9" r=".46"/>
<circle cx="260.3" cy="66" r=".46"/>
<circle cx="262.9" cy="66" r=".46"/>
<circle cx="265.4" cy="66" r=".46"/>
<circle cx="268" cy="66" r=".46"/>
<circle cx="257.8" cy="66" r=".46"/>
<circle cx="270.5" cy="66" r=".46"/>
<circle cx="209.5" cy="66" r=".46"/>
<circle cx="212.1" cy="66" r=".46"/>
<circle cx="201.9" cy="66" r=".46"/>
<circle cx="207" cy="66" r=".46"/>
<circle cx="204.5" cy="66" r=".46"/>
<circle cx="199.4" cy="66" r=".46"/>
<circle cx="217.2" cy="66" r=".46"/>
<circle cx="214.6" cy="66" r=".46"/>
<circle cx="275.6" cy="78.7" r=".46"/>
<circle cx="231.1" cy="109.2" r=".46"/>
<circle cx="257.8" cy="88.9" r=".46"/>
<circle cx="266.7" cy="88.9" r=".46"/>
<circle cx="257.8" cy="78.7" r=".46"/>
<circle cx="248.9" cy="99.1" r=".46"/>
<circle cx="266.7" cy="78.7" r=".46"/>
<circle cx="196.8" cy="66" r=".46"/>
<circle cx="189.2" cy="66" r=".46"/>
<circle cx="194.3" cy="66" r=".46"/>
<circle cx="188" cy="83.8" r=".46"/>
<circle cx="107.9" cy="66" r=".46"/>
<circle cx="110.5" cy="66" r=".46"/>
<circle cx="105.4" cy="66" r=".46"/>
<circle cx="95.2" cy="66" r=".46"/>
<circle cx="97.8" cy="66" r=".46"/>
<circle cx="113" cy="66" r=".46"/>
<circle cx="115.6" cy="66" r=".46"/>
<circle cx="102.9" cy="66" r=".46"/>
<circle cx="100.3" cy="66" r=".46"/>
<circle cx="94" cy="26.7" r=".46"/>
<circle cx="96.5" cy="26.7" r=".46"/>
<circle cx="81.3" cy="26.7" r=".46"/>
<circle cx="83.8" cy="26.7" r=".46"/>
<circle cx="86.4" cy="26.7" r=".46"/>
<circle cx="88.9" cy="26.7" r=".46"/>
<circle cx="71.1" cy="26.7" r=".46"/>
<circle cx="73.7" cy="26.7" r=".46"/>
<circle cx="76.2" cy="26.7" r=".46"/>
<circle cx="78.7" cy="26.7" r=".46"/>
<circle cx="91.4" cy="26.7" r=".46"/>
<circle cx="109.2" cy="26.7" r=".46"/>
<circle cx="106.7" cy="26.7" r=".46"/>
<circle cx="163.8" cy="66" r=".46"/>
<circle cx="161.3" cy="66" r=".46"/>
<circle cx="181.6" cy="66" r=".46"/>
<circle cx="179.1" cy="66" r=".46"/>
<circle cx="176.5" cy="66" r=".46"/>
<circle cx="141" cy="66" r=".46"/>
<circle cx="143.5" cy="66" r=".46"/>
<circle cx="168.9" cy="66" r=".46"/>
<circle cx="166.4" cy="66" r=".46"/>
<circle cx="156.2" cy="66" r=".46"/>
<circle cx="153.7" cy="66" r=".46"/>
<circle cx="158.7" cy="66" r=".46"/>
<circle cx="171.4" cy="66" r=".46"/>
<circle cx="174" cy="66" r=".46"/>
<circle cx="184.1" cy="66" r=".46"/>
<circle cx="120.6" cy="66" r=".46"/>
<circle cx="118.1" cy="66" r=".46"/>
<circle cx="135.9" cy="66" r=".46"/>
<circle cx="138.4" cy="66" r=".46"/>
<circle cx="125.7" cy="66" r=".46"/>
<circle cx="128.3" cy="66" r=".46"/>
<circle cx="133.3" cy="66" r=".46"/>
<circle cx="130.8" cy="66" r=".46"/>
<circle cx="123.2" cy="66" r=".46"/>
<circle cx="142.2" cy="26.7" r=".46"/>
<circle cx="144.8" cy="26.7" r=".46"/>
<circle cx="186.7" cy="66" r=".46"/>
<circle cx="191.8" cy="66" r=".46"/>
<circle cx="186.7" cy="26.7" r=".46"/>
<circle cx="194.3" cy="26.7" r=".46"/>
<circle cx="176.5" cy="26.7" r=".46"/>
<circle cx="137.2" cy="26.7" r=".46"/>
<circle cx="134.6" cy="26.7" r=".46"/>
<circle cx="127" cy="26.7" r=".46"/>
<circle cx="119.4" cy="26.7" r=".46"/>
<circle cx="188" cy="144.8" r=".46"/>
<circle cx="188" cy="114.3" r=".46"/>
<circle cx="257.8" cy="109.2" r=".46"/>
<circle cx="248.9" cy="109.2" r=".46"/>
<circle cx="248.9" cy="119.4" r=".46"/>
<circle cx="257.8" cy="119.4" r=".46"/>
<circle cx="266.7" cy="109.2" r=".46"/>
<circle cx="266.7" cy="119.4" r=".46"/>
<circle cx="266.7" cy="139.7" r=".46"/>
<circle cx="238.8" cy="109.2" r=".46"/>
<circle cx="238.8" cy="119.4" r=".46"/>
<circle cx="266.7" cy="149.9" r=".46"/>
<circle cx="231.1" cy="139.7" r=".46"/>
<circle cx="231.1" cy="149.9" r=".46"/>
<circle cx="238.8" cy="149.9" r=".46"/>
<circle cx="238.8" cy="139.7" r=".46"/>
<circle cx="257.8" cy="149.9" r=".46"/>
<circle cx="248.9" cy="149.9" r=".46"/>
<circle cx="257.8" cy="139.7" r=".46"/>
<circle cx="248.9" cy="139.7" r=".46"/>
<circle cx="231.1" cy="119.4" r=".46"/>
</g>
<use href="#words"/>
</svg>
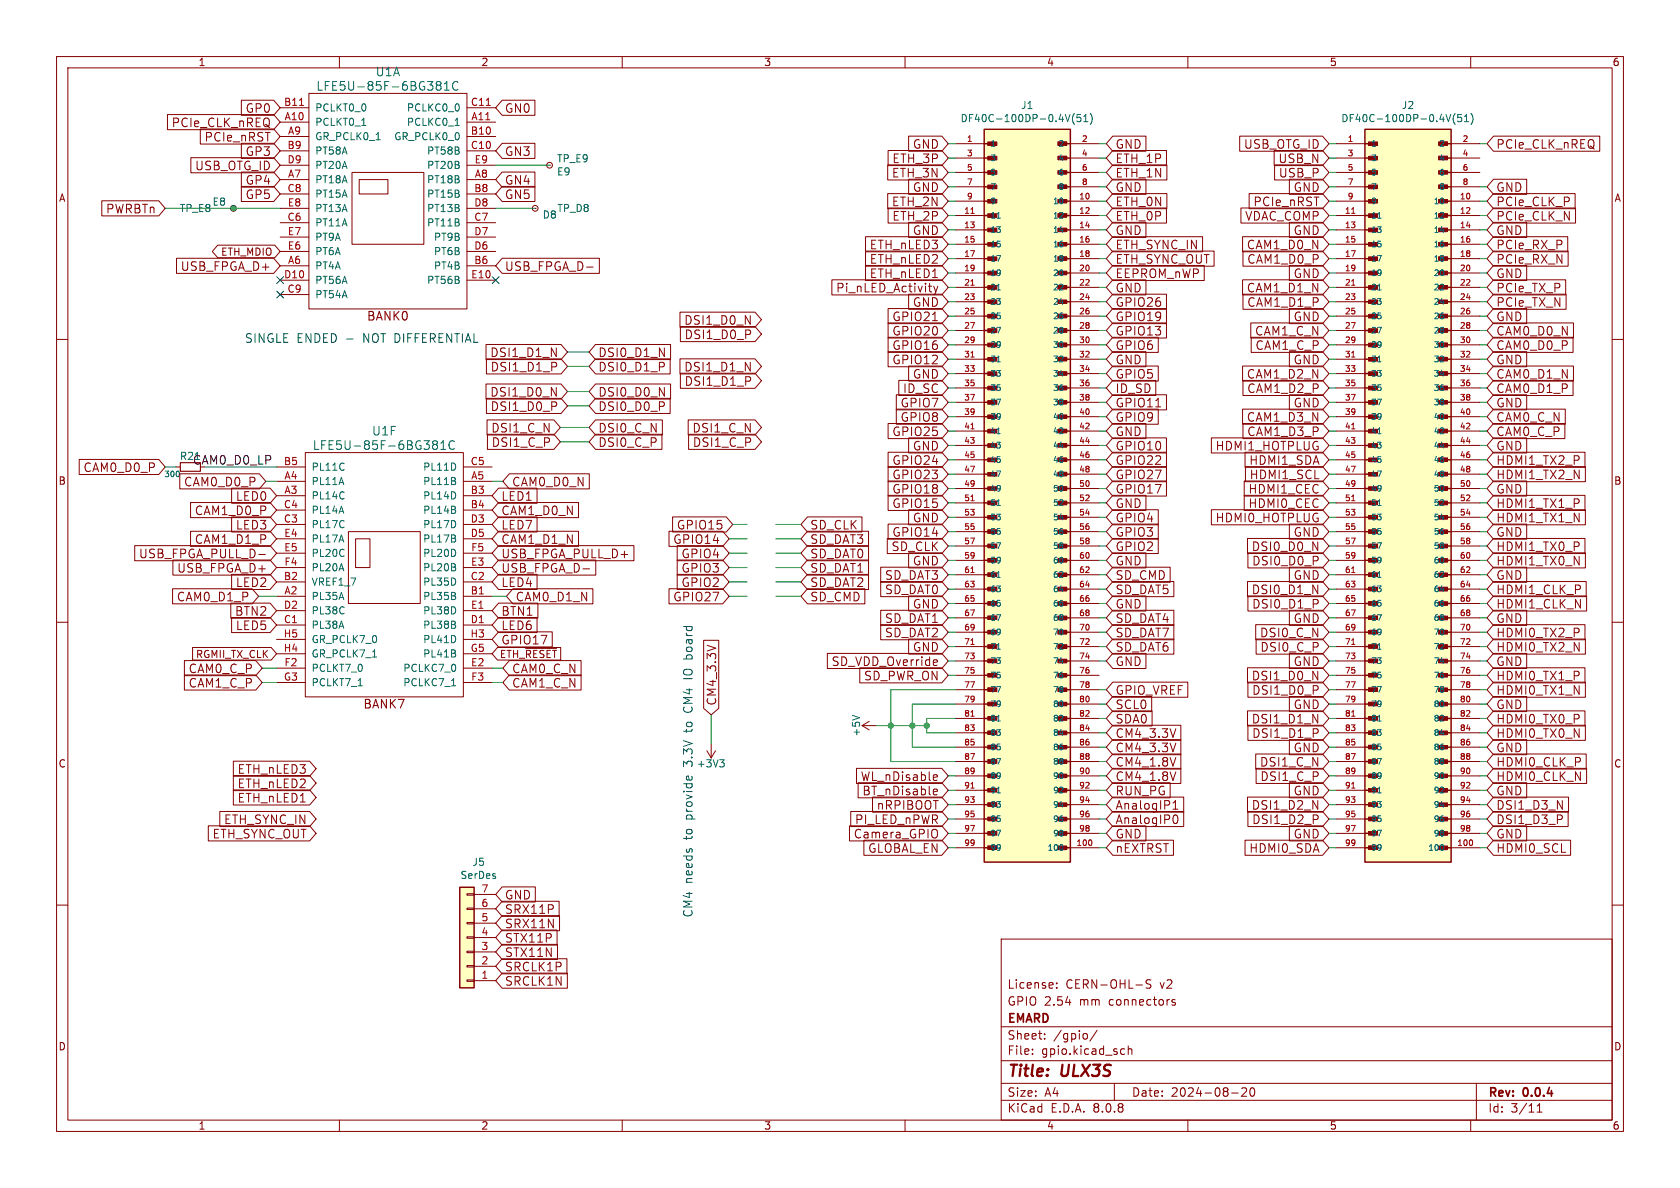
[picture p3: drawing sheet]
<svg xmlns="http://www.w3.org/2000/svg" width="297mm" height="210mm" viewBox="0 0 297 210" stroke-linecap="round" stroke-linejoin="round" font-family="sans-serif">
<defs><g id="words">
<g font-size="2.8" fill="#840000">
<text x="178" y="190.9">Title:</text>
<text x="187.7" y="190.9">ULX3S</text>
</g>
<g font-size="2.1" fill="#006464">
<text x="55.8" y="16.2">LFE5U-85F-6BG381C</text>
<text x="66.3" y="13.7">U1A</text>
<text x="65.7" y="77.2">U1F</text>
<text x="55.2" y="79.7">LFE5U-85F-6BG381C</text>
</g>
<g font-size="2.1" fill="#840000">
<text x="30.3" y="22.7">PCIe_CLK_nREQ</text>
<text x="43.4" y="20.1">GP0</text>
<text x="89.2" y="20.1">GN0</text>
<text x="36.1" y="25.2">PCIe_nRST</text>
<text x="43.4" y="27.8">GP3</text>
<text x="89.2" y="27.8">GN3</text>
<text x="157.7" y="29">ETH_3P</text>
<text x="161.3" y="26.5">GND</text>
<text x="197.1" y="29">ETH_1P</text>
<text x="197.1" y="26.5">GND</text>
<text x="219.8" y="26.5">USB_OTG_ID</text>
<text x="225.9" y="29">USB_N</text>
<text x="264.4" y="26.5">PCIe_CLK_nREQ</text>
<text x="34.4" y="30.3">USB_OTG_ID</text>
<text x="43.4" y="32.8">GP4</text>
<text x="43.4" y="35.4">GP5</text>
<text x="89.2" y="35.4">GN5</text>
<text x="89.2" y="32.8">GN4</text>
<text x="157.6" y="31.6">ETH_3N</text>
<text x="161.3" y="34.1">GND</text>
<text x="197.1" y="34.1">GND</text>
<text x="197.1" y="31.6">ETH_1N</text>
<text x="226" y="31.6">USB_P</text>
<text x="228.6" y="34.1">GND</text>
<text x="264.4" y="34.1">GND</text>
<text x="18.7" y="37.9">PWRBTn</text>
<text x="157.6" y="36.7">ETH_2N</text>
<text x="157.7" y="39.2">ETH_2P</text>
<text x="161.3" y="41.7">GND</text>
<text x="197.1" y="36.7">ETH_0N</text>
<text x="197.1" y="39.2">ETH_0P</text>
<text x="197.1" y="41.7">GND</text>
<text x="220.1" y="39.2">VDAC_COMP</text>
<text x="221.5" y="36.7">PCIe_nRST</text>
<text x="228.6" y="41.7">GND</text>
<text x="264.4" y="39.2">PCIe_CLK_N</text>
<text x="264.4" y="41.7">GND</text>
<text x="264.4" y="36.7">PCIe_CLK_P</text>
<text x="153.7" y="46.8">ETH_nLED2</text>
<text x="153.7" y="44.3">ETH_nLED3</text>
<text x="197.1" y="44.3">ETH_SYNC_IN</text>
<text x="197.1" y="46.8">ETH_SYNC_OUT</text>
<text x="220.4" y="44.3">CAM1_D0_N</text>
<text x="220.4" y="46.8">CAM1_D0_P</text>
<text x="264.4" y="44.3">PCIe_RX_P</text>
<text x="264.4" y="46.8">PCIe_RX_N</text>
<text x="31.9" y="48.1">USB_FPGA_D+</text>
<text x="89.2" y="48.1">USB_FPGA_D-</text>
<text x="147.7" y="51.9">Pi_nLED_Activity</text>
<text x="153.7" y="49.4">ETH_nLED1</text>
<text x="197.1" y="51.9">GND</text>
<text x="197.1" y="49.4">EEPROM_nWP</text>
<text x="220.4" y="51.9">CAM1_D1_N</text>
<text x="228.6" y="49.4">GND</text>
<text x="264.4" y="49.4">GND</text>
<text x="264.4" y="51.9">PCIe_TX_P</text>
<text x="64.7" y="56.9">BANK0</text>
<text x="120.9" y="57.6">DSI1_D0_N</text>
<text x="157.7" y="57">GPIO21</text>
<text x="157.7" y="59.5">GPIO20</text>
<text x="161.3" y="54.4">GND</text>
<text x="197.1" y="57">GPIO19</text>
<text x="197.1" y="54.4">GPIO26</text>
<text x="197.1" y="59.5">GPIO13</text>
<text x="220.4" y="54.4">CAM1_D1_P</text>
<text x="221.8" y="59.5">CAM1_C_N</text>
<text x="228.6" y="57">GND</text>
<text x="264.4" y="59.5">CAM0_D0_N</text>
<text x="264.4" y="54.4">PCIe_TX_N</text>
<text x="264.4" y="57">GND</text>
<text x="86.6" y="63.3">DSI1_D1_N</text>
<text x="86.7" y="65.9">DSI1_D1_P</text>
<text x="105.7" y="63.3">DSI0_D1_N</text>
<text x="105.7" y="65.9">DSI0_D1_P</text>
<text x="120.9" y="65.9">DSI1_D1_N</text>
<text x="121" y="60.2">DSI1_D0_P</text>
<text x="157.7" y="64.6">GPIO12</text>
<text x="157.7" y="62.1">GPIO16</text>
<text x="197.1" y="62.1">GPIO6</text>
<text x="197.1" y="64.6">GND</text>
<text x="221.9" y="62.1">CAM1_C_P</text>
<text x="228.6" y="64.6">GND</text>
<text x="264.4" y="64.6">GND</text>
<text x="264.4" y="62.1">CAM0_D0_P</text>
<text x="86.6" y="70.3">DSI1_D0_N</text>
<text x="105.7" y="70.3">DSI0_D0_N</text>
<text x="121" y="68.4">DSI1_D1_P</text>
<text x="159.6" y="69.7">ID_SC</text>
<text x="161.3" y="67.1">GND</text>
<text x="197.1" y="67.1">GPIO5</text>
<text x="197.1" y="69.7">ID_SD</text>
<text x="220.4" y="67.1">CAM1_D2_N</text>
<text x="220.4" y="69.7">CAM1_D2_P</text>
<text x="264.4" y="67.1">CAM0_D1_N</text>
<text x="264.4" y="69.7">CAM0_D1_P</text>
<text x="86.7" y="72.9">DSI1_D0_P</text>
<text x="86.8" y="76.7">DSI1_C_N</text>
<text x="105.7" y="72.9">DSI0_D0_P</text>
<text x="105.7" y="76.7">DSI0_C_N</text>
<text x="122.3" y="76.7">DSI1_C_N</text>
<text x="157.7" y="77.3">GPIO25</text>
<text x="159.1" y="72.2">GPIO7</text>
<text x="159.1" y="74.8">GPIO8</text>
<text x="197.1" y="77.3">GND</text>
<text x="197.1" y="74.8">GPIO9</text>
<text x="197.1" y="72.2">GPIO11</text>
<text x="220.4" y="74.8">CAM1_D3_N</text>
<text x="220.4" y="77.3">CAM1_D3_P</text>
<text x="228.6" y="72.2">GND</text>
<text x="264.4" y="77.3">CAM0_C_P</text>
<text x="264.4" y="74.8">CAM0_C_N</text>
<text x="264.4" y="72.2">GND</text>
<text x="14.7" y="83.6">CAM0_D0_P</text>
<text x="86.9" y="79.2">DSI1_C_P</text>
<text x="105.7" y="79.2">DSI0_C_P</text>
<text x="122.4" y="79.2">DSI1_C_P</text>
<text x="157.7" y="82.4">GPIO24</text>
<text x="161.3" y="79.8">GND</text>
<text x="197.1" y="82.4">GPIO22</text>
<text x="197.1" y="79.8">GPIO10</text>
<text x="214.8" y="79.8">HDMI1_HOTPLUG</text>
<text x="220.8" y="82.4">HDMI1_SDA</text>
<text x="264.4" y="79.8">GND</text>
<text x="264.4" y="82.4">HDMI1_TX2_P</text>
<text x="32.5" y="86.2">CAM0_D0_P</text>
<text x="41.6" y="88.7">LED0</text>
<text x="88.5" y="88.7">LED1</text>
<text x="90.4" y="86.2">CAM0_D0_N</text>
<text x="157.7" y="84.9">GPIO23</text>
<text x="157.7" y="87.5">GPIO18</text>
<text x="157.7" y="90">GPIO15</text>
<text x="197.1" y="90">GND</text>
<text x="197.1" y="87.5">GPIO17</text>
<text x="197.1" y="84.9">GPIO27</text>
<text x="220.6" y="90">HDMI0_CEC</text>
<text x="220.6" y="87.5">HDMI1_CEC</text>
<text x="220.9" y="84.9">HDMI1_SCL</text>
<text x="264.4" y="84.9">HDMI1_TX2_N</text>
<text x="264.4" y="87.5">GND</text>
<text x="264.4" y="90">HDMI1_TX1_P</text>
<text x="34.4" y="91.3">CAM1_D0_P</text>
<text x="41.6" y="93.8">LED3</text>
<text x="88.5" y="91.3">CAM1_D0_N</text>
<text x="88.5" y="93.8">LED7</text>
<text x="119.6" y="93.8">GPIO15</text>
<text x="143.1" y="93.8">SD_CLK</text>
<text x="157.7" y="95.1">GPIO14</text>
<text x="161.3" y="92.5">GND</text>
<text x="197.1" y="92.5">GPIO4</text>
<text x="197.1" y="95.1">GPIO3</text>
<text x="214.8" y="92.5">HDMI0_HOTPLUG</text>
<text x="228.6" y="95.1">GND</text>
<text x="264.4" y="95.1">GND</text>
<text x="264.4" y="92.5">HDMI1_TX1_N</text>
<text x="24.5" y="98.9">USB_FPGA_PULL_D-</text>
<text x="31.3" y="101.4">USB_FPGA_D+</text>
<text x="34.4" y="96.3">CAM1_D1_P</text>
<text x="88.5" y="98.9">USB_FPGA_PULL_D+</text>
<text x="88.5" y="101.4">USB_FPGA_D-</text>
<text x="88.5" y="96.3">CAM1_D1_N</text>
<text x="119" y="96.3">GPIO14</text>
<text x="120.4" y="98.9">GPIO4</text>
<text x="120.4" y="101.4">GPIO3</text>
<text x="143.1" y="101.4">SD_DAT1</text>
<text x="143.1" y="96.3">SD_DAT3</text>
<text x="143.1" y="98.9">SD_DAT0</text>
<text x="157.5" y="97.6">SD_CLK</text>
<text x="161.3" y="100.2">GND</text>
<text x="197.1" y="100.2">GND</text>
<text x="197.1" y="97.6">GPIO2</text>
<text x="221.2" y="97.6">DSI0_D0_N</text>
<text x="221.3" y="100.2">DSI0_D0_P</text>
<text x="264.4" y="97.6">HDMI1_TX0_P</text>
<text x="264.4" y="100.2">HDMI1_TX0_N</text>
<text x="31.2" y="106.5">CAM0_D1_P</text>
<text x="41.6" y="104">LED2</text>
<text x="88.5" y="104">LED4</text>
<text x="91.1" y="106.5">CAM0_D1_N</text>
<text x="119" y="106.5">GPIO27</text>
<text x="120.4" y="104">GPIO2</text>
<text x="143.1" y="104">SD_DAT2</text>
<text x="143.1" y="106.5">SD_CMD</text>
<text x="156.4" y="105.2">SD_DAT0</text>
<text x="156.4" y="102.7">SD_DAT3</text>
<text x="161.3" y="107.8">GND</text>
<text x="197.1" y="102.7">SD_CMD</text>
<text x="197.1" y="105.2">SD_DAT5</text>
<text x="197.1" y="107.8">GND</text>
<text x="221.2" y="105.2">DSI0_D1_N</text>
<text x="221.3" y="107.8">DSI0_D1_P</text>
<text x="228.6" y="102.7">GND</text>
<text x="264.4" y="107.8">HDMI1_CLK_N</text>
<text x="264.4" y="102.7">GND</text>
<text x="264.4" y="105.2">HDMI1_CLK_P</text>
<text x="41.5" y="109">BTN2</text>
<text x="41.6" y="111.6">LED5</text>
<text x="88.5" y="109">BTN1</text>
<text x="88.5" y="111.6">LED6</text>
<text x="156.4" y="112.9">SD_DAT2</text>
<text x="156.4" y="110.3">SD_DAT1</text>
<text x="197.1" y="110.3">SD_DAT4</text>
<text x="197.1" y="112.9">SD_DAT7</text>
<text x="222.7" y="112.9">DSI0_C_N</text>
<text x="228.6" y="110.3">GND</text>
<text x="264.4" y="110.3">GND</text>
<text x="264.4" y="112.9">HDMI0_TX2_P</text>
<text x="33.3" y="119.2">CAM0_C_P</text>
<text x="88.5" y="114.1">GPIO17</text>
<text x="90.4" y="119.2">CAM0_C_N</text>
<text x="146.9" y="117.9">SD_VDD_Override</text>
<text x="161.3" y="115.4">GND</text>
<text x="197.1" y="115.4">SD_DAT6</text>
<text x="197.1" y="117.9">GND</text>
<text x="222.8" y="115.4">DSI0_C_P</text>
<text x="228.6" y="117.9">GND</text>
<text x="264.4" y="117.9">GND</text>
<text x="264.4" y="115.4">HDMI0_TX2_N</text>
<text x="33.3" y="121.7">CAM1_C_P</text>
<text x="64.1" y="125.5">BANK7</text>
<text x="90.4" y="121.7">CAM1_C_N</text>
<text x="126.8" y="124.8" transform="rotate(-90 126.8 124.8)">CM4_3.3V</text>
<text x="152.7" y="120.5">SD_PWR_ON</text>
<text x="197.1" y="125.6">SCL0</text>
<text x="197.1" y="123">GPIO_VREF</text>
<text x="221.2" y="120.5">DSI1_D0_N</text>
<text x="221.3" y="123">DSI1_D0_P</text>
<text x="228.6" y="125.6">GND</text>
<text x="264.4" y="123">HDMI0_TX1_N</text>
<text x="264.4" y="120.5">HDMI0_TX1_P</text>
<text x="264.4" y="125.6">GND</text>
<text x="197.1" y="130.6">CM4_3.3V</text>
<text x="197.1" y="128.1">SDA0</text>
<text x="221.2" y="128.1">DSI1_D1_N</text>
<text x="221.3" y="130.6">DSI1_D1_P</text>
<text x="264.4" y="128.1">HDMI0_TX0_P</text>
<text x="264.4" y="130.6">HDMI0_TX0_N</text>
<text x="41.9" y="137">ETH_nLED3</text>
<text x="197.1" y="135.7">CM4_1.8V</text>
<text x="197.1" y="133.2">CM4_3.3V</text>
<text x="222.7" y="135.7">DSI1_C_N</text>
<text x="228.6" y="133.2">GND</text>
<text x="264.4" y="135.7">HDMI0_CLK_P</text>
<text x="264.4" y="133.2">GND</text>
<text x="41.9" y="139.5">ETH_nLED2</text>
<text x="41.9" y="142.1">ETH_nLED1</text>
<text x="152.1" y="138.3">WL_nDisable</text>
<text x="152.4" y="140.8">BT_nDisable</text>
<text x="154.9" y="143.3">nRPIBOOT</text>
<text x="197.1" y="138.3">CM4_1.8V</text>
<text x="197.1" y="143.3">AnalogIP1</text>
<text x="197.1" y="140.8">RUN_PG</text>
<text x="221.2" y="143.3">DSI1_D2_N</text>
<text x="222.8" y="138.3">DSI1_C_P</text>
<text x="228.6" y="140.8">GND</text>
<text x="264.4" y="140.8">GND</text>
<text x="264.4" y="143.3">DSI1_D3_N</text>
<text x="264.4" y="138.3">HDMI0_CLK_N</text>
<text x="37.5" y="148.4">ETH_SYNC_OUT</text>
<text x="39.5" y="145.9">ETH_SYNC_IN</text>
<text x="150.9" y="148.4">Camera_GPIO</text>
<text x="151.1" y="145.9">PI_LED_nPWR</text>
<text x="197.1" y="148.4">GND</text>
<text x="197.1" y="145.9">AnalogIP0</text>
<text x="221.3" y="145.9">DSI1_D2_P</text>
<text x="228.6" y="148.4">GND</text>
<text x="264.4" y="145.9">DSI1_D3_P</text>
<text x="264.4" y="148.4">GND</text>
<text x="153.4" y="151">GLOBAL_EN</text>
<text x="197.1" y="151">nEXTRST</text>
<text x="220.8" y="151">HDMI0_SDA</text>
<text x="264.4" y="151">HDMI0_SCL</text>
<text x="89.2" y="159.2">GND</text>
<text x="89.2" y="161.8">SRX11P</text>
<text x="89.2" y="164.3">SRX11N</text>
<text x="89.2" y="166.8">STX11P</text>
<text x="89.2" y="169.4">STX11N</text>
<text x="89.2" y="171.9">SRCLK1P</text>
<text x="89.2" y="174.5">SRCLK1N</text>
<text x="178" y="178">GPIO 2.54</text>
<text x="178" y="175">License:</text>
<text x="188.4" y="175">CERN-OHL-S</text>
<text x="190.9" y="178">mm</text>
<text x="196.2" y="178">connectors</text>
<text x="205.1" y="175">v2</text>
<text x="178" y="184">Sheet:</text>
<text x="178" y="181.2">EMARD</text>
<text x="186.2" y="184">/gpio/</text>
<text x="178" y="186.7">File:</text>
<text x="184.1" y="186.7">gpio.kicad_sch</text>
<text x="178" y="196.9">KiCad</text>
<text x="178" y="194.1">Size:</text>
<text x="184.7" y="194.1">A4</text>
<text x="185.7" y="196.9">E.D.A.</text>
<text x="193.3" y="196.9">8.0.8</text>
<text x="200" y="194.1">Date:</text>
<text x="207" y="194.1">2024-08-20</text>
<text x="263" y="194.3">Rev:</text>
<text x="263" y="196.9">Id:</text>
<text x="267.1" y="196.9">3/11</text>
<text x="269.4" y="194.3">0.0.4</text>
</g>
<g font-size="2.1" fill="#0000c2">
<text x="43.2" y="60.7">SINGLE ENDED -</text>
<text x="64.3" y="60.7">NOT DIFFERENTIAL</text>
<text x="122.6" y="119.4" transform="rotate(-90 122.6 119.4)">IO board</text>
<text x="122.6" y="125.4" transform="rotate(-90 122.6 125.4)">CM4</text>
<text x="122.6" y="129" transform="rotate(-90 122.6 129)">to</text>
<text x="122.6" y="135.2" transform="rotate(-90 122.6 135.2)">3.3V</text>
<text x="122.6" y="148.4" transform="rotate(-90 122.6 148.4)">to</text>
<text x="122.6" y="144.8" transform="rotate(-90 122.6 144.8)">provide</text>
<text x="122.6" y="156.3" transform="rotate(-90 122.6 156.3)">needs</text>
<text x="122.6" y="162.3" transform="rotate(-90 122.6 162.3)">CM4</text>
</g>
<text font-size="2.1" fill="#0f0f0f" x="34" y="82.2">CAM0_D0_LP</text>
<g font-size="1.8" fill="#840000">
<text x="35" y="11.9">1</text>
<text x="85" y="11.9">2</text>
<text x="135" y="11.9">3</text>
<text x="185" y="11.9">4</text>
<text x="235" y="11.9">5</text>
<text x="285" y="11.9">6</text>
<text x="10.3" y="35.9">A</text>
<text x="285.3" y="35.9">A</text>
<text x="39" y="45.4">ETH_MDIO</text>
<text x="10.3" y="85.9">B</text>
<text x="285.3" y="85.9">B</text>
<text x="34.5" y="116.5">RGMII_TX_CLK</text>
<text x="88.3" y="116.5">ETH_~{RESET}</text>
<text x="10.3" y="135.9">C</text>
<text x="285.3" y="135.9">C</text>
<text x="10.3" y="185.9">D</text>
<text x="285.3" y="185.9">D</text>
<text x="35" y="199.9">1</text>
<text x="85" y="199.9">2</text>
<text x="135" y="199.9">3</text>
<text x="185" y="199.9">4</text>
<text x="235" y="199.9">5</text>
<text x="285" y="199.9">6</text>
</g>
<g font-size="1.8" fill="#a90000">
<text x="50.1" y="18.8">B11</text>
<text x="50.2" y="21.3">A10</text>
<text x="50.8" y="23.9">A9</text>
<text x="83.1" y="23.9">B10</text>
<text x="83.1" y="18.8">C11</text>
<text x="83.2" y="21.3">A11</text>
<text x="50.7" y="26.4">B9</text>
<text x="50.7" y="29">D9</text>
<text x="83.1" y="26.4">C10</text>
<text x="83.8" y="29">E9</text>
<text x="50.7" y="34">C8</text>
<text x="50.8" y="31.5">A7</text>
<text x="83.7" y="34">B8</text>
<text x="83.8" y="31.5">A8</text>
<text x="50.7" y="39.1">C6</text>
<text x="50.8" y="41.7">E7</text>
<text x="50.8" y="36.6">E8</text>
<text x="83.7" y="39.1">C7</text>
<text x="83.7" y="41.7">D7</text>
<text x="83.7" y="36.6">D8</text>
<text x="50.8" y="44.2">E6</text>
<text x="50.8" y="46.7">A6</text>
<text x="83.7" y="46.7">B6</text>
<text x="83.7" y="44.2">D6</text>
<text x="50.1" y="49.3">D10</text>
<text x="50.7" y="51.8">C9</text>
<text x="83.2" y="49.3">E10</text>
<text x="50.1" y="82.3">B5</text>
<text x="83.1" y="82.3">C5</text>
<text x="50.1" y="89.9">C4</text>
<text x="50.2" y="87.4">A3</text>
<text x="50.2" y="84.8">A4</text>
<text x="83.1" y="87.4">B3</text>
<text x="83.1" y="89.9">B4</text>
<text x="83.2" y="84.8">A5</text>
<text x="50.1" y="92.5">C3</text>
<text x="50.2" y="95">E4</text>
<text x="83.1" y="92.5">D3</text>
<text x="83.1" y="95">D5</text>
<text x="50.2" y="97.5">E5</text>
<text x="50.2" y="100.1">F4</text>
<text x="83.2" y="100.1">E3</text>
<text x="83.2" y="97.5">F5</text>
<text x="50.1" y="102.6">B2</text>
<text x="50.1" y="107.7">D2</text>
<text x="50.2" y="105.2">A2</text>
<text x="83.1" y="105.2">B1</text>
<text x="83.1" y="102.6">C2</text>
<text x="83.2" y="107.7">E1</text>
<text x="50.1" y="112.8">H5</text>
<text x="50.1" y="110.2">C1</text>
<text x="83.1" y="112.8">H3</text>
<text x="83.1" y="110.2">D1</text>
<text x="50.1" y="115.3">H4</text>
<text x="50.2" y="117.9">F2</text>
<text x="83.1" y="115.3">G5</text>
<text x="83.2" y="117.9">E2</text>
<text x="50.1" y="120.4">G3</text>
<text x="83.2" y="120.4">F3</text>
<text x="85" y="160.4">6</text>
<text x="85" y="157.9">7</text>
<text x="85" y="165.5">4</text>
<text x="85" y="162.9">5</text>
<text x="85" y="173.1">1</text>
<text x="85" y="170.6">2</text>
<text x="85" y="168">3</text>
</g>
<g font-size="1.8" fill="#006464">
<text x="55.6" y="22.5">PCLKT0_1</text>
<text x="55.6" y="19.9">PCLKT0_0</text>
<text x="71.8" y="22.5">PCLKC0_1</text>
<text x="71.8" y="19.9">PCLKC0_0</text>
<text x="169.7" y="21.8">DF40C-100DP-0.4V(51)</text>
<text x="180.4" y="19.5">J1</text>
<text x="237" y="21.8">DF40C-100DP-0.4V(51)</text>
<text x="247.7" y="19.5">J2</text>
<text x="55.6" y="25">GR_PCLK0_1</text>
<text x="55.6" y="27.5">PT58A</text>
<text x="69.6" y="25">GR_PCLK0_0</text>
<text x="75.4" y="27.5">PT58B</text>
<text x="98.4" y="28.9">TP_E9</text>
<text x="55.6" y="32.6">PT18A</text>
<text x="55.6" y="35.2">PT15A</text>
<text x="55.6" y="30.1">PT20A</text>
<text x="75.4" y="32.6">PT18B</text>
<text x="75.4" y="35.2">PT15B</text>
<text x="75.4" y="30.1">PT20B</text>
<text x="98.4" y="31.2">E9</text>
<text x="31.7" y="37.7">TP_E8</text>
<text x="37.5" y="36.6">E8</text>
<text x="55.6" y="40.2">PT11A</text>
<text x="55.6" y="37.7">PT13A</text>
<text x="75.4" y="40.2">PT11B</text>
<text x="75.4" y="37.7">PT13B</text>
<text x="95.8" y="38.8">D8</text>
<text x="98.4" y="37.7">TP_D8</text>
<text x="55.6" y="47.9">PT4A</text>
<text x="55.6" y="45.3">PT6A</text>
<text x="55.6" y="42.8">PT9A</text>
<text x="76.6" y="47.9">PT4B</text>
<text x="76.6" y="45.3">PT6B</text>
<text x="76.6" y="42.8">PT9B</text>
<text x="55.6" y="52.9">PT54A</text>
<text x="55.6" y="50.4">PT56A</text>
<text x="75.4" y="50.4">PT56B</text>
<text x="55" y="83.4">PL11C</text>
<text x="74.7" y="83.4">PL11D</text>
<text x="55" y="88.5">PL14C</text>
<text x="55" y="86">PL11A</text>
<text x="74.7" y="86">PL11B</text>
<text x="74.7" y="88.5">PL14D</text>
<text x="55" y="93.6">PL17C</text>
<text x="55" y="91">PL14A</text>
<text x="74.7" y="91">PL14B</text>
<text x="74.7" y="93.6">PL17D</text>
<text x="55" y="96.1">PL17A</text>
<text x="55" y="98.7">PL20C</text>
<text x="55" y="101.2">PL20A</text>
<text x="74.7" y="96.1">PL17B</text>
<text x="74.7" y="101.2">PL20B</text>
<text x="74.7" y="98.7">PL20D</text>
<text x="55" y="106.3">PL35A</text>
<text x="55" y="103.7">VREF1_7</text>
<text x="74.7" y="106.3">PL35B</text>
<text x="74.7" y="103.7">PL35D</text>
<text x="55" y="111.4">PL38A</text>
<text x="55" y="108.8">PL38C</text>
<text x="55" y="113.9">GR_PCLK7_0</text>
<text x="74.7" y="111.4">PL38B</text>
<text x="74.7" y="108.8">PL38D</text>
<text x="74.7" y="113.9">PL41D</text>
<text x="55" y="119">PCLKT7_0</text>
<text x="55" y="116.4">GR_PCLK7_1</text>
<text x="71.2" y="119">PCLKC7_0</text>
<text x="74.7" y="116.4">PL41B</text>
<text x="55" y="121.5">PCLKT7_1</text>
<text x="71.2" y="121.5">PCLKC7_1</text>
<text x="152.2" y="130.3" transform="rotate(-90 152.2 130.3)">+5V</text>
<text x="123.1" y="135.9">+3V3</text>
<text x="81.3" y="155.6">SerDes</text>
<text x="83.4" y="153.3">J5</text>
</g>
<text font-size="1.8" fill="#0f0f0f" x="31.7" y="81.5">R21</text>
<g font-size="1.4" fill="#a90000">
<text x="170.8" y="25.1">1</text>
<text x="170.8" y="27.7">3</text>
<text x="191.2" y="25.1">2</text>
<text x="191.2" y="27.7">4</text>
<text x="238.1" y="25.1">1</text>
<text x="238.1" y="27.7">3</text>
<text x="258.5" y="25.1">2</text>
<text x="258.5" y="27.7">4</text>
<text x="170.8" y="30.2">5</text>
<text x="170.8" y="32.8">7</text>
<text x="170.8" y="35.3">9</text>
<text x="190.7" y="35.3">10</text>
<text x="191.2" y="30.2">6</text>
<text x="191.2" y="32.8">8</text>
<text x="238.1" y="30.2">5</text>
<text x="238.1" y="32.8">7</text>
<text x="238.1" y="35.3">9</text>
<text x="258" y="35.3">10</text>
<text x="258.5" y="30.2">6</text>
<text x="258.5" y="32.8">8</text>
<text x="170.4" y="37.8">11</text>
<text x="170.4" y="40.4">13</text>
<text x="190.7" y="37.8">12</text>
<text x="190.7" y="40.4">14</text>
<text x="237.7" y="37.8">11</text>
<text x="237.7" y="40.4">13</text>
<text x="258" y="37.8">12</text>
<text x="258" y="40.4">14</text>
<text x="170.4" y="42.9">15</text>
<text x="170.4" y="45.5">17</text>
<text x="190.7" y="42.9">16</text>
<text x="190.7" y="45.5">18</text>
<text x="237.7" y="42.9">15</text>
<text x="237.7" y="45.5">17</text>
<text x="258" y="42.9">16</text>
<text x="258" y="45.5">18</text>
<text x="170.4" y="48">19</text>
<text x="170.4" y="50.5">21</text>
<text x="170.4" y="53.1">23</text>
<text x="190.7" y="48">20</text>
<text x="190.7" y="50.5">22</text>
<text x="190.7" y="53.1">24</text>
<text x="237.7" y="48">19</text>
<text x="237.7" y="50.5">21</text>
<text x="237.7" y="53.1">23</text>
<text x="258" y="48">20</text>
<text x="258" y="50.5">22</text>
<text x="258" y="53.1">24</text>
<text x="170.4" y="55.6">25</text>
<text x="170.4" y="58.2">27</text>
<text x="190.7" y="55.6">26</text>
<text x="190.7" y="58.2">28</text>
<text x="237.7" y="55.6">25</text>
<text x="237.7" y="58.2">27</text>
<text x="258" y="55.6">26</text>
<text x="258" y="58.2">28</text>
<text x="170.4" y="60.7">29</text>
<text x="170.4" y="63.2">31</text>
<text x="170.4" y="65.8">33</text>
<text x="190.7" y="60.7">30</text>
<text x="190.7" y="63.2">32</text>
<text x="190.7" y="65.8">34</text>
<text x="237.7" y="60.7">29</text>
<text x="237.7" y="63.2">31</text>
<text x="237.7" y="65.8">33</text>
<text x="258" y="60.7">30</text>
<text x="258" y="63.2">32</text>
<text x="258" y="65.8">34</text>
<text x="170.4" y="68.3">35</text>
<text x="170.4" y="70.9">37</text>
<text x="190.7" y="68.3">36</text>
<text x="190.7" y="70.9">38</text>
<text x="237.7" y="68.3">35</text>
<text x="237.7" y="70.9">37</text>
<text x="258" y="68.3">36</text>
<text x="258" y="70.9">38</text>
<text x="170.4" y="73.4">39</text>
<text x="170.4" y="75.9">41</text>
<text x="190.7" y="73.4">40</text>
<text x="190.7" y="75.9">42</text>
<text x="237.7" y="73.4">39</text>
<text x="237.7" y="75.9">41</text>
<text x="258" y="73.4">40</text>
<text x="258" y="75.9">42</text>
<text x="170.4" y="78.5">43</text>
<text x="170.4" y="81">45</text>
<text x="170.4" y="83.6">47</text>
<text x="190.7" y="78.5">44</text>
<text x="190.7" y="81">46</text>
<text x="190.7" y="83.6">48</text>
<text x="237.7" y="78.5">43</text>
<text x="237.7" y="81">45</text>
<text x="237.7" y="83.6">47</text>
<text x="258" y="78.5">44</text>
<text x="258" y="81">46</text>
<text x="258" y="83.6">48</text>
<text x="170.4" y="86.1">49</text>
<text x="170.4" y="88.6">51</text>
<text x="190.7" y="86.1">50</text>
<text x="190.7" y="88.6">52</text>
<text x="237.7" y="86.1">49</text>
<text x="237.7" y="88.6">51</text>
<text x="258" y="86.1">50</text>
<text x="258" y="88.6">52</text>
<text x="170.4" y="91.2">53</text>
<text x="170.4" y="93.7">55</text>
<text x="190.7" y="91.2">54</text>
<text x="190.7" y="93.7">56</text>
<text x="237.7" y="91.2">53</text>
<text x="237.7" y="93.7">55</text>
<text x="258" y="91.2">54</text>
<text x="258" y="93.7">56</text>
<text x="170.4" y="96.3">57</text>
<text x="170.4" y="98.8">59</text>
<text x="170.4" y="101.3">61</text>
<text x="190.7" y="96.3">58</text>
<text x="190.7" y="98.8">60</text>
<text x="190.7" y="101.3">62</text>
<text x="237.7" y="96.3">57</text>
<text x="237.7" y="98.8">59</text>
<text x="237.7" y="101.3">61</text>
<text x="258" y="96.3">58</text>
<text x="258" y="98.8">60</text>
<text x="258" y="101.3">62</text>
<text x="170.4" y="103.9">63</text>
<text x="170.4" y="106.4">65</text>
<text x="190.7" y="103.9">64</text>
<text x="190.7" y="106.4">66</text>
<text x="237.7" y="103.9">63</text>
<text x="237.7" y="106.4">65</text>
<text x="258" y="103.9">64</text>
<text x="258" y="106.4">66</text>
<text x="170.4" y="109">67</text>
<text x="170.4" y="111.5">69</text>
<text x="190.7" y="109">68</text>
<text x="190.7" y="111.5">70</text>
<text x="237.7" y="109">67</text>
<text x="237.7" y="111.5">69</text>
<text x="258" y="109">68</text>
<text x="258" y="111.5">70</text>
<text x="170.4" y="114">71</text>
<text x="170.4" y="116.6">73</text>
<text x="170.4" y="119.1">75</text>
<text x="190.7" y="114">72</text>
<text x="190.7" y="116.6">74</text>
<text x="190.7" y="119.1">76</text>
<text x="237.7" y="114">71</text>
<text x="237.7" y="116.6">73</text>
<text x="237.7" y="119.1">75</text>
<text x="258" y="114">72</text>
<text x="258" y="116.6">74</text>
<text x="258" y="119.1">76</text>
<text x="170.4" y="121.7">77</text>
<text x="170.4" y="124.2">79</text>
<text x="190.7" y="121.7">78</text>
<text x="190.7" y="124.2">80</text>
<text x="237.7" y="121.7">77</text>
<text x="237.7" y="124.2">79</text>
<text x="258" y="121.7">78</text>
<text x="258" y="124.2">80</text>
<text x="170.4" y="126.7">81</text>
<text x="170.4" y="129.3">83</text>
<text x="170.4" y="131.8">85</text>
<text x="190.7" y="126.7">82</text>
<text x="190.7" y="129.3">84</text>
<text x="190.7" y="131.8">86</text>
<text x="237.7" y="126.7">81</text>
<text x="237.7" y="129.3">83</text>
<text x="237.7" y="131.8">85</text>
<text x="258" y="126.7">82</text>
<text x="258" y="129.3">84</text>
<text x="258" y="131.8">86</text>
<text x="170.4" y="134.4">87</text>
<text x="170.4" y="136.9">89</text>
<text x="190.7" y="134.4">88</text>
<text x="190.7" y="136.9">90</text>
<text x="237.7" y="134.4">87</text>
<text x="237.7" y="136.9">89</text>
<text x="258" y="134.4">88</text>
<text x="258" y="136.9">90</text>
<text x="170.4" y="139.4">91</text>
<text x="170.4" y="142">93</text>
<text x="190.7" y="139.4">92</text>
<text x="190.7" y="142">94</text>
<text x="237.7" y="139.4">91</text>
<text x="237.7" y="142">93</text>
<text x="258" y="139.4">92</text>
<text x="258" y="142">94</text>
<text x="170.4" y="144.5">95</text>
<text x="170.4" y="147.1">97</text>
<text x="170.4" y="149.6">99</text>
<text x="190.2" y="149.6">100</text>
<text x="190.7" y="144.5">96</text>
<text x="190.7" y="147.1">98</text>
<text x="237.7" y="144.5">95</text>
<text x="237.7" y="147.1">97</text>
<text x="237.7" y="149.6">99</text>
<text x="257.5" y="149.6">100</text>
<text x="258" y="144.5">96</text>
<text x="258" y="147.1">98</text>
</g>
<g font-size="1.4" fill="#006464">
<text x="175" y="26.1">1</text>
<text x="175" y="28.7">3</text>
<text x="187" y="26.1">2</text>
<text x="187" y="28.7">4</text>
<text x="242.3" y="26.1">1</text>
<text x="242.3" y="28.7">3</text>
<text x="254.3" y="26.1">2</text>
<text x="254.3" y="28.7">4</text>
<text x="175" y="31.2">5</text>
<text x="175" y="33.8">7</text>
<text x="187" y="31.2">6</text>
<text x="187" y="33.8">8</text>
<text x="242.3" y="31.2">5</text>
<text x="242.3" y="33.8">7</text>
<text x="254.3" y="31.2">6</text>
<text x="254.3" y="33.8">8</text>
<text x="175" y="38.8">11</text>
<text x="175" y="41.4">13</text>
<text x="175" y="36.3">9</text>
<text x="186" y="36.3">10</text>
<text x="186" y="38.8">12</text>
<text x="186" y="41.4">14</text>
<text x="242.3" y="38.8">11</text>
<text x="242.3" y="41.4">13</text>
<text x="242.3" y="36.3">9</text>
<text x="253.3" y="36.3">10</text>
<text x="253.3" y="38.8">12</text>
<text x="253.3" y="41.4">14</text>
<text x="175" y="43.9">15</text>
<text x="175" y="46.5">17</text>
<text x="186" y="43.9">16</text>
<text x="186" y="46.5">18</text>
<text x="242.3" y="43.9">15</text>
<text x="242.3" y="46.5">17</text>
<text x="253.3" y="43.9">16</text>
<text x="253.3" y="46.5">18</text>
<text x="175" y="49">19</text>
<text x="175" y="51.5">21</text>
<text x="186" y="49">20</text>
<text x="186" y="51.5">22</text>
<text x="242.3" y="49">19</text>
<text x="242.3" y="51.5">21</text>
<text x="253.3" y="49">20</text>
<text x="253.3" y="51.5">22</text>
<text x="175" y="54.1">23</text>
<text x="175" y="56.6">25</text>
<text x="175" y="59.2">27</text>
<text x="186" y="54.1">24</text>
<text x="186" y="56.6">26</text>
<text x="186" y="59.2">28</text>
<text x="242.3" y="54.1">23</text>
<text x="242.3" y="56.6">25</text>
<text x="242.3" y="59.2">27</text>
<text x="253.3" y="54.1">24</text>
<text x="253.3" y="56.6">26</text>
<text x="253.3" y="59.2">28</text>
<text x="175" y="61.7">29</text>
<text x="175" y="64.2">31</text>
<text x="186" y="61.7">30</text>
<text x="186" y="64.2">32</text>
<text x="242.3" y="61.7">29</text>
<text x="242.3" y="64.2">31</text>
<text x="253.3" y="61.7">30</text>
<text x="253.3" y="64.2">32</text>
<text x="175" y="66.8">33</text>
<text x="175" y="69.3">35</text>
<text x="175" y="71.9">37</text>
<text x="186" y="66.8">34</text>
<text x="186" y="69.3">36</text>
<text x="186" y="71.9">38</text>
<text x="242.3" y="66.8">33</text>
<text x="242.3" y="69.3">35</text>
<text x="242.3" y="71.9">37</text>
<text x="253.3" y="66.8">34</text>
<text x="253.3" y="69.3">36</text>
<text x="253.3" y="71.9">38</text>
<text x="175" y="74.4">39</text>
<text x="175" y="76.9">41</text>
<text x="186" y="74.4">40</text>
<text x="186" y="76.9">42</text>
<text x="242.3" y="74.4">39</text>
<text x="242.3" y="76.9">41</text>
<text x="253.3" y="74.4">40</text>
<text x="253.3" y="76.9">42</text>
<text x="175" y="79.5">43</text>
<text x="175" y="82">45</text>
<text x="186" y="79.5">44</text>
<text x="186" y="82">46</text>
<text x="242.3" y="79.5">43</text>
<text x="242.3" y="82">45</text>
<text x="253.3" y="79.5">44</text>
<text x="253.3" y="82">46</text>
<text x="28.9" y="84.5">300</text>
<text x="175" y="84.6">47</text>
<text x="175" y="87.1">49</text>
<text x="175" y="89.6">51</text>
<text x="186" y="84.6">48</text>
<text x="186" y="87.1">50</text>
<text x="186" y="89.6">52</text>
<text x="242.3" y="84.6">47</text>
<text x="242.3" y="87.1">49</text>
<text x="242.3" y="89.6">51</text>
<text x="253.3" y="84.6">48</text>
<text x="253.3" y="87.1">50</text>
<text x="253.3" y="89.6">52</text>
<text x="175" y="92.2">53</text>
<text x="175" y="94.7">55</text>
<text x="186" y="92.2">54</text>
<text x="186" y="94.7">56</text>
<text x="242.3" y="92.2">53</text>
<text x="242.3" y="94.7">55</text>
<text x="253.3" y="92.2">54</text>
<text x="253.3" y="94.7">56</text>
<text x="175" y="97.3">57</text>
<text x="175" y="99.8">59</text>
<text x="186" y="97.3">58</text>
<text x="186" y="99.8">60</text>
<text x="242.3" y="97.3">57</text>
<text x="242.3" y="99.8">59</text>
<text x="253.3" y="97.3">58</text>
<text x="253.3" y="99.8">60</text>
<text x="175" y="102.3">61</text>
<text x="175" y="104.9">63</text>
<text x="175" y="107.4">65</text>
<text x="186" y="102.3">62</text>
<text x="186" y="104.9">64</text>
<text x="186" y="107.4">66</text>
<text x="242.3" y="102.3">61</text>
<text x="242.3" y="104.9">63</text>
<text x="242.3" y="107.4">65</text>
<text x="253.3" y="102.3">62</text>
<text x="253.3" y="104.9">64</text>
<text x="253.3" y="107.4">66</text>
<text x="175" y="110">67</text>
<text x="175" y="112.5">69</text>
<text x="186" y="110">68</text>
<text x="186" y="112.5">70</text>
<text x="242.3" y="110">67</text>
<text x="242.3" y="112.5">69</text>
<text x="253.3" y="110">68</text>
<text x="253.3" y="112.5">70</text>
<text x="175" y="115">71</text>
<text x="175" y="117.6">73</text>
<text x="186" y="115">72</text>
<text x="186" y="117.6">74</text>
<text x="242.3" y="115">71</text>
<text x="242.3" y="117.6">73</text>
<text x="253.3" y="115">72</text>
<text x="253.3" y="117.6">74</text>
<text x="175" y="120.1">75</text>
<text x="175" y="122.7">77</text>
<text x="175" y="125.2">79</text>
<text x="186" y="120.1">76</text>
<text x="186" y="122.7">78</text>
<text x="186" y="125.2">80</text>
<text x="242.3" y="120.1">75</text>
<text x="242.3" y="122.7">77</text>
<text x="242.3" y="125.2">79</text>
<text x="253.3" y="120.1">76</text>
<text x="253.3" y="122.7">78</text>
<text x="253.3" y="125.2">80</text>
<text x="175" y="127.7">81</text>
<text x="175" y="130.3">83</text>
<text x="186" y="127.7">82</text>
<text x="186" y="130.3">84</text>
<text x="242.3" y="127.7">81</text>
<text x="242.3" y="130.3">83</text>
<text x="253.3" y="127.7">82</text>
<text x="253.3" y="130.3">84</text>
<text x="175" y="132.8">85</text>
<text x="175" y="135.4">87</text>
<text x="175" y="137.9">89</text>
<text x="186" y="132.8">86</text>
<text x="186" y="135.4">88</text>
<text x="186" y="137.9">90</text>
<text x="242.3" y="132.8">85</text>
<text x="242.3" y="135.4">87</text>
<text x="242.3" y="137.9">89</text>
<text x="253.3" y="132.8">86</text>
<text x="253.3" y="135.4">88</text>
<text x="253.3" y="137.9">90</text>
<text x="175" y="140.4">91</text>
<text x="175" y="143">93</text>
<text x="186" y="140.4">92</text>
<text x="186" y="143">94</text>
<text x="242.3" y="140.4">91</text>
<text x="242.3" y="143">93</text>
<text x="253.3" y="140.4">92</text>
<text x="253.3" y="143">94</text>
<text x="175" y="145.5">95</text>
<text x="175" y="148.1">97</text>
<text x="186" y="145.5">96</text>
<text x="186" y="148.1">98</text>
<text x="242.3" y="145.5">95</text>
<text x="242.3" y="148.1">97</text>
<text x="253.3" y="145.5">96</text>
<text x="253.3" y="148.1">98</text>
<text x="175" y="150.6">99</text>
<text x="185.1" y="150.6">100</text>
<text x="242.3" y="150.6">99</text>
<text x="252.4" y="150.6">100</text>
</g>
</g></defs>
<g fill="none" stroke="#840000" stroke-width=".18">
<path d="M10 10h277v190h-277zM12 12h273v186h-273zM60 10v2M110 10v2M160 10v2M210 10v2M260 10v2M41.3 36.8h.1M94.6 36.8h.1M97.2 29.2h.1M10 60h2M285 60h2"/>
<path d="M31.1 82.6h.8M48.9 82.6h5.1M48.9 87.6h5.1M48.9 85.1h5.1M48.9 90.2h5.1M48.9 92.7h5.1M48.9 95.3h5.1M48.9 97.8h5.1M54 80h27.9v43.2h-27.9zM61.6 94h12.7v12.7h-12.7zM62.9 95.3h2.5v5h-2.5zM81.9 82.6h5.1"/>
<path d="M81.9 87.6h5.1M81.9 85.1h5.1M81.9 90.2h5.1M81.9 92.7h5.1M81.9 95.3h5.1M81.9 97.8h5.1M10 110h2M48.9 105.4h5.1M48.9 102.9h5.1M48.9 110.5h5.1M48.9 108h5.1M48.9 118.1h5.1"/>
<path d="M48.9 100.3h5.1M48.9 115.6h5.1M48.9 113h5.1M81.9 105.4h5.1M81.9 102.9h5.1M81.9 110.5h5.1M81.9 108h5.1M81.9 118.1h5.1M81.9 100.3h5.1M81.9 115.6h5.1M81.9 113h5.1M285 110h2"/>
<path d="M48.9 120.7h5.1M81.9 120.7h5.1M125 132.7l.7 1.3M125.7 131.4v2.6M126.5 132.7l-.8 1.3M152.4 128.3h2.5M152.4 128.3l1.3 .7M153.7 127.5l-1.3 .8M10 160h2M177 166h108v32h-108zM186.8 174.6v.1M186.8 173.8v.1"/>
<path d="M188.4 177.2h.9M203.5 173.3l-.6-.1-.2 .1v.5l.6 .3 .2 .3-.3 .3-.6-.1M207.7 176.8l-.3-.1-.2 .2v.2l.5 .2v.3h-.5M285 160h2M60 198v2M110 198v2M160 198v2M177 194.5h108M177 191.5h108M177 187.5h108M177 181.5h108M182.5 186.3v.1"/>
<path d="M182.5 185.5v.1M184.7 183.6v.1M184.7 182.8v.1M192.1 182.8l.1 .2v.4l-.1 .2M194 182.1l-1.3 2M197 191.5v3M198.4 185.4l.4 .1M198.8 186.3l-.4 .1M199.5 185.5l.2-.1 .3 .1 .1 .9M199.5 184.9v1.5M210 198v2M217.7 193.2h1.2"/>
<path d="M219.5 192.4l.6-.1 .2 .1 .1 .3-.9 1.1h.9M221.1 192.4l.2-.1a.81 .81 0 0 1 .6 .6 .81 .81 0 0 1-.3 .8l-.1 .1a.81 .81 0 0 1-.4-1.4zM260 198v2M261 191.5v6.5M271.7 196.6h.9M271.7 195.5l.5-.4v1.5"/>
<circle cx="41.3" cy="36.8" r=".51"/>
<circle cx="94.6" cy="36.8" r=".51"/>
<circle cx="97.2" cy="29.2" r=".51"/>
</g>
<path d="M31.9 81.8h3.5v1.5h-3.5z" fill="none" stroke="#840000" stroke-width=".2"/>
<g fill="none" stroke="#006464" stroke-width=".18">
<path d="M76.8 77.9h.3l.2 .3-.2 .4M76.8 78.6h.3M77.1 78.6l.2 .1v.4l-.1 .3h-.4M77.9 79.4h.9M77.9 78.3l.5-.4v1.5M80.3 78.1a.61 .61 0 0 0-.7 0 .61 .61 0 0 0-.2 .7 .57 .57 0 0 0 .3 .6 .57 .57 0 0 0 .6-.1M31.7 83.5v.6M65.9 116.1h.7M63.3 121.2h.7M79.8 121.2h.8M127.2 134.3h.8l-.4 .5M127.8 134.8l.2 .2v.3l-.2 .3"/>
<path d="M150.7 126.5l1.3 .4"/>
</g>
<path d="M241.3 22.9h15.2v129.5h-15.2z" fill="#ffffc2"/>
<g fill="none" stroke="#840000" stroke-width=".25">
<path d="M241.3 22.9h15.2v129.5h-15.2zM241.3 38.1h1.9M241.3 35.6h1.9M241.3 33h1.9M241.3 30.5h1.9M241.3 27.9h1.9M241.3 25.4h1.9M254.6 38.1h1.9M254.6 35.6h1.9M254.6 33h1.9M254.6 30.5h1.9M254.6 27.9h1.9"/>
<path d="M254.6 25.4h1.9M241.3 58.4h1.9M241.3 55.9h1.9M241.3 53.3h1.9M241.3 50.8h1.9M241.3 48.3h1.9M241.3 45.7h1.9M241.3 43.2h1.9M241.3 40.6h1.9M254.6 58.4h1.9M254.6 55.9h1.9M254.6 53.3h1.9"/>
<path d="M254.6 50.8h1.9M254.6 48.3h1.9M254.6 45.7h1.9M254.6 43.2h1.9M254.6 40.6h1.9M241.3 78.7h1.9M241.3 76.2h1.9M241.3 73.7h1.9M241.3 71.1h1.9M241.3 68.6h1.9M241.3 66h1.9M241.3 63.5h1.9"/>
<path d="M241.3 61h1.9M254.6 78.7h1.9M254.6 76.2h1.9M254.6 73.7h1.9M254.6 71.1h1.9M254.6 68.6h1.9M254.6 66h1.9M254.6 63.5h1.9M254.6 61h1.9M241.3 99.1h1.9M241.3 96.5h1.9M241.3 94h1.9"/>
<path d="M241.3 91.4h1.9M241.3 88.9h1.9M241.3 86.4h1.9M241.3 83.8h1.9M241.3 81.3h1.9M254.6 99.1h1.9M254.6 96.5h1.9M254.6 94h1.9M254.6 91.4h1.9M254.6 88.9h1.9M254.6 86.4h1.9M254.6 83.8h1.9"/>
<path d="M254.6 81.3h1.9M241.3 119.4h1.9M241.3 116.8h1.9M241.3 114.3h1.9M241.3 111.8h1.9M241.3 109.2h1.9M241.3 106.7h1.9M241.3 104.1h1.9M241.3 101.6h1.9M254.6 119.4h1.9M254.6 116.8h1.9M254.6 114.3h1.9"/>
<path d="M254.6 111.8h1.9M254.6 109.2h1.9M254.6 106.7h1.9M254.6 104.1h1.9M254.6 101.6h1.9M241.3 139.7h1.9M241.3 137.2h1.9M241.3 134.6h1.9M241.3 132.1h1.9M241.3 129.5h1.9M241.3 127h1.9M241.3 124.5h1.9"/>
<path d="M241.3 121.9h1.9M254.6 139.7h1.9M254.6 137.2h1.9M254.6 134.6h1.9M254.6 132.1h1.9M254.6 129.5h1.9M254.6 127h1.9M254.6 124.5h1.9M254.6 121.9h1.9M241.3 149.9h1.9M241.3 147.3h1.9M241.3 144.8h1.9"/>
<path d="M241.3 142.2h1.9M254.6 149.9h1.9M254.6 147.3h1.9M254.6 144.8h1.9M254.6 142.2h1.9"/>
</g>
<g fill="#840000" stroke="#840000" stroke-width=".18">
<path d="M241.9 48h1.6v.6h-1.6z"/>
<path d="M241.9 45.4h1.6v.7h-1.6z"/>
<path d="M241.9 42.9h1.6v.6h-1.6z"/>
<path d="M241.9 40.3h1.6v.7h-1.6z"/>
<path d="M241.9 37.8h1.6v.6h-1.6z"/>
<path d="M241.9 25.1h1.6v.6h-1.6z"/>
<path d="M254.3 149.6h1.6v.6h-1.6z"/>
<path d="M254.3 147h1.6v.7h-1.6z"/>
<path d="M254.3 144.5h1.6v.6h-1.6z"/>
<path d="M254.3 141.9h1.6v.6h-1.6z"/>
<path d="M254.3 139.4h1.6v.6h-1.6z"/>
<path d="M254.3 136.9h1.6v.6h-1.6z"/>
<path d="M254.3 134.3h1.6v.7h-1.6z"/>
<path d="M254.3 131.8h1.6v.6h-1.6z"/>
<path d="M254.3 129.2h1.6v.7h-1.6z"/>
<path d="M254.3 126.7h1.6v.6h-1.6z"/>
<path d="M254.3 124.2h1.6v.6h-1.6z"/>
<path d="M254.3 121.6h1.6v.7h-1.6z"/>
<path d="M254.3 119.1h1.6v.6h-1.6z"/>
<path d="M254.3 116.5h1.6v.7h-1.6z"/>
<path d="M254.3 114h1.6v.6h-1.6z"/>
<path d="M254.3 111.4h1.6v.7h-1.6z"/>
<path d="M254.3 108.9h1.6v.7h-1.6z"/>
<path d="M254.3 106.4h1.6v.6h-1.6z"/>
<path d="M254.3 103.8h1.6v.7h-1.6z"/>
<path d="M254.3 101.3h1.6v.6h-1.6z"/>
<path d="M254.3 98.8h1.6v.6h-1.6z"/>
<path d="M254.3 96.2h1.6v.7h-1.6z"/>
<path d="M254.3 93.7h1.6v.6h-1.6z"/>
<path d="M254.3 91.1h1.6v.7h-1.6z"/>
<path d="M254.3 88.6h1.6v.6h-1.6z"/>
<path d="M254.3 86h1.6v.7h-1.6z"/>
<path d="M254.3 83.5h1.6v.6h-1.6z"/>
<path d="M254.3 80.9h1.6v.7h-1.6z"/>
<path d="M254.3 78.4h1.6v.6h-1.6z"/>
<path d="M254.3 75.9h1.6v.6h-1.6z"/>
<path d="M254.3 73.4h1.6v.6h-1.6z"/>
<path d="M254.3 70.8h1.6v.6h-1.6z"/>
<path d="M254.3 68.2h1.6v.7h-1.6z"/>
<path d="M254.3 65.7h1.6v.6h-1.6z"/>
<path d="M254.3 63.2h1.6v.6h-1.6z"/>
<path d="M254.3 60.6h1.6v.7h-1.6z"/>
<path d="M254.3 58.1h1.6v.7h-1.6z"/>
<path d="M254.3 55.5h1.6v.7h-1.6z"/>
<path d="M254.3 53h1.6v.6h-1.6z"/>
<path d="M254.3 50.5h1.6v.6h-1.6z"/>
<path d="M254.3 48h1.6v.6h-1.6z"/>
<path d="M254.3 45.4h1.6v.6h-1.6z"/>
<path d="M254.3 42.8h1.6v.7h-1.6z"/>
<path d="M254.3 40.3h1.6v.6h-1.6z"/>
<path d="M254.3 37.8h1.6v.6h-1.6z"/>
<path d="M254.3 35.3h1.6v.6h-1.6z"/>
<path d="M254.3 32.7h1.6v.6h-1.6z"/>
<path d="M254.3 30.2h1.6v.6h-1.6z"/>
<path d="M254.3 27.6h1.6v.6h-1.6z"/>
<path d="M254.3 25.1h1.6v.6h-1.6z"/>
</g>
<g fill="none" stroke="#840000" stroke-width=".18">
<path d="M236.2 25.4h5.1M236.2 35.6h5.1M236.2 38.1h5.1M236.2 27.9h5.1M236.2 30.5h5.1M236.2 33h5.1M256.5 25.4h5.1M256.5 35.6h5.1M256.5 38.1h5.1M256.5 27.9h5.1M256.5 30.5h5.1M256.5 33h5.1"/>
<path d="M236.2 40.6h5.1M236.2 43.2h5.1M236.2 45.7h5.1M236.2 48.3h5.1M236.2 50.8h5.1M236.2 53.3h5.1M236.2 55.9h5.1M236.2 58.4h5.1M256.5 40.6h5.1M256.5 43.2h5.1M256.5 45.7h5.1M256.5 48.3h5.1"/>
<path d="M256.5 50.8h5.1M256.5 53.3h5.1M256.5 55.9h5.1M256.5 58.4h5.1M236.2 61h5.1M236.2 63.5h5.1M236.2 66h5.1M236.2 68.6h5.1M236.2 71.1h5.1M236.2 73.7h5.1M236.2 76.2h5.1M236.2 78.7h5.1"/>
<path d="M256.5 61h5.1M256.5 63.5h5.1M256.5 66h5.1M256.5 68.6h5.1M256.5 71.1h5.1M256.5 73.7h5.1M256.5 76.2h5.1M256.5 78.7h5.1M236.2 81.3h5.1M236.2 83.8h5.1M236.2 86.4h5.1M236.2 88.9h5.1"/>
<path d="M236.2 91.4h5.1M236.2 94h5.1M236.2 96.5h5.1M236.2 99.1h5.1M256.5 81.3h5.1M256.5 83.8h5.1M256.5 86.4h5.1M256.5 88.9h5.1M256.5 91.4h5.1M256.5 94h5.1M256.5 96.5h5.1M256.5 99.1h5.1"/>
<path d="M236.2 101.6h5.1M236.2 104.1h5.1M236.2 106.7h5.1M236.2 109.2h5.1M236.2 111.8h5.1M236.2 114.3h5.1M236.2 116.8h5.1M236.2 119.4h5.1M256.5 101.6h5.1M256.5 104.1h5.1M256.5 106.7h5.1M256.5 109.2h5.1"/>
<path d="M256.5 111.8h5.1M256.5 114.3h5.1M256.5 116.8h5.1M256.5 119.4h5.1M236.2 121.9h5.1M236.2 124.5h5.1M236.2 127h5.1M236.2 129.5h5.1M236.2 132.1h5.1M236.2 134.6h5.1M236.2 137.2h5.1M236.2 139.7h5.1"/>
<path d="M256.5 121.9h5.1M256.5 124.5h5.1M256.5 127h5.1M256.5 129.5h5.1M256.5 132.1h5.1M256.5 134.6h5.1M256.5 137.2h5.1M256.5 139.7h5.1M236.2 149.9h5.1M236.2 142.2h5.1M236.2 144.8h5.1M236.2 147.3h5.1"/>
<path d="M256.5 149.9h5.1M256.5 142.2h5.1M256.5 144.8h5.1M256.5 147.3h5.1"/>
</g>
<g fill="none" stroke="#006464" stroke-width=".18">
<path d="M243.6 38.6h.6M257.3 20.1a1.46 1.46 0 0 0 0 1.9M258.4 20.2h-.7v.6l.2-.1 .4 .1 .1 .2v.4l-.2 .1-.5-.1M258.9 21.5h.7M258.9 20.6l.4-.4v1.3M260 20.1a1.46 1.46 0 0 1 0 1.9M243.6 51.3h.6M243.6 64h.6M243.6 76.7h.6M243.6 89.4h.6M243.6 102.1h.6M243.6 114.8h.6"/>
<path d="M243.6 127.5h.6M243.6 140.2h.6M255.1 149.4l.1 .3-.1 .5"/>
</g>
<path d="M239 37.7h.5M239 50.4h.5M239 63.1h.5M239 75.8h.5M239 88.5h.5M239 101.2h.5M239 113.9h.5M239 126.6h.5M239 139.3h.5M260.3 148.7v.6" fill="none" stroke="#a90000" stroke-width=".18"/>
<path d="M174 22.9h15.2v129.5h-15.2z" fill="#ffffc2"/>
<g fill="none" stroke="#840000" stroke-width=".25">
<path d="M174 22.9h15.2v129.5h-15.2zM174 38.1h1.9M174 35.6h1.9M174 33h1.9M174 30.5h1.9M174 27.9h1.9M174 25.4h1.9M187.3 38.1h1.9M187.3 35.6h1.9M187.3 33h1.9M187.3 30.5h1.9M187.3 27.9h1.9"/>
<path d="M187.3 25.4h1.9M174 58.4h1.9M174 55.9h1.9M174 53.3h1.9M174 50.8h1.9M174 48.3h1.9M174 45.7h1.9M174 43.2h1.9M174 40.6h1.9M187.3 58.4h1.9M187.3 55.9h1.9M187.3 53.3h1.9"/>
<path d="M187.3 50.8h1.9M187.3 48.3h1.9M187.3 45.7h1.9M187.3 43.2h1.9M187.3 40.6h1.9M174 78.7h1.9M174 76.2h1.9M174 73.7h1.9M174 71.1h1.9M174 68.6h1.9M174 66h1.9M174 63.5h1.9"/>
<path d="M174 61h1.9M187.3 78.7h1.9M187.3 76.2h1.9M187.3 73.7h1.9M187.3 71.1h1.9M187.3 68.6h1.9M187.3 66h1.9M187.3 63.5h1.9M187.3 61h1.9M174 99.1h1.9M174 96.5h1.9M174 94h1.9"/>
<path d="M174 91.4h1.9M174 88.9h1.9M174 86.4h1.9M174 83.8h1.9M174 81.3h1.9M187.3 99.1h1.9M187.3 96.5h1.9M187.3 94h1.9M187.3 91.4h1.9M187.3 88.9h1.9M187.3 86.4h1.9M187.3 83.8h1.9"/>
<path d="M187.3 81.3h1.9M174 119.4h1.9M174 116.8h1.9M174 114.3h1.9M174 111.8h1.9M174 109.2h1.9M174 106.7h1.9M174 104.1h1.9M174 101.6h1.9M187.3 119.4h1.9M187.3 116.8h1.9M187.3 114.3h1.9"/>
<path d="M187.3 111.8h1.9M187.3 109.2h1.9M187.3 106.7h1.9M187.3 104.1h1.9M187.3 101.6h1.9M174 139.7h1.9M174 137.2h1.9M174 134.6h1.9M174 132.1h1.9M174 129.5h1.9M174 127h1.9M174 124.5h1.9"/>
<path d="M174 121.9h1.9M187.3 139.7h1.9M187.3 137.2h1.9M187.3 134.6h1.9M187.3 132.1h1.9M187.3 129.5h1.9M187.3 127h1.9M187.3 124.5h1.9M187.3 121.9h1.9M174 149.9h1.9M174 147.3h1.9M174 144.8h1.9"/>
<path d="M174 142.2h1.9M187.3 149.9h1.9M187.3 147.3h1.9M187.3 144.8h1.9M187.3 142.2h1.9"/>
</g>
<g fill="#840000" stroke="#840000" stroke-width=".18">
<path d="M174.6 48h1.6v.6h-1.6z"/>
<path d="M174.6 45.4h1.6v.7h-1.6z"/>
<path d="M174.6 42.9h1.6v.6h-1.6z"/>
<path d="M174.6 40.3h1.6v.7h-1.6z"/>
<path d="M174.6 37.8h1.6v.6h-1.6z"/>
<path d="M174.6 25.1h1.6v.6h-1.6z"/>
<path d="M187 149.6h1.6v.6h-1.6z"/>
<path d="M187 147h1.6v.7h-1.6z"/>
<path d="M187 144.5h1.6v.6h-1.6z"/>
<path d="M187 141.9h1.6v.6h-1.6z"/>
<path d="M187 139.4h1.6v.6h-1.6z"/>
<path d="M187 136.9h1.6v.6h-1.6z"/>
<path d="M187 134.3h1.6v.7h-1.6z"/>
<path d="M187 131.8h1.6v.6h-1.6z"/>
<path d="M187 129.2h1.6v.7h-1.6z"/>
<path d="M187 126.7h1.6v.6h-1.6z"/>
<path d="M187 124.2h1.6v.6h-1.6z"/>
<path d="M187 121.6h1.6v.7h-1.6z"/>
<path d="M187 119.1h1.6v.6h-1.6z"/>
<path d="M187 116.5h1.6v.7h-1.6z"/>
<path d="M187 114h1.6v.6h-1.6z"/>
<path d="M187 111.4h1.6v.7h-1.6z"/>
<path d="M187 108.9h1.6v.7h-1.6z"/>
<path d="M187 106.4h1.6v.6h-1.6z"/>
<path d="M187 103.8h1.6v.7h-1.6z"/>
<path d="M187 101.3h1.6v.6h-1.6z"/>
<path d="M187 98.8h1.6v.6h-1.6z"/>
<path d="M187 96.2h1.6v.7h-1.6z"/>
<path d="M187 93.7h1.6v.6h-1.6z"/>
<path d="M187 91.1h1.6v.7h-1.6z"/>
<path d="M187 88.6h1.6v.6h-1.6z"/>
<path d="M187 86h1.6v.7h-1.6z"/>
<path d="M187 83.5h1.6v.6h-1.6z"/>
<path d="M187 80.9h1.6v.7h-1.6z"/>
<path d="M187 78.4h1.6v.6h-1.6z"/>
<path d="M187 75.9h1.6v.6h-1.6z"/>
<path d="M187 73.4h1.6v.6h-1.6z"/>
<path d="M187 70.8h1.6v.6h-1.6z"/>
<path d="M187 68.2h1.6v.7h-1.6z"/>
<path d="M187 65.7h1.6v.6h-1.6z"/>
<path d="M187 63.2h1.6v.6h-1.6z"/>
<path d="M187 60.6h1.6v.7h-1.6z"/>
<path d="M187 58.1h1.6v.7h-1.6z"/>
<path d="M187 55.5h1.6v.7h-1.6z"/>
<path d="M187 53h1.6v.6h-1.6z"/>
<path d="M187 50.5h1.6v.6h-1.6z"/>
<path d="M187 48h1.6v.6h-1.6z"/>
<path d="M187 45.4h1.6v.6h-1.6z"/>
<path d="M187 42.8h1.6v.7h-1.6z"/>
<path d="M187 40.3h1.6v.6h-1.6z"/>
<path d="M187 37.8h1.6v.6h-1.6z"/>
<path d="M187 35.3h1.6v.6h-1.6z"/>
<path d="M187 32.7h1.6v.6h-1.6z"/>
<path d="M187 30.2h1.6v.6h-1.6z"/>
<path d="M187 27.6h1.6v.6h-1.6z"/>
<path d="M187 25.1h1.6v.6h-1.6z"/>
</g>
<g fill="none" stroke="#840000" stroke-width=".18">
<path d="M168.9 25.4h5.1M168.9 35.6h5.1M168.9 38.1h5.1M168.9 27.9h5.1M168.9 30.5h5.1M168.9 33h5.1M189.2 25.4h5.1M189.2 35.6h5.1M189.2 38.1h5.1M189.2 27.9h5.1M189.2 30.5h5.1M189.2 33h5.1"/>
<path d="M168.9 40.6h5.1M168.9 43.2h5.1M168.9 45.7h5.1M168.9 48.3h5.1M168.9 50.8h5.1M168.9 53.3h5.1M168.9 55.9h5.1M168.9 58.4h5.1M189.2 40.6h5.1M189.2 43.2h5.1M189.2 45.7h5.1M189.2 48.3h5.1"/>
<path d="M189.2 50.8h5.1M189.2 53.3h5.1M189.2 55.9h5.1M189.2 58.4h5.1M168.9 61h5.1M168.9 63.5h5.1M168.9 66h5.1M168.9 68.6h5.1M168.9 71.1h5.1M168.9 73.7h5.1M168.9 76.2h5.1M168.9 78.7h5.1"/>
<path d="M189.2 61h5.1M189.2 63.5h5.1M189.2 66h5.1M189.2 68.6h5.1M189.2 71.1h5.1M189.2 73.7h5.1M189.2 76.2h5.1M189.2 78.7h5.1M168.9 81.3h5.1M168.9 83.8h5.1M168.9 86.4h5.1M168.9 88.9h5.1"/>
<path d="M168.9 91.4h5.1M168.9 94h5.1M168.9 96.5h5.1M168.9 99.1h5.1M189.2 81.3h5.1M189.2 83.8h5.1M189.2 86.4h5.1M189.2 88.9h5.1M189.2 91.4h5.1M189.2 94h5.1M189.2 96.5h5.1M189.2 99.1h5.1"/>
<path d="M168.9 101.6h5.1M168.9 104.1h5.1M168.9 106.7h5.1M168.9 109.2h5.1M168.9 111.8h5.1M168.9 114.3h5.1M168.9 116.8h5.1M168.9 119.4h5.1M189.2 101.6h5.1M189.2 104.1h5.1M189.2 106.7h5.1M189.2 109.2h5.1"/>
<path d="M189.2 111.8h5.1M189.2 114.3h5.1M189.2 116.8h5.1M189.2 119.4h5.1M168.9 121.9h5.1M168.9 124.5h5.1M168.9 127h5.1M168.9 129.5h5.1M168.9 132.1h5.1M168.9 134.6h5.1M168.9 137.2h5.1M168.9 139.7h5.1"/>
<path d="M189.2 121.9h5.1M189.2 124.5h5.1M189.2 127h5.1M189.2 129.5h5.1M189.2 132.1h5.1M189.2 134.6h5.1M189.2 137.2h5.1M189.2 139.7h5.1M168.9 149.9h5.1M168.9 142.2h5.1M168.9 144.8h5.1M168.9 147.3h5.1"/>
<path d="M189.2 149.9h5.1M189.2 142.2h5.1M189.2 144.8h5.1M189.2 147.3h5.1"/>
</g>
<g fill="none" stroke="#006464" stroke-width=".18">
<path d="M176.3 38.6h.5M190 20.1a1.46 1.46 0 0 0 0 1.9M191 20.2h-.6v.6l.2-.1 .4 .1 .1 .2-.1 .4-.1 .1-.5-.1M191.6 21.5h.7M191.6 20.6l.4-.4v1.3M192.7 20.1a1.46 1.46 0 0 1 0 1.9M176.3 51.3h.5M176.3 64h.5M176.3 76.7h.5M176.3 89.4h.5M176.3 102.1h.5M176.3 114.8h.5"/>
<path d="M176.3 127.5h.5M176.3 140.2h.5M187.8 149.4l.1 .3-.1 .5"/>
</g>
<path d="M171.6 37.7h.6M171.6 50.4h.6M171.6 63.1h.6M171.6 75.8h.6M171.6 88.5h.6M171.6 101.2h.6M171.6 113.9h.6M171.6 126.6h.6M171.6 139.3h.6M193 148.7v.6" fill="none" stroke="#a90000" stroke-width=".18"/>
<path d="M81.3 156.8h2.5v17.8h-2.5z" fill="#ffffc2"/>
<g fill="none" stroke="#840000" stroke-width=".18">
<path d="M42.7 17.7h5.7l1.1 1.4-1.1 1.3h-5.7zM49.5 19.1h5.1M54.6 16.5h27.9v38.1h-27.9zM82.5 19.1h5.1M88.8 17.7h5.8v2.7h-5.8l-1.2-1.3zM18 35.5h10.1l1.1 1.3-1.1 1.4h-10.1zM29.6 20.3h18.8l1.1 1.3-1.1 1.3h-18.8zM33.7 27.9h14.7l1.1 1.3-1.1 1.3h-14.7zM35.4 22.8h13l1.1 1.3-1.1 1.4h-13zM42.7 30.4h5.7l1.1 1.4-1.1 1.3h-5.7zM42.7 25.3h5.7l1.1 1.4-1.1 1.3h-5.7zM42.7 33h5.7l1.1 1.3-1.1 1.3h-5.7z"/>
<path d="M49.5 21.6h5.1M49.5 31.8h5.1M49.5 24.1h5.1M49.5 34.3h5.1M49.5 26.7h5.1M49.5 39.4h5.1M49.5 36.8h5.1M49.5 29.2h5.1M62.2 30.5h12.7v12.7h-12.7zM63.5 31.8h5.1v2.5h-5.1zM82.5 21.6h5.1M82.5 31.8h5.1"/>
<path d="M82.5 24.1h5.1M82.5 34.3h5.1M82.5 26.7h5.1M82.5 39.4h5.1M82.5 36.8h5.1M82.5 29.2h5.1M88.8 33h5.8v2.6h-5.8l-1.2-1.3zM88.8 25.3h5.8v2.7h-5.8l-1.2-1.3zM88.8 30.4h5.8v2.7h-5.8l-1.2-1.3zM156.9 34.2h9.6l1.1 1.4-1.1 1.3h-9.6zM156.9 29.1h9.6l1.1 1.4-1.1 1.3h-9.6zM157 36.8h9.5l1.1 1.3-1.1 1.3h-9.5z"/>
<path d="M157 26.6h9.5l1.1 1.3-1.1 1.4h-9.5zM160.6 24.1h5.9l1.1 1.3-1.1 1.3h-5.9zM160.6 31.7h5.9l1.1 1.3-1.1 1.4h-5.9zM160.6 39.3h5.9l1.1 1.3-1.1 1.4h-5.9zM196.7 31.7h5.9v2.7h-5.9l-1.1-1.4zM196.7 29.1h9.6v2.7h-9.6l-1.1-1.3zM196.7 34.2h9.6v2.7h-9.6l-1.1-1.3zM196.7 36.8h9.5v2.6h-9.5l-1.1-1.3zM196.7 39.3h5.9v2.7h-5.9l-1.1-1.4zM196.7 26.6h9.5v2.7h-9.5l-1.1-1.4zM196.7 24.1h5.9v2.6h-5.9l-1.1-1.3zM219.2 24.1h14.6l1.1 1.3-1.1 1.3h-14.6z"/>
<path d="M219.4 36.8h14.4l1.1 1.3-1.1 1.3h-14.4zM220.8 34.2h13l1.1 1.4-1.1 1.3h-13zM225.3 26.6h8.5l1.1 1.3-1.1 1.4h-8.5zM225.3 29.1h8.5l1.1 1.4-1.1 1.3h-8.5zM227.9 31.7h5.9l1.1 1.3-1.1 1.4h-5.9zM227.9 39.3h5.9l1.1 1.3-1.1 1.4h-5.9zM264 31.7h5.9v2.7h-5.9l-1.1-1.4zM264 36.8h14.5v2.6h-14.5l-1.1-1.3zM264 39.3h5.9v2.7h-5.9l-1.1-1.4zM264 24.1h18.8v2.6h-18.8l-1.1-1.3zM264 34.2h14.5v2.7h-14.5l-1.1-1.3zM31.2 45.7h17.2l1.1 1.3-1.1 1.3h-17.2z"/>
<path d="M38.5 43.3h10.1l.9 1.2-.9 1.1h-10.1l-1-1.1zM49.5 47h5.1M49.5 52.1h5.1M49.5 49.5h5.1M49.5 44.5h5.1M49.5 41.9h5.1M82.5 47h5.1M82.5 49.5h5.1M82.5 44.5h5.1M82.5 41.9h5.1M88.8 45.7h17.2v2.6h-17.2l-1.2-1.3zM103.7 47.2h1.2"/>
<path d="M120.2 55.2h13.3l1.1 1.3-1.1 1.3h-13.3zM120.3 57.7h13.2l1.1 1.4-1.1 1.3h-13.2zM147.1 49.5h19.4l1.1 1.3-1.1 1.3h-19.4zM153 44.4h13.5l1.1 1.3-1.1 1.4h-13.5zM153 41.8h13.5l1.1 1.4-1.1 1.3h-13.5zM153 46.9h13.5l1.1 1.4-1.1 1.3h-13.5zM157 54.5h9.5l1.1 1.4-1.1 1.3h-9.5zM157 59.6h9.5l1.1 1.4-1.1 1.3h-9.5zM157 57.1h9.5l1.1 1.3-1.1 1.4h-9.5zM160.6 52h5.9l1.1 1.3-1.1 1.4h-5.9zM164.9 56.7h.8M165.1 50.6l.3 1"/>
<path d="M165.4 51.6l-.1 .4-.2 .1M165.8 50.6l-.4 1M196.7 59.6h8.1v2.7h-8.1l-1.1-1.3zM196.7 41.8h15.9v2.7h-15.9l-1.1-1.3zM196.7 44.4h17.9v2.7h-17.9l-1.1-1.4zM196.7 54.5h9.5v2.7h-9.5l-1.1-1.3zM196.7 49.5h5.9v2.6h-5.9l-1.1-1.3zM196.7 46.9h16.2v2.7h-16.2l-1.1-1.3zM196.7 52h9.5v2.7h-9.5l-1.1-1.4zM196.7 57.1h9.5v2.7h-9.5l-1.1-1.4zM219.7 49.5h14.1l1.1 1.3-1.1 1.3h-14.1zM219.7 41.8h14.1l1.1 1.4-1.1 1.3h-14.1z"/>
<path d="M219.7 52h14.1l1.1 1.3-1.1 1.4h-14.1zM219.7 44.4h14.1l1.1 1.3-1.1 1.4h-14.1zM221.1 57.1h12.7l1.1 1.3-1.1 1.4h-12.7zM221.2 59.6h12.6l1.1 1.4-1.1 1.3h-12.6zM227.9 54.5h5.9l1.1 1.4-1.1 1.3h-5.9zM227.9 46.9h5.9l1.1 1.4-1.1 1.3h-5.9zM264 41.8h13.2v2.7h-13.2l-1.1-1.3zM264 59.6h14.1v2.7h-14.1l-1.1-1.3zM264 57.1h14.2v2.7h-14.2l-1.1-1.4zM264 52h12.9v2.7h-12.9l-1.1-1.4zM264 54.5h5.9v2.7h-5.9l-1.1-1.3zM264 46.9h5.9v2.7h-5.9l-1.1-1.3z"/>
<path d="M264 44.4h13.2v2.7h-13.2l-1.1-1.4zM264 49.5h12.8v2.6h-12.8l-1.1-1.3zM85.9 67.9h13.3l1.1 1.3-1.1 1.3h-13.3zM85.9 60.9h13.3l1.1 1.3-1.1 1.4h-13.3zM86 63.4h13.2l1.1 1.4-1.1 1.3h-13.2zM86 70.4h13.2l1.1 1.4-1.1 1.3h-13.2zM86.1 74.2h11.8l1.2 1.4-1.2 1.3h-11.8zM86.2 76.8h11.7l1.2 1.3-1.2 1.3h-11.7zM105.3 67.9h13.2v2.6h-13.2l-1.2-1.3zM105.3 60.9h13.2v2.7h-13.2l-1.2-1.4zM105.3 63.4h13.2v2.7h-13.2l-1.2-1.3zM105.3 70.4h13.2v2.7h-13.2l-1.2-1.3z"/>
<path d="M105.3 74.2h11.8v2.7h-11.8l-1.2-1.3zM105.3 76.8h11.7v2.6h-11.7l-1.2-1.3zM120.2 63.4h13.3l1.1 1.4-1.1 1.3h-13.3zM120.3 66h13.2l1.1 1.3-1.1 1.3h-13.2zM121.7 74.2h11.8l1.1 1.4-1.1 1.3h-11.8zM121.7 76.8h11.8l1.1 1.3-1.1 1.3h-11.8zM157 79.9h9.5l1.1 1.4-1.1 1.3h-9.5zM157 62.2h9.5l1.1 1.3-1.1 1.3h-9.5zM157 74.9h9.5l1.1 1.3-1.1 1.3h-9.5zM158.5 69.8h8l1.1 1.3-1.1 1.4h-8zM158.5 72.3h8l1.1 1.4-1.1 1.3h-8zM158.9 67.2h7.6l1.1 1.4-1.1 1.3h-7.6z"/>
<path d="M160.6 64.7h5.9l1.1 1.3-1.1 1.4h-5.9zM160.6 77.4h5.9l1.1 1.3-1.1 1.4h-5.9zM196.7 74.9h5.9v2.6h-5.9l-1.1-1.3zM196.7 72.3h8.1v2.7h-8.1l-1.1-1.3zM196.7 79.9h9.5v2.7h-9.5l-1.1-1.3zM196.7 77.4h9.5v2.7h-9.5l-1.1-1.4zM196.7 64.7h8.1v2.7h-8.1l-1.1-1.4zM196.7 67.2h7.6v2.7h-7.6l-1.1-1.3zM196.7 62.2h5.9v2.6h-5.9l-1.1-1.3zM196.7 69.8h9.5v2.7h-9.5l-1.1-1.4zM204.3 71.9h.9M214.2 77.4h19.6l1.1 1.3-1.1 1.4h-19.6z"/>
<path d="M219.7 72.3h14.1l1.1 1.4-1.1 1.3h-14.1zM219.7 64.7h14.1l1.1 1.3-1.1 1.4h-14.1zM219.7 74.9h14.1l1.1 1.3-1.1 1.3h-14.1zM219.7 67.2h14.1l1.1 1.4-1.1 1.3h-14.1zM220.1 79.9h13.7l1.1 1.4-1.1 1.3h-13.7zM227.9 69.8h5.9l1.1 1.3-1.1 1.4h-5.9zM227.9 62.2h5.9l1.1 1.3-1.1 1.3h-5.9zM264 64.7h14.2v2.7h-14.2l-1.1-1.4zM264 62.2h5.9v2.6h-5.9l-1.1-1.3zM264 67.2h14.1v2.7h-14.1l-1.1-1.3zM264 77.4h5.9v2.7h-5.9l-1.1-1.4zM264 74.9h12.6v2.6h-12.6l-1.1-1.3z"/>
<path d="M264 79.9h16.2v2.7h-16.2l-1.1-1.3zM264 72.3h12.7v2.7h-12.7l-1.1-1.3zM264 69.8h5.9v2.7h-5.9l-1.1-1.4zM14 81.2h14.1l1.1 1.4-1.1 1.3h-14.1zM23.8 96.5h24l1.1 1.3-1.1 1.3h-24zM30.6 99h17.2l1.1 1.3-1.1 1.4h-17.2zM31.8 83.8h14l1.2 1.3-1.2 1.3h-14zM33.7 93.9h14.1l1.1 1.4-1.1 1.3h-14.1zM33.7 88.8h14.1l1.1 1.4-1.1 1.3h-14.1zM40.9 91.4h6.9l1.1 1.3-1.1 1.3h-6.9zM40.9 86.3h6.9l1.1 1.3-1.1 1.4h-6.9zM45.7 98h1.2"/>
<path d="M88.1 96.5h24v2.6h-24l-1.1-1.3zM88.1 99h17.2v2.7h-17.2l-1.1-1.4zM88.1 93.9h14.2v2.7h-14.2l-1.1-1.3zM88.1 88.8h14.2v2.7h-14.2l-1.1-1.3zM88.1 86.3h6.8v2.7h-6.8l-1.1-1.4zM88.1 91.4h6.8v2.6h-6.8l-1.1-1.3zM90 83.8h14.2v2.6h-14.2l-1.1-1.3zM109.8 98h1.2M118.3 93.9h9.5l1.1 1.4-1.1 1.3h-9.5zM118.9 91.4h9.5l1.1 1.3-1.1 1.3h-9.5zM119.7 96.5h8.1l1.1 1.3-1.1 1.3h-8.1zM119.7 99h8.1l1.1 1.3-1.1 1.4h-8.1z"/>
<path d="M142.7 99h10.8v2.7h-10.8l-1.1-1.4zM142.7 93.9h10.8v2.7h-10.8l-1.1-1.3zM142.7 96.5h10.8v2.6h-10.8l-1.1-1.3zM142.7 91.4h9.7v2.6h-9.7l-1.1-1.3zM156.9 95.2h9.6l1.1 1.3-1.1 1.4h-9.6zM157 82.5h9.5l1.1 1.3-1.1 1.4h-9.5zM157 85h9.5l1.1 1.4-1.1 1.3h-9.5zM157 87.6h9.5l1.1 1.3-1.1 1.3h-9.5zM157 92.6h9.5l1.1 1.4-1.1 1.3h-9.5zM160.6 90.1h5.9l1.1 1.3-1.1 1.4h-5.9zM160.6 97.7h5.9l1.1 1.4-1.1 1.3h-5.9zM196.7 90.1h8.1v2.7h-8.1l-1.1-1.4z"/>
<path d="M196.7 92.6h8.1v2.7h-8.1l-1.1-1.3zM196.7 97.7h5.9v2.7h-5.9l-1.1-1.3zM196.7 95.2h8.1v2.7h-8.1l-1.1-1.4zM196.7 87.6h5.9v2.6h-5.9l-1.1-1.3zM196.7 85h9.5v2.7h-9.5l-1.1-1.3zM196.7 82.5h9.5v2.7h-9.5l-1.1-1.4zM214.2 90.1h19.6l1.1 1.3-1.1 1.4h-19.6zM220 87.6h13.8l1.1 1.3-1.1 1.3h-13.8zM220 85h13.8l1.1 1.4-1.1 1.3h-13.8zM220.2 82.5h13.6l1.1 1.3-1.1 1.4h-13.6zM220.5 95.2h13.3l1.1 1.3-1.1 1.4h-13.3zM220.6 97.7h13.2l1.1 1.4-1.1 1.3h-13.2z"/>
<path d="M227.9 92.6h5.9l1.1 1.4-1.1 1.3h-5.9zM264 82.5h16.3v2.7h-16.3l-1.1-1.4zM264 85h5.9v2.7h-5.9l-1.1-1.3zM264 95.2h16.2v2.7h-16.2l-1.1-1.4zM264 87.6h16.2v2.6h-16.2l-1.1-1.3zM264 92.6h5.9v2.7h-5.9l-1.1-1.3zM264 90.1h16.3v2.7h-16.3l-1.1-1.4zM264 97.7h16.3v2.7h-16.3l-1.1-1.3zM30.5 104.1h14.1l1.1 1.3-1.1 1.3h-14.1zM32.6 119.3h12.6l1.2 1.4-1.2 1.3h-12.6zM32.6 116.8h12.6l1.2 1.3-1.2 1.3h-12.6zM34 114.5h13.9l1 1.1-1 1.1h-13.9z"/>
<path d="M40.8 106.6h7l1.1 1.4-1.1 1.3h-7zM40.9 101.5h6.9l1.1 1.4-1.1 1.3h-6.9zM40.9 109.2h6.9l1.1 1.3-1.1 1.3h-6.9zM87.9 114.5h11.2v2.2h-11.2l-.9-1.1zM88.1 101.5h6.8v2.7h-6.8l-1.1-1.3zM88.1 106.6h7v2.7h-7l-1.1-1.3zM88.1 109.2h6.8v2.6h-6.8l-1.1-1.3zM88.1 111.7h9.5v2.7h-9.5l-1.1-1.4zM90 116.8h12.7v2.6h-12.7l-1.1-1.3zM90 119.3h12.7v2.7h-12.7l-1.1-1.3zM90.7 104.1h14.1v2.6h-14.1l-1.2-1.3zM92.9 114.6h5.5"/>
<path d="M103.1 100.6h1.1M118.3 104.1h9.5l1.1 1.3-1.1 1.3h-9.5zM119.7 101.5h8.1l1.1 1.4-1.1 1.3h-8.1zM124.4 113.2h2.7v12l-1.4 1.2-1.3-1.2zM125 114.1l1.5 .5M142.7 101.5h10.8v2.7h-10.8l-1.1-1.3zM142.7 104.1h10.2v2.6h-10.2l-1.1-1.3zM146.3 115.5h20.2l1.1 1.3-1.1 1.4h-20.2zM152 118h14.5l1.1 1.4-1.1 1.3h-14.5zM155.7 110.4h10.8l1.1 1.4-1.1 1.3h-10.8zM155.7 102.8h10.8l1.1 1.3-1.1 1.4h-10.8zM155.7 107.9h10.8l1.1 1.3-1.1 1.4h-10.8z"/>
<path d="M155.7 100.3h10.8l1.1 1.3-1.1 1.3h-10.8zM160.6 113h5.9l1.1 1.3-1.1 1.3h-5.9zM160.6 105.3h5.9l1.1 1.4-1.1 1.3h-5.9zM165.5 116.6l.2 .4-.7 .1M165.7 117.6h-.2M196.7 113h10.8v2.6h-10.8l-1.1-1.3zM196.7 100.3h10.2v2.6h-10.2l-1.1-1.3zM196.7 107.9h10.8v2.7h-10.8l-1.1-1.4zM196.7 102.8h10.8v2.7h-10.8l-1.1-1.4zM196.7 115.5h5.9v2.7h-5.9l-1.1-1.4zM196.7 110.4h10.8v2.7h-10.8l-1.1-1.3zM196.7 105.3h5.9v2.7h-5.9l-1.1-1.3z"/>
<path d="M220.5 118h13.3l1.1 1.4-1.1 1.3h-13.3zM220.5 102.8h13.3l1.1 1.3-1.1 1.4h-13.3zM220.6 105.3h13.2l1.1 1.4-1.1 1.3h-13.2zM222 110.4h11.8l1.1 1.4-1.1 1.3h-11.8zM222.1 113h11.7l1.1 1.3-1.1 1.3h-11.7zM227.9 115.5h5.9l1.1 1.3-1.1 1.4h-5.9zM227.9 100.3h5.9l1.1 1.3-1.1 1.3h-5.9zM227.9 107.9h5.9l1.1 1.3-1.1 1.4h-5.9zM264 107.9h5.9v2.7h-5.9l-1.1-1.4zM264 105.3h16.5v2.7h-16.5l-1.1-1.3zM264 115.5h5.9v2.7h-5.9l-1.1-1.4zM264 118h16.2v2.7h-16.2l-1.1-1.3z"/>
<path d="M264 113h16.3v2.6h-16.3l-1.1-1.3zM264 110.4h16.2v2.7h-16.2l-1.1-1.3zM264 100.3h5.9v2.6h-5.9l-1.1-1.3zM264 102.8h16.4v2.7h-16.4l-1.1-1.4zM41.3 137.1h13.4l1.2 1.3-1.2 1.4h-13.4zM41.3 139.6h13.4l1.2 1.4-1.2 1.3h-13.4zM41.3 134.6h13.4l1.2 1.3-1.2 1.3h-13.4zM151.4 135.8h15.1l1.1 1.4-1.1 1.3h-15.1zM151.7 138.4h14.8l1.1 1.3-1.1 1.3h-14.8zM165.1 139.6l.4-.1 .2 .4-.7 .1M165.2 136.9l.5 .1v.3l-.7 .2M165.7 137.9l-.5 .1"/>
<path d="M196.7 133.3h12.1v2.7h-12.1l-1.1-1.4zM196.7 130.7h12.1v2.7h-12.1l-1.1-1.3zM196.7 135.8h12.1v2.7h-12.1l-1.1-1.3zM196.7 138.4h10.2v2.6h-10.2l-1.1-1.3zM196.7 128.2h12.1v2.7h-12.1l-1.1-1.4zM196.7 123.1h6.9v2.7h-6.9l-1.1-1.3zM196.7 120.6h13.3v2.7h-13.3l-1.1-1.4zM196.7 125.7h7v2.6h-7l-1.1-1.3zM207.9 133.9l-.5 1.5M207.9 131.4l-.5 1.5M207.9 136.4l-.5 1.6M207.9 128.8l-.5 1.5"/>
<path d="M220.5 125.7h13.3l1.1 1.3-1.1 1.3h-13.3zM220.6 120.6h13.2l1.1 1.3-1.1 1.4h-13.2zM220.6 128.2h13.2l1.1 1.3-1.1 1.4h-13.2zM222 133.3h11.8l1.1 1.3-1.1 1.4h-11.8zM222.1 135.8h11.7l1.1 1.4-1.1 1.3h-11.7zM227.9 138.4h5.9l1.1 1.3-1.1 1.3h-5.9zM227.9 123.1h5.9l1.1 1.4-1.1 1.3h-5.9zM227.9 130.7h5.9l1.1 1.4-1.1 1.3h-5.9zM264 138.4h5.9v2.6h-5.9l-1.1-1.3zM264 133.3h16.4v2.7h-16.4l-1.1-1.4zM264 125.7h16.2v2.6h-16.2l-1.1-1.3zM264 130.7h5.9v2.7h-5.9l-1.1-1.3z"/>
<path d="M264 120.6h16.3v2.7h-16.3l-1.1-1.4zM264 123.1h5.9v2.7h-5.9l-1.1-1.3zM264 128.2h16.3v2.7h-16.3l-1.1-1.4zM264 135.8h16.5v2.7h-16.5l-1.1-1.3zM36.8 146h17.9l1.2 1.3-1.2 1.4h-17.9zM38.9 143.4h15.8l1.2 1.4-1.2 1.3h-15.8zM82.5 158h1.3v.2h-1.3zM83.8 158.1h3.8M88.8 156.8h5.8v2.6h-5.8l-1.2-1.3zM88.8 159.3h10v2.7h-10l-1.2-1.3zM150.2 146h16.3l1.1 1.3-1.1 1.4h-16.3zM150.4 143.4h16.1l1.1 1.4-1.1 1.3h-16.1z"/>
<path d="M152.7 148.5h13.8l1.1 1.4-1.1 1.3h-13.8zM154.2 140.9h12.3l1.1 1.3-1.1 1.4h-12.3zM165.1 140.4h.6M165.7 146.8a1.18 1.18 0 0 1-.2 1.3M196.7 146h5.9v2.7h-5.9l-1.1-1.4zM196.7 148.5h10.7v2.7h-10.7l-1.1-1.3zM196.7 143.4h12.6v2.7h-12.6l-1.1-1.3zM196.7 140.9h12.6v2.7h-12.6l-1.1-1.4zM207.4 143h.8M207.4 142l.4-.5v1.5M207.5 144.2l.2-.1a.83 .83 0 0 1 .6 .6 .83 .83 0 0 1-.3 .8l-.3 .1-.2-.2M220.1 148.5h13.7l1.1 1.4-1.1 1.3h-13.7z"/>
<path d="M220.5 140.9h13.3l1.1 1.3-1.1 1.4h-13.3zM220.6 143.4h13.2l1.1 1.4-1.1 1.3h-13.2zM227.9 146h5.9l1.1 1.3-1.1 1.4h-5.9zM264 148.5h13.7v2.7h-13.7l-1.1-1.3zM264 143.4h13.2v2.7h-13.2l-1.1-1.3zM264 140.9h13.3v2.7h-13.3l-1.1-1.4zM264 146h5.9v2.7h-5.9l-1.1-1.4zM82.5 160.5h1.3v.3h-1.3zM82.5 163.1h1.3v.2h-1.3zM82.5 165.6h1.3v.3h-1.3zM82.5 168.1h1.3v.3h-1.3zM82.5 170.7h1.3v.2h-1.3z"/>
<path d="M82.5 173.2h1.3v.3h-1.3zM83.8 173.4h3.8M83.8 170.8h3.8M83.8 168.3h3.8M83.8 165.7h3.8M83.8 163.2h3.8M83.8 160.7h3.8M88.8 161.9h10.1v2.6h-10.1l-1.2-1.3zM88.8 166.9h9.8v2.7h-9.8l-1.2-1.3zM88.8 164.4h9.7v2.7h-9.7l-1.2-1.4zM88.8 172h11.5v2.7h-11.5l-1.2-1.3zM88.8 169.5h11.4v2.6h-11.4l-1.2-1.3z"/>
</g>
<path d="M81.3 156.8h2.5v17.8h-2.5z" fill="none" stroke="#840000" stroke-width=".25"/>
<path d="M77.4 14.4h.3l.3 .3-.3 .4M77.4 15.1h.3M77.7 15.1l.2 .1 .1 .4-.2 .3h-.4M78.6 15.9h.8M78.6 14.8l.4-.4v1.5M81 14.6a.61 .61 0 0 0-.8 0 .61 .61 0 0 0-.2 .7 .57 .57 0 0 0 .3 .6 .57 .57 0 0 0 .7-.1M64 22.2h.7M66.5 24.7h.7M80.5 22.2h.7" fill="none" stroke="#006464" stroke-width=".18"/>
<path d="M52.9 18.6h.8M86 18.6h.7" fill="none" stroke="#a90000" stroke-width=".18"/>
<path d="M120.8 120h1.6M121.4 137.2h.3l.2 .7" fill="none" stroke="#0000c2" stroke-width=".18"/>
<g fill="none" stroke="#009600" stroke-width=".18">
<path d="M29.2 36.8h20.3M87.6 36.8h7M87.6 29.2h9.6M167.6 38.1h1.3M167.6 27.9h1.3M167.6 35.6h1.3M167.6 25.4h1.3M167.6 30.5h1.3M167.6 33h1.3M194.3 38.1h1.3M194.3 27.9h1.3M194.3 35.6h1.3"/>
<path d="M194.3 25.4h1.3M194.3 30.5h1.3M194.3 33h1.3M234.9 38.1h1.3M234.9 27.9h1.3M234.9 35.6h1.3M234.9 25.4h1.3M234.9 30.5h1.3M234.9 33h1.3M261.6 38.1h1.3M261.6 35.6h1.3M261.6 25.4h1.3"/>
<path d="M261.6 33h1.3M167.6 43.2h1.3M167.6 40.6h1.3M167.6 55.9h1.3M167.6 58.4h1.3M167.6 53.3h1.3M167.6 50.8h1.3M167.6 48.3h1.3M167.6 45.7h1.3M194.3 43.2h1.3M194.3 40.6h1.3M194.3 55.9h1.3"/>
<path d="M194.3 58.4h1.3M194.3 53.3h1.3M194.3 50.8h1.3M194.3 48.3h1.3M194.3 45.7h1.3M234.9 43.2h1.3M234.9 40.6h1.3M234.9 55.9h1.3M234.9 58.4h1.3M234.9 53.3h1.3M234.9 50.8h1.3M234.9 48.3h1.3"/>
<path d="M234.9 45.7h1.3M261.6 43.2h1.3M261.6 40.6h1.3M261.6 55.9h1.3M261.6 58.4h1.3M261.6 53.3h1.3M261.6 50.8h1.3M261.6 48.3h1.3M261.6 45.7h1.3M99.1 78.1h5M99.1 75.6h5M100.3 62.2h3.8"/>
<path d="M100.3 71.8h3.8M100.3 64.8h3.8M100.3 69.2h3.8M167.6 76.2h1.3M167.6 78.7h1.3M167.6 71.1h1.3M167.6 73.7h1.3M167.6 66h1.3M167.6 63.5h1.3M167.6 68.6h1.3M167.6 61h1.3M194.3 76.2h1.3"/>
<path d="M194.3 78.7h1.3M194.3 71.1h1.3M194.3 73.7h1.3M194.3 66h1.3M194.3 63.5h1.3M194.3 68.6h1.3M194.3 61h1.3M234.9 76.2h1.3M234.9 78.7h1.3M234.9 71.1h1.3M234.9 73.7h1.3M234.9 66h1.3"/>
<path d="M234.9 63.5h1.3M234.9 68.6h1.3M234.9 61h1.3M261.6 76.2h1.3M261.6 78.7h1.3M261.6 71.1h1.3M261.6 73.7h1.3M261.6 66h1.3M261.6 63.5h1.3M261.6 68.6h1.3M261.6 61h1.3M29.2 82.6h1.9"/>
<path d="M36.2 82.6h12.7M47 85.1h1.9M87 85.1h1.9M128.9 95.3h3.2M128.9 97.8h3.2M129.5 92.7h2.6M137.2 95.3h4.4M137.2 97.8h4.4M137.2 92.7h4.4M167.6 88.9h1.3M167.6 94h1.3M167.6 91.4h1.3"/>
<path d="M167.6 81.3h1.3M167.6 96.5h1.3M167.6 83.8h1.3M167.6 86.4h1.3M167.6 99.1h1.3M194.3 88.9h1.3M194.3 94h1.3M194.3 91.4h1.3M194.3 81.3h1.3M194.3 96.5h1.3M194.3 83.8h1.3M194.3 86.4h1.3"/>
<path d="M194.3 99.1h1.3M234.9 88.9h1.3M234.9 94h1.3M234.9 91.4h1.3M234.9 81.3h1.3M234.9 96.5h1.3M234.9 83.8h1.3M234.9 86.4h1.3M234.9 99.1h1.3M261.6 88.9h1.3M261.6 94h1.3M261.6 91.4h1.3"/>
<path d="M261.6 81.3h1.3M261.6 96.5h1.3M261.6 83.8h1.3M261.6 86.4h1.3M261.6 99.1h1.3M45.7 105.4h3.2M46.4 118.1h2.5M87 105.4h2.5M87 118.1h1.9M128.9 100.3h3.2M128.9 102.9h3.2M128.9 105.4h3.2"/>
<path d="M137.2 100.3h4.4M137.2 102.9h4.4M137.2 105.4h4.4M167.6 116.8h1.3M167.6 109.2h1.3M167.6 106.7h1.3M167.6 114.3h1.3M167.6 111.8h1.3M167.6 104.1h1.3M167.6 101.6h1.3M167.6 119.4h1.3M194.3 116.8h1.3"/>
<path d="M194.3 109.2h1.3M194.3 106.7h1.3M194.3 114.3h1.3M194.3 111.8h1.3M194.3 104.1h1.3M194.3 101.6h1.3M234.9 116.8h1.3M234.9 109.2h1.3M234.9 106.7h1.3M234.9 114.3h1.3M234.9 111.8h1.3M234.9 104.1h1.3"/>
<path d="M234.9 101.6h1.3M234.9 119.4h1.3M261.6 116.8h1.3M261.6 109.2h1.3M261.6 106.7h1.3M261.6 114.3h1.3M261.6 111.8h1.3M261.6 104.1h1.3M261.6 101.6h1.3M261.6 119.4h1.3M46.4 120.7h2.5M87 120.7h1.9"/>
<path d="M125.7 126.4v5M154.9 128.3h8.9M167.6 137.2h1.3M167.6 139.7h1.3M168.9 124.5h-7.6v7.6h7.6M168.9 127h-5.1v2.5h5.1M168.9 121.9h-11.4v12.7h11.4M194.3 124.5h1.3M194.3 127h1.3M194.3 121.9h1.3M194.3 129.5h1.3M194.3 132.1h1.3"/>
<path d="M194.3 134.6h1.3M194.3 137.2h1.3M194.3 139.7h1.3M234.9 124.5h1.3M234.9 127h1.3M234.9 121.9h1.3M234.9 129.5h1.3M234.9 132.1h1.3M234.9 134.6h1.3M234.9 137.2h1.3M234.9 139.7h1.3M261.6 124.5h1.3"/>
<path d="M261.6 127h1.3M261.6 121.9h1.3M261.6 129.5h1.3M261.6 132.1h1.3M261.6 134.6h1.3M261.6 137.2h1.3M261.6 139.7h1.3M167.6 142.2h1.3M167.6 144.8h1.3M167.6 149.9h1.3M167.6 147.3h1.3M194.3 142.2h1.3"/>
<path d="M194.3 144.8h1.3M194.3 149.9h1.3M194.3 147.3h1.3M234.9 142.2h1.3M234.9 144.8h1.3M234.9 149.9h1.3M234.9 147.3h1.3M261.6 142.2h1.3M261.6 144.8h1.3M261.6 149.9h1.3M261.6 147.3h1.3"/>
</g>
<path d="M48.9 51.5l1.2 1.2M48.9 48.9l1.2 1.2M50.1 51.5l-1.2 1.2M50.1 48.9l-1.2 1.2M87 48.9l1.2 1.2M88.2 48.9l-1.2 1.2" fill="none" stroke="#000084" stroke-width=".18"/>
<g fill="#009600" stroke="#009600" stroke-width=".18">
<circle cx="161.3" cy="128.3" r=".46"/>
<circle cx="157.5" cy="128.3" r=".46"/>
<circle cx="163.8" cy="128.3" r=".46"/>
<circle cx="41.3" cy="36.8" r=".46"/>
</g>
<use href="#words"/>
</svg>
